VERSION 5.8 ;
BUSBITCHARS "[]" ;
DIVIDERCHAR "/" ;
UNITS
    DATABASE MICRONS 1000 ;
END UNITS

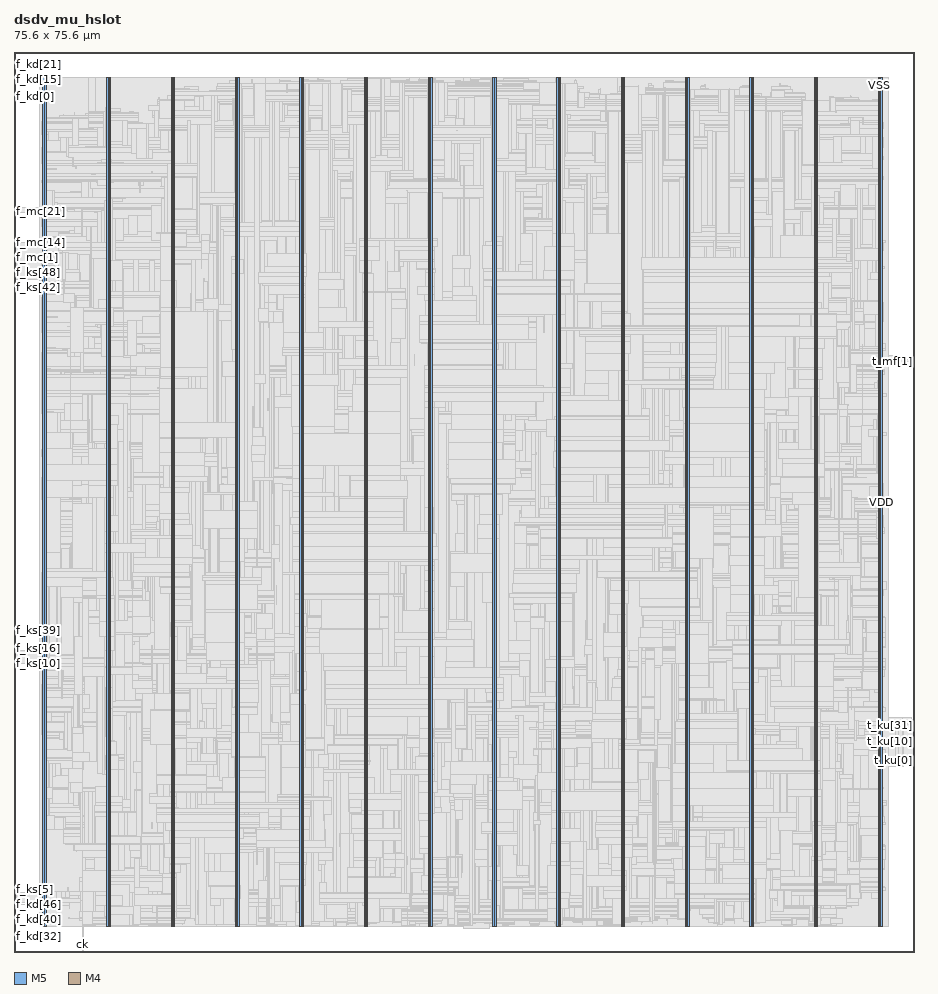
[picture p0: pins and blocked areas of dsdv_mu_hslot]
MACRO dsdv_mu_hslot
  FOREIGN dsdv_mu_hslot 0 0 ;
  CLASS BLOCK ;
  SIZE 75.6 BY 75.6 ;
  PIN ck
    DIRECTION INPUT ;
    USE SIGNAL ;
    PORT
      LAYER M5 ;
        RECT  5.712 0 5.736 0.084 ;
    END
  END ck
  PIN f_kd[0]
    DIRECTION INPUT ;
    USE SIGNAL ;
    PORT
      LAYER M4 ;
        RECT  0 71.856 0.084 71.88 ;
    END
  END f_kd[0]
  PIN f_kd[10]
    DIRECTION INPUT ;
    USE SIGNAL ;
    PORT
      LAYER M4 ;
        RECT  0 72.816 0.084 72.84 ;
    END
  END f_kd[10]
  PIN f_kd[11]
    DIRECTION INPUT ;
    USE SIGNAL ;
    PORT
      LAYER M4 ;
        RECT  0 72.912 0.084 72.936 ;
    END
  END f_kd[11]
  PIN f_kd[12]
    DIRECTION INPUT ;
    USE SIGNAL ;
    PORT
      LAYER M4 ;
        RECT  0 73.008 0.084 73.032 ;
    END
  END f_kd[12]
  PIN f_kd[13]
    DIRECTION INPUT ;
    USE SIGNAL ;
    PORT
      LAYER M4 ;
        RECT  0 73.104 0.084 73.128 ;
    END
  END f_kd[13]
  PIN f_kd[14]
    DIRECTION INPUT ;
    USE SIGNAL ;
    PORT
      LAYER M4 ;
        RECT  0 73.2 0.084 73.224 ;
    END
  END f_kd[14]
  PIN f_kd[15]
    DIRECTION INPUT ;
    USE SIGNAL ;
    PORT
      LAYER M4 ;
        RECT  0 73.296 0.084 73.32 ;
    END
  END f_kd[15]
  PIN f_kd[16]
    DIRECTION INPUT ;
    USE SIGNAL ;
    PORT
      LAYER M4 ;
        RECT  0 73.392 0.084 73.416 ;
    END
  END f_kd[16]
  PIN f_kd[17]
    DIRECTION INPUT ;
    USE SIGNAL ;
    PORT
      LAYER M4 ;
        RECT  0 73.488 0.084 73.512 ;
    END
  END f_kd[17]
  PIN f_kd[18]
    DIRECTION INPUT ;
    USE SIGNAL ;
    PORT
      LAYER M4 ;
        RECT  0 73.584 0.084 73.608 ;
    END
  END f_kd[18]
  PIN f_kd[19]
    DIRECTION INPUT ;
    USE SIGNAL ;
    PORT
      LAYER M4 ;
        RECT  0 73.68 0.084 73.704 ;
    END
  END f_kd[19]
  PIN f_kd[1]
    DIRECTION INPUT ;
    USE SIGNAL ;
    PORT
      LAYER M4 ;
        RECT  0 71.952 0.084 71.976 ;
    END
  END f_kd[1]
  PIN f_kd[20]
    DIRECTION INPUT ;
    USE SIGNAL ;
    PORT
      LAYER M4 ;
        RECT  0 73.776 0.084 73.8 ;
    END
  END f_kd[20]
  PIN f_kd[21]
    DIRECTION INPUT ;
    USE SIGNAL ;
    PORT
      LAYER M4 ;
        RECT  0 73.872 0.084 73.896 ;
    END
  END f_kd[21]
  PIN f_kd[22]
    DIRECTION INPUT ;
    USE SIGNAL ;
    PORT
      LAYER M4 ;
        RECT  0 73.968 0.084 73.992 ;
    END
  END f_kd[22]
  PIN f_kd[23]
    DIRECTION INPUT ;
    USE SIGNAL ;
    PORT
      LAYER M4 ;
        RECT  0 74.064 0.084 74.088 ;
    END
  END f_kd[23]
  PIN f_kd[24]
    DIRECTION INPUT ;
    USE SIGNAL ;
    PORT
      LAYER M4 ;
        RECT  0 74.16 0.084 74.184 ;
    END
  END f_kd[24]
  PIN f_kd[25]
    DIRECTION INPUT ;
    USE SIGNAL ;
    PORT
      LAYER M4 ;
        RECT  0 74.256 0.084 74.28 ;
    END
  END f_kd[25]
  PIN f_kd[26]
    DIRECTION INPUT ;
    USE SIGNAL ;
    PORT
      LAYER M4 ;
        RECT  0 74.352 0.084 74.376 ;
    END
  END f_kd[26]
  PIN f_kd[27]
    DIRECTION INPUT ;
    USE SIGNAL ;
    PORT
      LAYER M4 ;
        RECT  0 74.448 0.084 74.472 ;
    END
  END f_kd[27]
  PIN f_kd[28]
    DIRECTION INPUT ;
    USE SIGNAL ;
    PORT
      LAYER M4 ;
        RECT  0 74.544 0.084 74.568 ;
    END
  END f_kd[28]
  PIN f_kd[29]
    DIRECTION INPUT ;
    USE SIGNAL ;
    PORT
      LAYER M4 ;
        RECT  0 74.64 0.084 74.664 ;
    END
  END f_kd[29]
  PIN f_kd[2]
    DIRECTION INPUT ;
    USE SIGNAL ;
    PORT
      LAYER M4 ;
        RECT  0 72.048 0.084 72.072 ;
    END
  END f_kd[2]
  PIN f_kd[30]
    DIRECTION INPUT ;
    USE SIGNAL ;
    PORT
      LAYER M4 ;
        RECT  0 74.736 0.084 74.76 ;
    END
  END f_kd[30]
  PIN f_kd[31]
    DIRECTION INPUT ;
    USE SIGNAL ;
    PORT
      LAYER M4 ;
        RECT  0 74.832 0.084 74.856 ;
    END
  END f_kd[31]
  PIN f_kd[32]
    DIRECTION INPUT ;
    USE SIGNAL ;
    PORT
      LAYER M4 ;
        RECT  0 1.968 0.084 1.992 ;
    END
  END f_kd[32]
  PIN f_kd[33]
    DIRECTION INPUT ;
    USE SIGNAL ;
    PORT
      LAYER M4 ;
        RECT  0 2.064 0.084 2.088 ;
    END
  END f_kd[33]
  PIN f_kd[34]
    DIRECTION INPUT ;
    USE SIGNAL ;
    PORT
      LAYER M4 ;
        RECT  0 2.16 0.084 2.184 ;
    END
  END f_kd[34]
  PIN f_kd[35]
    DIRECTION INPUT ;
    USE SIGNAL ;
    PORT
      LAYER M4 ;
        RECT  0 2.256 0.084 2.28 ;
    END
  END f_kd[35]
  PIN f_kd[36]
    DIRECTION INPUT ;
    USE SIGNAL ;
    PORT
      LAYER M4 ;
        RECT  0 2.352 0.084 2.376 ;
    END
  END f_kd[36]
  PIN f_kd[37]
    DIRECTION INPUT ;
    USE SIGNAL ;
    PORT
      LAYER M4 ;
        RECT  0 2.448 0.084 2.472 ;
    END
  END f_kd[37]
  PIN f_kd[38]
    DIRECTION INPUT ;
    USE SIGNAL ;
    PORT
      LAYER M4 ;
        RECT  0 2.544 0.084 2.568 ;
    END
  END f_kd[38]
  PIN f_kd[39]
    DIRECTION INPUT ;
    USE SIGNAL ;
    PORT
      LAYER M4 ;
        RECT  0 2.64 0.084 2.664 ;
    END
  END f_kd[39]
  PIN f_kd[3]
    DIRECTION INPUT ;
    USE SIGNAL ;
    PORT
      LAYER M4 ;
        RECT  0 72.144 0.084 72.168 ;
    END
  END f_kd[3]
  PIN f_kd[40]
    DIRECTION INPUT ;
    USE SIGNAL ;
    PORT
      LAYER M4 ;
        RECT  0 2.736 0.084 2.76 ;
    END
  END f_kd[40]
  PIN f_kd[41]
    DIRECTION INPUT ;
    USE SIGNAL ;
    PORT
      LAYER M4 ;
        RECT  0 2.832 0.084 2.856 ;
    END
  END f_kd[41]
  PIN f_kd[42]
    DIRECTION INPUT ;
    USE SIGNAL ;
    PORT
      LAYER M4 ;
        RECT  0 2.928 0.084 2.952 ;
    END
  END f_kd[42]
  PIN f_kd[43]
    DIRECTION INPUT ;
    USE SIGNAL ;
    PORT
      LAYER M4 ;
        RECT  0 3.024 0.084 3.048 ;
    END
  END f_kd[43]
  PIN f_kd[44]
    DIRECTION INPUT ;
    USE SIGNAL ;
    PORT
      LAYER M4 ;
        RECT  0 3.12 0.084 3.144 ;
    END
  END f_kd[44]
  PIN f_kd[45]
    DIRECTION INPUT ;
    USE SIGNAL ;
    PORT
      LAYER M4 ;
        RECT  0 3.216 0.084 3.24 ;
    END
  END f_kd[45]
  PIN f_kd[46]
    DIRECTION INPUT ;
    USE SIGNAL ;
    PORT
      LAYER M4 ;
        RECT  0 3.312 0.084 3.336 ;
    END
  END f_kd[46]
  PIN f_kd[47]
    DIRECTION INPUT ;
    USE SIGNAL ;
    PORT
      LAYER M4 ;
        RECT  0 3.408 0.084 3.432 ;
    END
  END f_kd[47]
  PIN f_kd[48]
    DIRECTION INPUT ;
    USE SIGNAL ;
    PORT
      LAYER M4 ;
        RECT  0 3.504 0.084 3.528 ;
    END
  END f_kd[48]
  PIN f_kd[49]
    DIRECTION INPUT ;
    USE SIGNAL ;
    PORT
      LAYER M4 ;
        RECT  0 3.6 0.084 3.624 ;
    END
  END f_kd[49]
  PIN f_kd[4]
    DIRECTION INPUT ;
    USE SIGNAL ;
    PORT
      LAYER M4 ;
        RECT  0 72.24 0.084 72.264 ;
    END
  END f_kd[4]
  PIN f_kd[50]
    DIRECTION INPUT ;
    USE SIGNAL ;
    PORT
      LAYER M4 ;
        RECT  0 3.696 0.084 3.72 ;
    END
  END f_kd[50]
  PIN f_kd[51]
    DIRECTION INPUT ;
    USE SIGNAL ;
    PORT
      LAYER M4 ;
        RECT  0 3.792 0.084 3.816 ;
    END
  END f_kd[51]
  PIN f_kd[52]
    DIRECTION INPUT ;
    USE SIGNAL ;
    PORT
      LAYER M4 ;
        RECT  0 3.888 0.084 3.912 ;
    END
  END f_kd[52]
  PIN f_kd[53]
    DIRECTION INPUT ;
    USE SIGNAL ;
    PORT
      LAYER M4 ;
        RECT  0 3.984 0.084 4.008 ;
    END
  END f_kd[53]
  PIN f_kd[5]
    DIRECTION INPUT ;
    USE SIGNAL ;
    PORT
      LAYER M4 ;
        RECT  0 72.336 0.084 72.36 ;
    END
  END f_kd[5]
  PIN f_kd[6]
    DIRECTION INPUT ;
    USE SIGNAL ;
    PORT
      LAYER M4 ;
        RECT  0 72.432 0.084 72.456 ;
    END
  END f_kd[6]
  PIN f_kd[7]
    DIRECTION INPUT ;
    USE SIGNAL ;
    PORT
      LAYER M4 ;
        RECT  0 72.528 0.084 72.552 ;
    END
  END f_kd[7]
  PIN f_kd[8]
    DIRECTION INPUT ;
    USE SIGNAL ;
    PORT
      LAYER M4 ;
        RECT  0 72.624 0.084 72.648 ;
    END
  END f_kd[8]
  PIN f_kd[9]
    DIRECTION INPUT ;
    USE SIGNAL ;
    PORT
      LAYER M4 ;
        RECT  0 72.72 0.084 72.744 ;
    END
  END f_kd[9]
  PIN f_ks[0]
    DIRECTION INPUT ;
    USE SIGNAL ;
    PORT
      LAYER M4 ;
        RECT  0 4.08 0.084 4.104 ;
    END
  END f_ks[0]
  PIN f_ks[10]
    DIRECTION INPUT ;
    USE SIGNAL ;
    PORT
      LAYER M4 ;
        RECT  0 24.24 0.084 24.264 ;
    END
  END f_ks[10]
  PIN f_ks[11]
    DIRECTION INPUT ;
    USE SIGNAL ;
    PORT
      LAYER M4 ;
        RECT  0 24.336 0.084 24.36 ;
    END
  END f_ks[11]
  PIN f_ks[12]
    DIRECTION INPUT ;
    USE SIGNAL ;
    PORT
      LAYER M4 ;
        RECT  0 24.432 0.084 24.456 ;
    END
  END f_ks[12]
  PIN f_ks[13]
    DIRECTION INPUT ;
    USE SIGNAL ;
    PORT
      LAYER M4 ;
        RECT  0 24.528 0.084 24.552 ;
    END
  END f_ks[13]
  PIN f_ks[14]
    DIRECTION INPUT ;
    USE SIGNAL ;
    PORT
      LAYER M4 ;
        RECT  0 24.624 0.084 24.648 ;
    END
  END f_ks[14]
  PIN f_ks[15]
    DIRECTION INPUT ;
    USE SIGNAL ;
    PORT
      LAYER M4 ;
        RECT  0 24.72 0.084 24.744 ;
    END
  END f_ks[15]
  PIN f_ks[16]
    DIRECTION INPUT ;
    USE SIGNAL ;
    PORT
      LAYER M4 ;
        RECT  0 24.816 0.084 24.84 ;
    END
  END f_ks[16]
  PIN f_ks[17]
    DIRECTION INPUT ;
    USE SIGNAL ;
    PORT
      LAYER M4 ;
        RECT  0 24.912 0.084 24.936 ;
    END
  END f_ks[17]
  PIN f_ks[18]
    DIRECTION INPUT ;
    USE SIGNAL ;
    PORT
      LAYER M4 ;
        RECT  0 25.008 0.084 25.032 ;
    END
  END f_ks[18]
  PIN f_ks[19]
    DIRECTION INPUT ;
    USE SIGNAL ;
    PORT
      LAYER M4 ;
        RECT  0 25.104 0.084 25.128 ;
    END
  END f_ks[19]
  PIN f_ks[1]
    DIRECTION INPUT ;
    USE SIGNAL ;
    PORT
      LAYER M4 ;
        RECT  0 4.176 0.084 4.2 ;
    END
  END f_ks[1]
  PIN f_ks[20]
    DIRECTION INPUT ;
    USE SIGNAL ;
    PORT
      LAYER M4 ;
        RECT  0 25.2 0.084 25.224 ;
    END
  END f_ks[20]
  PIN f_ks[21]
    DIRECTION INPUT ;
    USE SIGNAL ;
    PORT
      LAYER M4 ;
        RECT  0 25.296 0.084 25.32 ;
    END
  END f_ks[21]
  PIN f_ks[22]
    DIRECTION INPUT ;
    USE SIGNAL ;
    PORT
      LAYER M4 ;
        RECT  0 25.392 0.084 25.416 ;
    END
  END f_ks[22]
  PIN f_ks[23]
    DIRECTION INPUT ;
    USE SIGNAL ;
    PORT
      LAYER M4 ;
        RECT  0 25.488 0.084 25.512 ;
    END
  END f_ks[23]
  PIN f_ks[24]
    DIRECTION INPUT ;
    USE SIGNAL ;
    PORT
      LAYER M4 ;
        RECT  0 25.584 0.084 25.608 ;
    END
  END f_ks[24]
  PIN f_ks[25]
    DIRECTION INPUT ;
    USE SIGNAL ;
    PORT
      LAYER M4 ;
        RECT  0 25.68 0.084 25.704 ;
    END
  END f_ks[25]
  PIN f_ks[26]
    DIRECTION INPUT ;
    USE SIGNAL ;
    PORT
      LAYER M4 ;
        RECT  0 25.776 0.084 25.8 ;
    END
  END f_ks[26]
  PIN f_ks[27]
    DIRECTION INPUT ;
    USE SIGNAL ;
    PORT
      LAYER M4 ;
        RECT  0 25.872 0.084 25.896 ;
    END
  END f_ks[27]
  PIN f_ks[28]
    DIRECTION INPUT ;
    USE SIGNAL ;
    PORT
      LAYER M4 ;
        RECT  0 25.968 0.084 25.992 ;
    END
  END f_ks[28]
  PIN f_ks[29]
    DIRECTION INPUT ;
    USE SIGNAL ;
    PORT
      LAYER M4 ;
        RECT  0 26.064 0.084 26.088 ;
    END
  END f_ks[29]
  PIN f_ks[2]
    DIRECTION INPUT ;
    USE SIGNAL ;
    PORT
      LAYER M4 ;
        RECT  0 4.272 0.084 4.296 ;
    END
  END f_ks[2]
  PIN f_ks[30]
    DIRECTION INPUT ;
    USE SIGNAL ;
    PORT
      LAYER M4 ;
        RECT  0 26.16 0.084 26.184 ;
    END
  END f_ks[30]
  PIN f_ks[31]
    DIRECTION INPUT ;
    USE SIGNAL ;
    PORT
      LAYER M4 ;
        RECT  0 26.256 0.084 26.28 ;
    END
  END f_ks[31]
  PIN f_ks[32]
    DIRECTION INPUT ;
    USE SIGNAL ;
    PORT
      LAYER M4 ;
        RECT  0 26.352 0.084 26.376 ;
    END
  END f_ks[32]
  PIN f_ks[33]
    DIRECTION INPUT ;
    USE SIGNAL ;
    PORT
      LAYER M4 ;
        RECT  0 26.448 0.084 26.472 ;
    END
  END f_ks[33]
  PIN f_ks[34]
    DIRECTION INPUT ;
    USE SIGNAL ;
    PORT
      LAYER M4 ;
        RECT  0 26.544 0.084 26.568 ;
    END
  END f_ks[34]
  PIN f_ks[35]
    DIRECTION INPUT ;
    USE SIGNAL ;
    PORT
      LAYER M4 ;
        RECT  0 26.64 0.084 26.664 ;
    END
  END f_ks[35]
  PIN f_ks[36]
    DIRECTION INPUT ;
    USE SIGNAL ;
    PORT
      LAYER M4 ;
        RECT  0 26.736 0.084 26.76 ;
    END
  END f_ks[36]
  PIN f_ks[37]
    DIRECTION INPUT ;
    USE SIGNAL ;
    PORT
      LAYER M4 ;
        RECT  0 26.832 0.084 26.856 ;
    END
  END f_ks[37]
  PIN f_ks[38]
    DIRECTION INPUT ;
    USE SIGNAL ;
    PORT
      LAYER M4 ;
        RECT  0 26.928 0.084 26.952 ;
    END
  END f_ks[38]
  PIN f_ks[39]
    DIRECTION INPUT ;
    USE SIGNAL ;
    PORT
      LAYER M4 ;
        RECT  0 27.024 0.084 27.048 ;
    END
  END f_ks[39]
  PIN f_ks[3]
    DIRECTION INPUT ;
    USE SIGNAL ;
    PORT
      LAYER M4 ;
        RECT  0 4.368 0.084 4.392 ;
    END
  END f_ks[3]
  PIN f_ks[40]
    DIRECTION INPUT ;
    USE SIGNAL ;
    PORT
      LAYER M4 ;
        RECT  0 27.12 0.084 27.144 ;
    END
  END f_ks[40]
  PIN f_ks[41]
    DIRECTION INPUT ;
    USE SIGNAL ;
    PORT
      LAYER M4 ;
        RECT  0 27.216 0.084 27.24 ;
    END
  END f_ks[41]
  PIN f_ks[42]
    DIRECTION INPUT ;
    USE SIGNAL ;
    PORT
      LAYER M4 ;
        RECT  0 56.496 0.084 56.52 ;
    END
  END f_ks[42]
  PIN f_ks[43]
    DIRECTION INPUT ;
    USE SIGNAL ;
    PORT
      LAYER M4 ;
        RECT  0 56.592 0.084 56.616 ;
    END
  END f_ks[43]
  PIN f_ks[44]
    DIRECTION INPUT ;
    USE SIGNAL ;
    PORT
      LAYER M4 ;
        RECT  0 56.688 0.084 56.712 ;
    END
  END f_ks[44]
  PIN f_ks[45]
    DIRECTION INPUT ;
    USE SIGNAL ;
    PORT
      LAYER M4 ;
        RECT  0 56.784 0.084 56.808 ;
    END
  END f_ks[45]
  PIN f_ks[46]
    DIRECTION INPUT ;
    USE SIGNAL ;
    PORT
      LAYER M4 ;
        RECT  0 56.88 0.084 56.904 ;
    END
  END f_ks[46]
  PIN f_ks[47]
    DIRECTION INPUT ;
    USE SIGNAL ;
    PORT
      LAYER M4 ;
        RECT  0 56.976 0.084 57 ;
    END
  END f_ks[47]
  PIN f_ks[48]
    DIRECTION INPUT ;
    USE SIGNAL ;
    PORT
      LAYER M4 ;
        RECT  0 57.072 0.084 57.096 ;
    END
  END f_ks[48]
  PIN f_ks[49]
    DIRECTION INPUT ;
    USE SIGNAL ;
    PORT
      LAYER M4 ;
        RECT  0 57.168 0.084 57.192 ;
    END
  END f_ks[49]
  PIN f_ks[4]
    DIRECTION INPUT ;
    USE SIGNAL ;
    PORT
      LAYER M4 ;
        RECT  0 4.464 0.084 4.488 ;
    END
  END f_ks[4]
  PIN f_ks[50]
    DIRECTION INPUT ;
    USE SIGNAL ;
    PORT
      LAYER M4 ;
        RECT  0 57.264 0.084 57.288 ;
    END
  END f_ks[50]
  PIN f_ks[51]
    DIRECTION INPUT ;
    USE SIGNAL ;
    PORT
      LAYER M4 ;
        RECT  0 57.36 0.084 57.384 ;
    END
  END f_ks[51]
  PIN f_ks[52]
    DIRECTION INPUT ;
    USE SIGNAL ;
    PORT
      LAYER M4 ;
        RECT  0 57.456 0.084 57.48 ;
    END
  END f_ks[52]
  PIN f_ks[5]
    DIRECTION INPUT ;
    USE SIGNAL ;
    PORT
      LAYER M4 ;
        RECT  0 4.56 0.084 4.584 ;
    END
  END f_ks[5]
  PIN f_ks[6]
    DIRECTION INPUT ;
    USE SIGNAL ;
    PORT
      LAYER M4 ;
        RECT  0 4.656 0.084 4.68 ;
    END
  END f_ks[6]
  PIN f_ks[7]
    DIRECTION INPUT ;
    USE SIGNAL ;
    PORT
      LAYER M4 ;
        RECT  0 4.752 0.084 4.776 ;
    END
  END f_ks[7]
  PIN f_ks[8]
    DIRECTION INPUT ;
    USE SIGNAL ;
    PORT
      LAYER M4 ;
        RECT  0 4.848 0.084 4.872 ;
    END
  END f_ks[8]
  PIN f_ks[9]
    DIRECTION INPUT ;
    USE SIGNAL ;
    PORT
      LAYER M4 ;
        RECT  0 4.944 0.084 4.968 ;
    END
  END f_ks[9]
  PIN f_mc[0]
    DIRECTION INPUT ;
    USE SIGNAL ;
    PORT
      LAYER M4 ;
        RECT  0 57.552 0.084 57.576 ;
    END
  END f_mc[0]
  PIN f_mc[10]
    DIRECTION INPUT ;
    USE SIGNAL ;
    PORT
      LAYER M4 ;
        RECT  0 58.512 0.084 58.536 ;
    END
  END f_mc[10]
  PIN f_mc[11]
    DIRECTION INPUT ;
    USE SIGNAL ;
    PORT
      LAYER M4 ;
        RECT  0 58.608 0.084 58.632 ;
    END
  END f_mc[11]
  PIN f_mc[12]
    DIRECTION INPUT ;
    USE SIGNAL ;
    PORT
      LAYER M4 ;
        RECT  0 58.704 0.084 58.728 ;
    END
  END f_mc[12]
  PIN f_mc[13]
    DIRECTION INPUT ;
    USE SIGNAL ;
    PORT
      LAYER M4 ;
        RECT  0 58.8 0.084 58.824 ;
    END
  END f_mc[13]
  PIN f_mc[14]
    DIRECTION INPUT ;
    USE SIGNAL ;
    PORT
      LAYER M4 ;
        RECT  0 58.896 0.084 58.92 ;
    END
  END f_mc[14]
  PIN f_mc[15]
    DIRECTION INPUT ;
    USE SIGNAL ;
    PORT
      LAYER M4 ;
        RECT  0 58.992 0.084 59.016 ;
    END
  END f_mc[15]
  PIN f_mc[16]
    DIRECTION INPUT ;
    USE SIGNAL ;
    PORT
      LAYER M4 ;
        RECT  0 59.088 0.084 59.112 ;
    END
  END f_mc[16]
  PIN f_mc[17]
    DIRECTION INPUT ;
    USE SIGNAL ;
    PORT
      LAYER M4 ;
        RECT  0 59.184 0.084 59.208 ;
    END
  END f_mc[17]
  PIN f_mc[18]
    DIRECTION INPUT ;
    USE SIGNAL ;
    PORT
      LAYER M4 ;
        RECT  0 59.28 0.084 59.304 ;
    END
  END f_mc[18]
  PIN f_mc[19]
    DIRECTION INPUT ;
    USE SIGNAL ;
    PORT
      LAYER M4 ;
        RECT  0 59.376 0.084 59.4 ;
    END
  END f_mc[19]
  PIN f_mc[1]
    DIRECTION INPUT ;
    USE SIGNAL ;
    PORT
      LAYER M4 ;
        RECT  0 57.648 0.084 57.672 ;
    END
  END f_mc[1]
  PIN f_mc[20]
    DIRECTION INPUT ;
    USE SIGNAL ;
    PORT
      LAYER M4 ;
        RECT  0 59.472 0.084 59.496 ;
    END
  END f_mc[20]
  PIN f_mc[21]
    DIRECTION INPUT ;
    USE SIGNAL ;
    PORT
      LAYER M4 ;
        RECT  0 62.16 0.084 62.184 ;
    END
  END f_mc[21]
  PIN f_mc[22]
    DIRECTION INPUT ;
    USE SIGNAL ;
    PORT
      LAYER M4 ;
        RECT  0 62.256 0.084 62.28 ;
    END
  END f_mc[22]
  PIN f_mc[23]
    DIRECTION INPUT ;
    USE SIGNAL ;
    PORT
      LAYER M4 ;
        RECT  0 62.352 0.084 62.376 ;
    END
  END f_mc[23]
  PIN f_mc[24]
    DIRECTION INPUT ;
    USE SIGNAL ;
    PORT
      LAYER M4 ;
        RECT  0 62.448 0.084 62.472 ;
    END
  END f_mc[24]
  PIN f_mc[25]
    DIRECTION INPUT ;
    USE SIGNAL ;
    PORT
      LAYER M4 ;
        RECT  0 62.544 0.084 62.568 ;
    END
  END f_mc[25]
  PIN f_mc[2]
    DIRECTION INPUT ;
    USE SIGNAL ;
    PORT
      LAYER M4 ;
        RECT  0 57.744 0.084 57.768 ;
    END
  END f_mc[2]
  PIN f_mc[3]
    DIRECTION INPUT ;
    USE SIGNAL ;
    PORT
      LAYER M4 ;
        RECT  0 57.84 0.084 57.864 ;
    END
  END f_mc[3]
  PIN f_mc[4]
    DIRECTION INPUT ;
    USE SIGNAL ;
    PORT
      LAYER M4 ;
        RECT  0 57.936 0.084 57.96 ;
    END
  END f_mc[4]
  PIN f_mc[5]
    DIRECTION INPUT ;
    USE SIGNAL ;
    PORT
      LAYER M4 ;
        RECT  0 58.032 0.084 58.056 ;
    END
  END f_mc[5]
  PIN f_mc[6]
    DIRECTION INPUT ;
    USE SIGNAL ;
    PORT
      LAYER M4 ;
        RECT  0 58.128 0.084 58.152 ;
    END
  END f_mc[6]
  PIN f_mc[7]
    DIRECTION INPUT ;
    USE SIGNAL ;
    PORT
      LAYER M4 ;
        RECT  0 58.224 0.084 58.248 ;
    END
  END f_mc[7]
  PIN f_mc[8]
    DIRECTION INPUT ;
    USE SIGNAL ;
    PORT
      LAYER M4 ;
        RECT  0 58.32 0.084 58.344 ;
    END
  END f_mc[8]
  PIN f_mc[9]
    DIRECTION INPUT ;
    USE SIGNAL ;
    PORT
      LAYER M4 ;
        RECT  0 58.416 0.084 58.44 ;
    END
  END f_mc[9]
  PIN rst_n
    DIRECTION INPUT ;
    USE SIGNAL ;
    PORT
      LAYER M5 ;
        RECT  5.808 0 5.832 0.084 ;
    END
  END rst_n
  PIN t_ku[0]
    DIRECTION OUTPUT ;
    USE SIGNAL ;
    PORT
      LAYER M4 ;
        RECT  75.516 16.08 75.6 16.104 ;
    END
  END t_ku[0]
  PIN t_ku[10]
    DIRECTION OUTPUT ;
    USE SIGNAL ;
    PORT
      LAYER M4 ;
        RECT  75.516 17.04 75.6 17.064 ;
    END
  END t_ku[10]
  PIN t_ku[11]
    DIRECTION OUTPUT ;
    USE SIGNAL ;
    PORT
      LAYER M4 ;
        RECT  75.516 17.136 75.6 17.16 ;
    END
  END t_ku[11]
  PIN t_ku[12]
    DIRECTION OUTPUT ;
    USE SIGNAL ;
    PORT
      LAYER M4 ;
        RECT  75.516 17.232 75.6 17.256 ;
    END
  END t_ku[12]
  PIN t_ku[13]
    DIRECTION OUTPUT ;
    USE SIGNAL ;
    PORT
      LAYER M4 ;
        RECT  75.516 17.328 75.6 17.352 ;
    END
  END t_ku[13]
  PIN t_ku[14]
    DIRECTION OUTPUT ;
    USE SIGNAL ;
    PORT
      LAYER M4 ;
        RECT  75.516 17.424 75.6 17.448 ;
    END
  END t_ku[14]
  PIN t_ku[15]
    DIRECTION OUTPUT ;
    USE SIGNAL ;
    PORT
      LAYER M4 ;
        RECT  75.516 17.52 75.6 17.544 ;
    END
  END t_ku[15]
  PIN t_ku[16]
    DIRECTION OUTPUT ;
    USE SIGNAL ;
    PORT
      LAYER M4 ;
        RECT  75.516 17.616 75.6 17.64 ;
    END
  END t_ku[16]
  PIN t_ku[17]
    DIRECTION OUTPUT ;
    USE SIGNAL ;
    PORT
      LAYER M4 ;
        RECT  75.516 17.712 75.6 17.736 ;
    END
  END t_ku[17]
  PIN t_ku[18]
    DIRECTION OUTPUT ;
    USE SIGNAL ;
    PORT
      LAYER M4 ;
        RECT  75.516 17.808 75.6 17.832 ;
    END
  END t_ku[18]
  PIN t_ku[19]
    DIRECTION OUTPUT ;
    USE SIGNAL ;
    PORT
      LAYER M4 ;
        RECT  75.516 17.904 75.6 17.928 ;
    END
  END t_ku[19]
  PIN t_ku[1]
    DIRECTION OUTPUT ;
    USE SIGNAL ;
    PORT
      LAYER M4 ;
        RECT  75.516 16.176 75.6 16.2 ;
    END
  END t_ku[1]
  PIN t_ku[20]
    DIRECTION OUTPUT ;
    USE SIGNAL ;
    PORT
      LAYER M4 ;
        RECT  75.516 18 75.6 18.024 ;
    END
  END t_ku[20]
  PIN t_ku[21]
    DIRECTION OUTPUT ;
    USE SIGNAL ;
    PORT
      LAYER M4 ;
        RECT  75.516 18.096 75.6 18.12 ;
    END
  END t_ku[21]
  PIN t_ku[22]
    DIRECTION OUTPUT ;
    USE SIGNAL ;
    PORT
      LAYER M4 ;
        RECT  75.516 18.192 75.6 18.216 ;
    END
  END t_ku[22]
  PIN t_ku[23]
    DIRECTION OUTPUT ;
    USE SIGNAL ;
    PORT
      LAYER M4 ;
        RECT  75.516 18.288 75.6 18.312 ;
    END
  END t_ku[23]
  PIN t_ku[24]
    DIRECTION OUTPUT ;
    USE SIGNAL ;
    PORT
      LAYER M4 ;
        RECT  75.516 18.384 75.6 18.408 ;
    END
  END t_ku[24]
  PIN t_ku[25]
    DIRECTION OUTPUT ;
    USE SIGNAL ;
    PORT
      LAYER M4 ;
        RECT  75.516 18.48 75.6 18.504 ;
    END
  END t_ku[25]
  PIN t_ku[26]
    DIRECTION OUTPUT ;
    USE SIGNAL ;
    PORT
      LAYER M4 ;
        RECT  75.516 18.576 75.6 18.6 ;
    END
  END t_ku[26]
  PIN t_ku[27]
    DIRECTION OUTPUT ;
    USE SIGNAL ;
    PORT
      LAYER M4 ;
        RECT  75.516 18.672 75.6 18.696 ;
    END
  END t_ku[27]
  PIN t_ku[28]
    DIRECTION OUTPUT ;
    USE SIGNAL ;
    PORT
      LAYER M4 ;
        RECT  75.516 18.768 75.6 18.792 ;
    END
  END t_ku[28]
  PIN t_ku[29]
    DIRECTION OUTPUT ;
    USE SIGNAL ;
    PORT
      LAYER M4 ;
        RECT  75.516 18.864 75.6 18.888 ;
    END
  END t_ku[29]
  PIN t_ku[2]
    DIRECTION OUTPUT ;
    USE SIGNAL ;
    PORT
      LAYER M4 ;
        RECT  75.516 16.272 75.6 16.296 ;
    END
  END t_ku[2]
  PIN t_ku[30]
    DIRECTION OUTPUT ;
    USE SIGNAL ;
    PORT
      LAYER M4 ;
        RECT  75.516 18.96 75.6 18.984 ;
    END
  END t_ku[30]
  PIN t_ku[31]
    DIRECTION OUTPUT ;
    USE SIGNAL ;
    PORT
      LAYER M4 ;
        RECT  75.516 19.056 75.6 19.08 ;
    END
  END t_ku[31]
  PIN t_ku[3]
    DIRECTION OUTPUT ;
    USE SIGNAL ;
    PORT
      LAYER M4 ;
        RECT  75.516 16.368 75.6 16.392 ;
    END
  END t_ku[3]
  PIN t_ku[4]
    DIRECTION OUTPUT ;
    USE SIGNAL ;
    PORT
      LAYER M4 ;
        RECT  75.516 16.464 75.6 16.488 ;
    END
  END t_ku[4]
  PIN t_ku[5]
    DIRECTION OUTPUT ;
    USE SIGNAL ;
    PORT
      LAYER M4 ;
        RECT  75.516 16.56 75.6 16.584 ;
    END
  END t_ku[5]
  PIN t_ku[6]
    DIRECTION OUTPUT ;
    USE SIGNAL ;
    PORT
      LAYER M4 ;
        RECT  75.516 16.656 75.6 16.68 ;
    END
  END t_ku[6]
  PIN t_ku[7]
    DIRECTION OUTPUT ;
    USE SIGNAL ;
    PORT
      LAYER M4 ;
        RECT  75.516 16.752 75.6 16.776 ;
    END
  END t_ku[7]
  PIN t_ku[8]
    DIRECTION OUTPUT ;
    USE SIGNAL ;
    PORT
      LAYER M4 ;
        RECT  75.516 16.848 75.6 16.872 ;
    END
  END t_ku[8]
  PIN t_ku[9]
    DIRECTION OUTPUT ;
    USE SIGNAL ;
    PORT
      LAYER M4 ;
        RECT  75.516 16.944 75.6 16.968 ;
    END
  END t_ku[9]
  PIN t_mf[0]
    DIRECTION OUTPUT ;
    USE SIGNAL ;
    PORT
      LAYER M4 ;
        RECT  75.516 49.488 75.6 49.512 ;
    END
  END t_mf[0]
  PIN t_mf[1]
    DIRECTION OUTPUT ;
    USE SIGNAL ;
    PORT
      LAYER M4 ;
        RECT  75.516 49.584 75.6 49.608 ;
    END
  END t_mf[1]
  PIN t_mf[2]
    DIRECTION OUTPUT ;
    USE SIGNAL ;
    PORT
      LAYER M4 ;
        RECT  75.516 49.68 75.6 49.704 ;
    END
  END t_mf[2]
  PIN t_mf[3]
    DIRECTION OUTPUT ;
    USE SIGNAL ;
    PORT
      LAYER M4 ;
        RECT  75.516 49.776 75.6 49.8 ;
    END
  END t_mf[3]
  PIN VDD
    DIRECTION INOUT ;
    USE POWER ;
    PORT
      LAYER M5 ;
        RECT  72.792 2.151 72.912 73.449 ;
        RECT  67.392 2.151 67.512 73.449 ;
        RECT  61.992 2.151 62.112 73.449 ;
        RECT  56.592 2.151 56.712 73.449 ;
        RECT  51.192 2.151 51.312 73.449 ;
        RECT  45.792 2.151 45.912 73.449 ;
        RECT  40.392 2.151 40.512 73.449 ;
        RECT  34.992 2.151 35.112 73.449 ;
        RECT  29.592 2.151 29.712 73.449 ;
        RECT  24.192 2.151 24.312 73.449 ;
        RECT  18.792 2.151 18.912 73.449 ;
        RECT  13.392 2.151 13.512 73.449 ;
        RECT  7.992 2.151 8.112 73.449 ;
        RECT  2.592 2.151 2.712 73.449 ;
    END
  END VDD
  PIN VSS
    DIRECTION INOUT ;
    USE GROUND ;
    PORT
      LAYER M5 ;
        RECT  72.6 2.137 72.72 73.463 ;
        RECT  67.2 2.137 67.32 73.463 ;
        RECT  61.8 2.137 61.92 73.463 ;
        RECT  56.4 2.137 56.52 73.463 ;
        RECT  51 2.137 51.12 73.463 ;
        RECT  45.6 2.137 45.72 73.463 ;
        RECT  40.2 2.137 40.32 73.463 ;
        RECT  34.8 2.137 34.92 73.463 ;
        RECT  29.4 2.137 29.52 73.463 ;
        RECT  24 2.137 24.12 73.463 ;
        RECT  18.6 2.137 18.72 73.463 ;
        RECT  13.2 2.137 13.32 73.463 ;
        RECT  7.8 2.137 7.92 73.463 ;
        RECT  2.4 2.137 2.52 73.463 ;
    END
  END VSS
  OBS
    LAYER RVTN ;
     RECT  2.16 2.16 73.44 2.295 ;
     RECT  2.16 2.565 73.44 2.835 ;
     RECT  2.16 3.105 73.44 3.375 ;
     RECT  2.16 3.645 73.44 3.915 ;
     RECT  2.16 4.185 73.44 4.455 ;
     RECT  2.16 4.725 73.44 4.995 ;
     RECT  2.16 5.265 73.44 5.535 ;
     RECT  2.16 5.805 73.44 6.075 ;
     RECT  2.16 6.345 73.44 6.615 ;
     RECT  2.16 6.885 73.44 7.155 ;
     RECT  2.16 7.425 73.44 7.695 ;
     RECT  2.16 7.965 73.44 8.235 ;
     RECT  2.16 8.505 73.44 8.775 ;
     RECT  2.16 9.045 73.44 9.315 ;
     RECT  2.16 9.585 73.44 9.855 ;
     RECT  2.16 10.125 73.44 10.395 ;
     RECT  2.16 10.665 73.44 10.935 ;
     RECT  2.16 11.205 73.44 11.475 ;
     RECT  2.16 11.745 73.44 12.015 ;
     RECT  2.16 12.285 73.44 12.555 ;
     RECT  2.16 12.825 73.44 13.095 ;
     RECT  2.16 13.365 73.44 13.635 ;
     RECT  2.16 13.905 73.44 14.175 ;
     RECT  2.16 14.445 73.44 14.715 ;
     RECT  2.16 14.985 73.44 15.255 ;
     RECT  2.16 15.525 73.44 15.795 ;
     RECT  2.16 16.065 73.44 16.335 ;
     RECT  2.16 16.605 73.44 16.875 ;
     RECT  2.16 17.145 73.44 17.415 ;
     RECT  2.16 17.685 73.44 17.955 ;
     RECT  2.16 18.225 73.44 18.495 ;
     RECT  2.16 18.765 73.44 19.035 ;
     RECT  2.16 19.305 73.44 19.575 ;
     RECT  2.16 19.845 73.44 20.115 ;
     RECT  2.16 20.385 73.44 20.655 ;
     RECT  2.16 20.925 73.44 21.195 ;
     RECT  2.16 21.465 73.44 21.735 ;
     RECT  2.16 22.005 73.44 22.275 ;
     RECT  2.16 22.545 73.44 22.815 ;
     RECT  2.16 23.085 73.44 23.355 ;
     RECT  2.16 23.625 73.44 23.895 ;
     RECT  2.16 24.165 73.44 24.435 ;
     RECT  2.16 24.705 73.44 24.975 ;
     RECT  2.16 25.245 73.44 25.515 ;
     RECT  2.16 25.785 73.44 26.055 ;
     RECT  2.16 26.325 73.44 26.595 ;
     RECT  2.16 26.865 73.44 27.135 ;
     RECT  2.16 27.405 73.44 27.675 ;
     RECT  2.16 27.945 73.44 28.215 ;
     RECT  2.16 28.485 73.44 28.755 ;
     RECT  2.16 29.025 73.44 29.295 ;
     RECT  2.16 29.565 73.44 29.835 ;
     RECT  2.16 30.105 73.44 30.375 ;
     RECT  2.16 30.645 73.44 30.915 ;
     RECT  2.16 31.185 73.44 31.455 ;
     RECT  2.16 31.725 73.44 31.995 ;
     RECT  2.16 32.265 73.44 32.535 ;
     RECT  2.16 32.805 73.44 33.075 ;
     RECT  2.16 33.345 73.44 33.615 ;
     RECT  2.16 33.885 73.44 34.155 ;
     RECT  2.16 34.425 73.44 34.695 ;
     RECT  2.16 34.965 73.44 35.235 ;
     RECT  2.16 35.505 73.44 35.775 ;
     RECT  2.16 36.045 73.44 36.315 ;
     RECT  2.16 36.585 73.44 36.855 ;
     RECT  2.16 37.125 73.44 37.395 ;
     RECT  2.16 37.665 73.44 37.935 ;
     RECT  2.16 38.205 73.44 38.475 ;
     RECT  2.16 38.745 73.44 39.015 ;
     RECT  2.16 39.285 73.44 39.555 ;
     RECT  2.16 39.825 73.44 40.095 ;
     RECT  2.16 40.365 73.44 40.635 ;
     RECT  2.16 40.905 73.44 41.175 ;
     RECT  2.16 41.445 73.44 41.715 ;
     RECT  2.16 41.985 73.44 42.255 ;
     RECT  2.16 42.525 73.44 42.795 ;
     RECT  2.16 43.065 73.44 43.335 ;
     RECT  2.16 43.605 73.44 43.875 ;
     RECT  2.16 44.145 73.44 44.415 ;
     RECT  2.16 44.685 73.44 44.955 ;
     RECT  2.16 45.225 73.44 45.495 ;
     RECT  2.16 45.765 73.44 46.035 ;
     RECT  2.16 46.305 73.44 46.575 ;
     RECT  2.16 46.845 73.44 47.115 ;
     RECT  2.16 47.385 73.44 47.655 ;
     RECT  2.16 47.925 73.44 48.195 ;
     RECT  2.16 48.465 73.44 48.735 ;
     RECT  2.16 49.005 73.44 49.275 ;
     RECT  2.16 49.545 73.44 49.815 ;
     RECT  2.16 50.085 73.44 50.355 ;
     RECT  2.16 50.625 73.44 50.895 ;
     RECT  2.16 51.165 73.44 51.435 ;
     RECT  2.16 51.705 73.44 51.975 ;
     RECT  2.16 52.245 73.44 52.515 ;
     RECT  2.16 52.785 73.44 53.055 ;
     RECT  2.16 53.325 73.44 53.595 ;
     RECT  2.16 53.865 73.44 54.135 ;
     RECT  2.16 54.405 73.44 54.675 ;
     RECT  2.16 54.945 73.44 55.215 ;
     RECT  2.16 55.485 73.44 55.755 ;
     RECT  2.16 56.025 73.44 56.295 ;
     RECT  2.16 56.565 73.44 56.835 ;
     RECT  2.16 57.105 73.44 57.375 ;
     RECT  2.16 57.645 73.44 57.915 ;
     RECT  2.16 58.185 73.44 58.455 ;
     RECT  2.16 58.725 73.44 58.995 ;
     RECT  2.16 59.265 73.44 59.535 ;
     RECT  2.16 59.805 73.44 60.075 ;
     RECT  2.16 60.345 73.44 60.615 ;
     RECT  2.16 60.885 73.44 61.155 ;
     RECT  2.16 61.425 73.44 61.695 ;
     RECT  2.16 61.965 73.44 62.235 ;
     RECT  2.16 62.505 73.44 62.775 ;
     RECT  2.16 63.045 73.44 63.315 ;
     RECT  2.16 63.585 73.44 63.855 ;
     RECT  2.16 64.125 73.44 64.395 ;
     RECT  2.16 64.665 73.44 64.935 ;
     RECT  2.16 65.205 73.44 65.475 ;
     RECT  2.16 65.745 73.44 66.015 ;
     RECT  2.16 66.285 73.44 66.555 ;
     RECT  2.16 66.825 73.44 67.095 ;
     RECT  2.16 67.365 73.44 67.635 ;
     RECT  2.16 67.905 73.44 68.175 ;
     RECT  2.16 68.445 73.44 68.715 ;
     RECT  2.16 68.985 73.44 69.255 ;
     RECT  2.16 69.525 73.44 69.795 ;
     RECT  2.16 70.065 73.44 70.335 ;
     RECT  2.16 70.605 73.44 70.875 ;
     RECT  2.16 71.145 73.44 71.415 ;
     RECT  2.16 71.685 73.44 71.955 ;
     RECT  2.16 72.225 73.44 72.495 ;
     RECT  2.16 72.765 73.44 73.035 ;
     RECT  2.16 73.305 73.44 73.44 ;
    LAYER RVTP ;
     RECT  2.16 2.295 73.44 2.565 ;
     RECT  2.16 2.835 73.44 3.105 ;
     RECT  2.16 3.375 73.44 3.645 ;
     RECT  2.16 3.915 73.44 4.185 ;
     RECT  2.16 4.455 73.44 4.725 ;
     RECT  2.16 4.995 73.44 5.265 ;
     RECT  2.16 5.535 73.44 5.805 ;
     RECT  2.16 6.075 73.44 6.345 ;
     RECT  2.16 6.615 73.44 6.885 ;
     RECT  2.16 7.155 73.44 7.425 ;
     RECT  2.16 7.695 73.44 7.965 ;
     RECT  2.16 8.235 73.44 8.505 ;
     RECT  2.16 8.775 73.44 9.045 ;
     RECT  2.16 9.315 73.44 9.585 ;
     RECT  2.16 9.855 73.44 10.125 ;
     RECT  2.16 10.395 73.44 10.665 ;
     RECT  2.16 10.935 73.44 11.205 ;
     RECT  2.16 11.475 73.44 11.745 ;
     RECT  2.16 12.015 73.44 12.285 ;
     RECT  2.16 12.555 73.44 12.825 ;
     RECT  2.16 13.095 73.44 13.365 ;
     RECT  2.16 13.635 73.44 13.905 ;
     RECT  2.16 14.175 73.44 14.445 ;
     RECT  2.16 14.715 73.44 14.985 ;
     RECT  2.16 15.255 73.44 15.525 ;
     RECT  2.16 15.795 73.44 16.065 ;
     RECT  2.16 16.335 73.44 16.605 ;
     RECT  2.16 16.875 73.44 17.145 ;
     RECT  2.16 17.415 73.44 17.685 ;
     RECT  2.16 17.955 73.44 18.225 ;
     RECT  2.16 18.495 73.44 18.765 ;
     RECT  2.16 19.035 73.44 19.305 ;
     RECT  2.16 19.575 73.44 19.845 ;
     RECT  2.16 20.115 73.44 20.385 ;
     RECT  2.16 20.655 73.44 20.925 ;
     RECT  2.16 21.195 73.44 21.465 ;
     RECT  2.16 21.735 73.44 22.005 ;
     RECT  2.16 22.275 73.44 22.545 ;
     RECT  2.16 22.815 73.44 23.085 ;
     RECT  2.16 23.355 73.44 23.625 ;
     RECT  2.16 23.895 73.44 24.165 ;
     RECT  2.16 24.435 73.44 24.705 ;
     RECT  2.16 24.975 73.44 25.245 ;
     RECT  2.16 25.515 73.44 25.785 ;
     RECT  2.16 26.055 73.44 26.325 ;
     RECT  2.16 26.595 73.44 26.865 ;
     RECT  2.16 27.135 73.44 27.405 ;
     RECT  2.16 27.675 73.44 27.945 ;
     RECT  2.16 28.215 73.44 28.485 ;
     RECT  2.16 28.755 73.44 29.025 ;
     RECT  2.16 29.295 73.44 29.565 ;
     RECT  2.16 29.835 73.44 30.105 ;
     RECT  2.16 30.375 73.44 30.645 ;
     RECT  2.16 30.915 73.44 31.185 ;
     RECT  2.16 31.455 73.44 31.725 ;
     RECT  2.16 31.995 73.44 32.265 ;
     RECT  2.16 32.535 73.44 32.805 ;
     RECT  2.16 33.075 73.44 33.345 ;
     RECT  2.16 33.615 73.44 33.885 ;
     RECT  2.16 34.155 73.44 34.425 ;
     RECT  2.16 34.695 73.44 34.965 ;
     RECT  2.16 35.235 73.44 35.505 ;
     RECT  2.16 35.775 73.44 36.045 ;
     RECT  2.16 36.315 73.44 36.585 ;
     RECT  2.16 36.855 73.44 37.125 ;
     RECT  2.16 37.395 73.44 37.665 ;
     RECT  2.16 37.935 73.44 38.205 ;
     RECT  2.16 38.475 73.44 38.745 ;
     RECT  2.16 39.015 73.44 39.285 ;
     RECT  2.16 39.555 73.44 39.825 ;
     RECT  2.16 40.095 73.44 40.365 ;
     RECT  2.16 40.635 73.44 40.905 ;
     RECT  2.16 41.175 73.44 41.445 ;
     RECT  2.16 41.715 73.44 41.985 ;
     RECT  2.16 42.255 73.44 42.525 ;
     RECT  2.16 42.795 73.44 43.065 ;
     RECT  2.16 43.335 73.44 43.605 ;
     RECT  2.16 43.875 73.44 44.145 ;
     RECT  2.16 44.415 73.44 44.685 ;
     RECT  2.16 44.955 73.44 45.225 ;
     RECT  2.16 45.495 73.44 45.765 ;
     RECT  2.16 46.035 73.44 46.305 ;
     RECT  2.16 46.575 73.44 46.845 ;
     RECT  2.16 47.115 73.44 47.385 ;
     RECT  2.16 47.655 73.44 47.925 ;
     RECT  2.16 48.195 73.44 48.465 ;
     RECT  2.16 48.735 73.44 49.005 ;
     RECT  2.16 49.275 73.44 49.545 ;
     RECT  2.16 49.815 73.44 50.085 ;
     RECT  2.16 50.355 73.44 50.625 ;
     RECT  2.16 50.895 73.44 51.165 ;
     RECT  2.16 51.435 73.44 51.705 ;
     RECT  2.16 51.975 73.44 52.245 ;
     RECT  2.16 52.515 73.44 52.785 ;
     RECT  2.16 53.055 73.44 53.325 ;
     RECT  2.16 53.595 73.44 53.865 ;
     RECT  2.16 54.135 73.44 54.405 ;
     RECT  2.16 54.675 73.44 54.945 ;
     RECT  2.16 55.215 73.44 55.485 ;
     RECT  2.16 55.755 73.44 56.025 ;
     RECT  2.16 56.295 73.44 56.565 ;
     RECT  2.16 56.835 73.44 57.105 ;
     RECT  2.16 57.375 73.44 57.645 ;
     RECT  2.16 57.915 73.44 58.185 ;
     RECT  2.16 58.455 73.44 58.725 ;
     RECT  2.16 58.995 73.44 59.265 ;
     RECT  2.16 59.535 73.44 59.805 ;
     RECT  2.16 60.075 73.44 60.345 ;
     RECT  2.16 60.615 73.44 60.885 ;
     RECT  2.16 61.155 73.44 61.425 ;
     RECT  2.16 61.695 73.44 61.965 ;
     RECT  2.16 62.235 73.44 62.505 ;
     RECT  2.16 62.775 73.44 63.045 ;
     RECT  2.16 63.315 73.44 63.585 ;
     RECT  2.16 63.855 73.44 64.125 ;
     RECT  2.16 64.395 73.44 64.665 ;
     RECT  2.16 64.935 73.44 65.205 ;
     RECT  2.16 65.475 73.44 65.745 ;
     RECT  2.16 66.015 73.44 66.285 ;
     RECT  2.16 66.555 73.44 66.825 ;
     RECT  2.16 67.095 73.44 67.365 ;
     RECT  2.16 67.635 73.44 67.905 ;
     RECT  2.16 68.175 73.44 68.445 ;
     RECT  2.16 68.715 73.44 68.985 ;
     RECT  2.16 69.255 73.44 69.525 ;
     RECT  2.16 69.795 73.44 70.065 ;
     RECT  2.16 70.335 73.44 70.605 ;
     RECT  2.16 70.875 73.44 71.145 ;
     RECT  2.16 71.415 73.44 71.685 ;
     RECT  2.16 71.955 73.44 72.225 ;
     RECT  2.16 72.495 73.44 72.765 ;
     RECT  2.16 73.035 73.44 73.305 ;
    LAYER M1 ;
     RECT  2.16 2.151 73.44 73.449 ;
    LAYER M2 ;
     RECT  0.103 4.734 0.347 4.752 ;
     RECT  0.211 3.96 2.16 3.978 ;
     RECT  2.155 57.852 2.16 57.87 ;
     RECT  2.16 2.151 6.259 73.449 ;
     RECT  6.259 2.106 6.827 73.449 ;
     RECT  6.827 2.151 34.051 73.449 ;
     RECT  34.051 2.151 37.759 73.494 ;
     RECT  37.759 1.998 39.947 73.494 ;
     RECT  39.947 2.151 41.359 73.494 ;
     RECT  41.359 2.106 41.459 73.494 ;
     RECT  41.459 2.106 41.567 73.449 ;
     RECT  41.567 2.151 45.463 73.449 ;
     RECT  45.463 2.106 50.675 73.449 ;
     RECT  50.675 2.151 73.44 73.449 ;
     RECT  73.44 49.446 74.111 50.112 ;
     RECT  73.44 15.606 74.651 19.674 ;
     RECT  74.111 49.446 74.651 50.004 ;
     RECT  74.651 15.606 74.687 17.982 ;
     RECT  74.651 49.446 74.687 49.734 ;
     RECT  74.687 15.696 74.759 17.982 ;
     RECT  74.759 15.696 74.795 16.632 ;
     RECT  74.795 15.966 74.831 16.632 ;
     RECT  74.831 16.614 74.867 16.632 ;
     RECT  74.651 18.774 75.407 19.674 ;
     RECT  74.759 17.424 75.415 17.982 ;
     RECT  75.407 18.774 75.415 19.494 ;
     RECT  75.415 17.424 75.479 19.494 ;
     RECT  75.479 17.424 75.515 18.954 ;
     RECT  74.687 49.716 75.515 49.734 ;
    LAYER M3 ;
     RECT  5.76 1.723 5.778 2.101 ;
     RECT  39.924 1.993 39.942 2.143 ;
     RECT  45.468 2.101 45.486 2.143 ;
     RECT  50.652 2.101 50.67 2.143 ;
     RECT  5.76 2.101 6.822 2.191 ;
     RECT  49.788 2.101 49.806 2.191 ;
     RECT  50.652 2.143 51.105 2.191 ;
     RECT  7.815 2.143 7.905 2.227 ;
     RECT  21.42 2.203 21.438 2.227 ;
     RECT  24.015 2.143 24.105 2.227 ;
     RECT  25.668 2.191 25.686 2.227 ;
     RECT  29.415 2.143 29.505 2.227 ;
     RECT  37.764 1.993 37.782 2.227 ;
     RECT  41.364 2.101 41.562 2.227 ;
     RECT  49.788 2.191 51.105 2.227 ;
     RECT  7.815 2.227 8.154 2.251 ;
     RECT  10.404 2.227 10.422 2.251 ;
     RECT  37.656 2.227 38.25 2.251 ;
     RECT  49.068 2.227 51.105 2.251 ;
     RECT  11.268 2.191 11.286 2.263 ;
     RECT  12.024 2.227 12.042 2.263 ;
     RECT  13.215 2.143 13.305 2.263 ;
     RECT  20.34 2.203 20.358 2.263 ;
     RECT  21.42 2.227 22.122 2.263 ;
     RECT  23.688 2.227 24.105 2.263 ;
     RECT  34.815 2.143 34.905 2.263 ;
     RECT  45.468 2.143 45.705 2.263 ;
     RECT  48.996 2.251 51.105 2.263 ;
     RECT  64.62 2.227 64.638 2.263 ;
     RECT  67.215 2.143 67.305 2.263 ;
     RECT  68.616 2.227 68.634 2.263 ;
     RECT  64.62 2.263 64.998 2.293 ;
     RECT  18.615 2.143 18.705 2.299 ;
     RECT  20.34 2.263 22.122 2.299 ;
     RECT  22.86 2.227 22.878 2.299 ;
     RECT  26.856 2.251 26.874 2.299 ;
     RECT  27.9 2.263 27.918 2.299 ;
     RECT  28.872 2.227 29.505 2.299 ;
     RECT  32.544 2.251 32.562 2.299 ;
     RECT  34.815 2.263 35.37 2.299 ;
     RECT  45.468 2.263 45.774 2.299 ;
     RECT  59.112 2.263 59.13 2.299 ;
     RECT  64.476 2.293 64.998 2.299 ;
     RECT  17.028 2.263 17.046 2.333 ;
     RECT  5.76 2.191 6.858 2.335 ;
     RECT  7.815 2.251 8.874 2.335 ;
     RECT  41.04 2.227 41.562 2.335 ;
     RECT  43.38 2.263 44.046 2.335 ;
     RECT  66.744 2.263 67.305 2.335 ;
     RECT  9.9 2.251 10.422 2.347 ;
     RECT  11.268 2.263 13.374 2.347 ;
     RECT  59.112 2.299 59.454 2.347 ;
     RECT  5.76 2.335 8.874 2.371 ;
     RECT  9.9 2.347 13.374 2.371 ;
     RECT  14.112 2.299 14.13 2.371 ;
     RECT  17.136 2.347 17.262 2.371 ;
     RECT  18 2.299 18.705 2.371 ;
     RECT  23.688 2.263 24.174 2.371 ;
     RECT  24.984 2.227 25.686 2.371 ;
     RECT  27.9 2.299 28.098 2.371 ;
     RECT  28.872 2.299 29.862 2.371 ;
     RECT  33.732 2.227 33.75 2.371 ;
     RECT  34.815 2.299 35.55 2.371 ;
     RECT  37.656 2.251 38.538 2.371 ;
     RECT  39.924 2.143 40.305 2.371 ;
     RECT  43.38 2.335 44.154 2.371 ;
     RECT  45.468 2.299 46.062 2.371 ;
     RECT  59.112 2.347 59.49 2.371 ;
     RECT  61.815 2.143 61.905 2.371 ;
     RECT  68.616 2.263 69.102 2.371 ;
     RECT  2.415 2.143 2.505 2.413 ;
     RECT  5.76 2.371 13.374 2.413 ;
     RECT  14.112 2.371 14.31 2.413 ;
     RECT  17.136 2.371 18.705 2.413 ;
     RECT  39.492 2.371 40.305 2.413 ;
     RECT  41.04 2.335 42.066 2.413 ;
     RECT  48.888 2.263 51.105 2.413 ;
     RECT  56.415 2.143 56.505 2.413 ;
     RECT  66.708 2.335 67.305 2.413 ;
     RECT  72.615 2.143 72.705 2.413 ;
     RECT  26.856 2.299 27.126 2.461 ;
     RECT  27.9 2.371 30.438 2.461 ;
     RECT  31.752 2.371 31.77 2.461 ;
     RECT  32.544 2.299 32.778 2.461 ;
     RECT  37.296 2.371 38.754 2.461 ;
     RECT  39.492 2.413 42.066 2.461 ;
     RECT  47.736 2.335 47.754 2.461 ;
     RECT  48.888 2.413 51.297 2.461 ;
     RECT  52.668 2.299 52.686 2.461 ;
     RECT  26.856 2.461 30.438 2.491 ;
     RECT  58.716 2.371 59.49 2.491 ;
     RECT  26.856 2.491 30.618 2.497 ;
     RECT  48.888 2.461 51.75 2.533 ;
     RECT  52.668 2.461 52.794 2.533 ;
     RECT  17.136 2.413 18.897 2.539 ;
     RECT  26.856 2.497 30.69 2.539 ;
     RECT  31.752 2.461 32.778 2.539 ;
     RECT  48.888 2.533 52.902 2.539 ;
     RECT  53.64 2.371 53.658 2.539 ;
     RECT  61.815 2.371 62.658 2.539 ;
     RECT  26.856 2.539 32.778 2.569 ;
     RECT  33.732 2.371 35.874 2.569 ;
     RECT  45.36 2.371 46.062 2.569 ;
     RECT  47.016 2.461 47.754 2.569 ;
     RECT  43.272 2.371 44.154 2.587 ;
     RECT  5.76 2.413 14.31 2.605 ;
     RECT  23.688 2.371 25.686 2.605 ;
     RECT  26.856 2.569 35.874 2.605 ;
     RECT  37.296 2.461 42.066 2.605 ;
     RECT  48.888 2.539 53.658 2.605 ;
     RECT  48.888 2.605 53.874 2.635 ;
     RECT  5.508 2.605 14.31 2.641 ;
     RECT  15.264 2.299 15.282 2.641 ;
     RECT  16.272 2.371 16.29 2.641 ;
     RECT  17.136 2.539 19.098 2.641 ;
     RECT  20.34 2.299 22.878 2.641 ;
     RECT  23.688 2.605 26.082 2.641 ;
     RECT  26.82 2.605 35.874 2.641 ;
     RECT  37.188 2.605 42.21 2.641 ;
     RECT  43.272 2.587 44.298 2.641 ;
     RECT  45.324 2.569 46.062 2.641 ;
     RECT  46.944 2.569 47.754 2.641 ;
     RECT  48.492 2.635 53.874 2.641 ;
     RECT  54.9 2.299 54.918 2.641 ;
     RECT  58.356 2.491 59.706 2.641 ;
     RECT  60.48 2.371 60.498 2.641 ;
     RECT  61.272 2.539 62.658 2.641 ;
     RECT  63.54 2.605 63.558 2.641 ;
     RECT  64.476 2.299 65.682 2.641 ;
     RECT  66.708 2.413 67.497 2.641 ;
     RECT  56.415 2.413 56.697 2.731 ;
     RECT  61.272 2.641 65.682 2.731 ;
     RECT  66.708 2.641 67.842 2.731 ;
     RECT  37.188 2.641 44.442 2.767 ;
     RECT  45.216 2.641 54.054 2.767 ;
     RECT  56.415 2.731 56.754 2.767 ;
     RECT  58.356 2.641 60.498 2.767 ;
     RECT  68.616 2.371 69.57 2.795 ;
     RECT  23.688 2.641 36.018 2.803 ;
     RECT  5.508 2.641 14.382 2.827 ;
     RECT  15.12 2.641 15.426 2.827 ;
     RECT  58.176 2.767 60.498 2.827 ;
     RECT  15.12 2.827 15.462 2.839 ;
     RECT  16.2 2.641 16.29 2.839 ;
     RECT  37.188 2.767 54.054 2.839 ;
     RECT  54.828 2.641 54.918 2.839 ;
     RECT  55.764 2.767 56.754 2.839 ;
     RECT  57.816 2.827 60.534 2.86 ;
     RECT  61.272 2.731 67.842 2.86 ;
     RECT  4.608 2.803 4.626 2.861 ;
     RECT  15.12 2.839 16.29 2.875 ;
     RECT  5.472 2.827 14.382 2.911 ;
     RECT  15.12 2.875 16.398 2.911 ;
     RECT  17.136 2.641 22.878 2.911 ;
     RECT  23.688 2.803 36.414 2.911 ;
     RECT  57.816 2.86 67.842 2.911 ;
     RECT  68.616 2.795 69.102 2.911 ;
     RECT  57.816 2.911 69.102 3.145 ;
     RECT  17.136 2.911 36.414 3.181 ;
     RECT  37.188 2.839 56.754 3.181 ;
     RECT  17.136 3.181 56.754 3.407 ;
     RECT  5.472 2.911 16.398 3.437 ;
     RECT  29.016 3.407 56.754 3.451 ;
     RECT  5.904 3.437 16.398 3.613 ;
     RECT  17.136 3.407 28.278 3.613 ;
     RECT  57.6 3.145 69.102 3.685 ;
     RECT  29.016 3.451 56.79 3.721 ;
     RECT  57.6 3.685 69.39 3.721 ;
     RECT  29.016 3.721 69.57 3.835 ;
     RECT  70.308 3.721 70.326 3.835 ;
     RECT  4.644 3.649 4.662 3.883 ;
     RECT  29.016 3.835 70.326 3.883 ;
     RECT  0.216 3.955 0.234 3.979 ;
     RECT  3.996 3.883 4.662 4.117 ;
     RECT  3.672 4.117 5.13 4.123 ;
     RECT  5.904 3.613 28.278 4.153 ;
     RECT  29.016 3.883 70.938 4.153 ;
     RECT  3.528 4.123 5.13 4.189 ;
     RECT  5.904 4.153 70.938 4.189 ;
     RECT  2.415 2.413 2.697 4.219 ;
     RECT  2.376 4.219 2.697 4.261 ;
     RECT  2.376 4.261 2.718 4.267 ;
     RECT  0.144 3.979 0.234 4.363 ;
     RECT  2.304 4.267 2.718 4.415 ;
     RECT  3.528 4.189 70.938 4.459 ;
     RECT  3.492 4.459 70.938 4.487 ;
     RECT  5.4 4.487 70.938 4.507 ;
     RECT  3.492 4.487 4.626 4.523 ;
     RECT  5.4 4.507 71.082 4.531 ;
     RECT  72.615 2.413 72.897 4.531 ;
     RECT  0.144 4.363 0.342 4.651 ;
     RECT  2.376 4.415 2.718 4.685 ;
     RECT  2.415 4.685 2.718 4.747 ;
     RECT  0.108 4.651 0.342 4.757 ;
     RECT  0.18 4.757 0.342 4.781 ;
     RECT  5.4 4.531 71.226 4.829 ;
     RECT  1.26 4.843 1.278 4.939 ;
     RECT  3.528 4.523 4.626 4.955 ;
     RECT  5.472 4.829 71.226 4.955 ;
     RECT  1.152 4.939 1.278 4.973 ;
     RECT  16.236 4.955 71.226 4.991 ;
     RECT  16.272 4.991 71.226 4.999 ;
     RECT  72 4.531 72.897 4.999 ;
     RECT  0.18 4.781 0.198 5.021 ;
     RECT  2.415 4.747 2.79 5.021 ;
     RECT  1.152 4.973 1.17 5.069 ;
     RECT  3.816 4.955 4.626 5.072 ;
     RECT  4.32 5.072 4.626 5.117 ;
     RECT  16.272 4.999 72.897 5.161 ;
     RECT  4.5 5.117 4.59 5.459 ;
     RECT  16.272 5.161 73.17 5.459 ;
     RECT  16.272 5.459 73.098 5.495 ;
     RECT  16.272 5.495 72.897 5.809 ;
     RECT  5.472 4.955 15.462 5.881 ;
     RECT  16.2 5.809 72.897 5.881 ;
     RECT  5.472 5.881 72.897 6.269 ;
     RECT  5.904 6.269 57.294 6.413 ;
     RECT  58.032 6.269 72.897 6.961 ;
     RECT  5.976 6.413 57.294 7.051 ;
     RECT  58.032 6.961 73.134 7.051 ;
     RECT  5.976 7.051 73.134 7.771 ;
     RECT  5.22 8.401 5.238 8.509 ;
     RECT  5.04 8.509 5.238 8.581 ;
     RECT  5.976 7.771 73.17 8.581 ;
     RECT  5.04 8.581 73.242 8.879 ;
     RECT  26.82 8.879 73.242 8.969 ;
     RECT  26.82 8.969 73.098 9.005 ;
     RECT  5.04 8.879 26.082 9.067 ;
     RECT  26.856 9.005 72.99 9.077 ;
     RECT  4.356 9.067 26.082 9.085 ;
     RECT  4.14 9.085 26.082 9.661 ;
     RECT  4.14 9.661 26.118 9.931 ;
     RECT  26.856 9.077 72.897 9.931 ;
     RECT  2.415 5.021 2.697 10.267 ;
     RECT  2.415 10.267 2.934 10.315 ;
     RECT  4.14 9.931 72.897 10.315 ;
     RECT  2.415 10.315 3.186 10.471 ;
     RECT  3.996 10.315 72.897 10.471 ;
     RECT  2.415 10.471 72.897 10.741 ;
     RECT  2.415 10.741 73.242 10.859 ;
     RECT  2.415 10.859 73.098 11.399 ;
     RECT  2.415 11.399 73.062 11.741 ;
     RECT  2.415 11.741 35.91 11.749 ;
     RECT  2.376 11.749 35.91 12.119 ;
     RECT  36.648 11.741 73.062 12.325 ;
     RECT  36.648 12.325 73.314 12.595 ;
     RECT  36.576 12.595 73.314 12.749 ;
     RECT  2.376 12.119 35.838 13.027 ;
     RECT  36.576 12.749 72.954 13.027 ;
     RECT  2.376 13.027 72.954 13.711 ;
     RECT  2.376 13.711 73.062 13.829 ;
     RECT  74.664 15.601 74.682 15.691 ;
     RECT  74.664 15.691 74.79 15.961 ;
     RECT  74.664 15.961 74.826 16.033 ;
     RECT  2.376 13.829 72.897 16.105 ;
     RECT  2.376 16.105 73.098 16.267 ;
     RECT  74.088 16.033 74.826 16.267 ;
     RECT  2.376 16.267 74.826 16.331 ;
     RECT  74.088 16.331 74.826 16.609 ;
     RECT  74.088 16.609 74.862 16.799 ;
     RECT  74.628 16.799 74.862 16.973 ;
     RECT  2.376 16.331 73.242 16.979 ;
     RECT  74.628 16.973 74.754 17.165 ;
     RECT  74.628 17.165 74.718 17.611 ;
     RECT  74.088 17.611 74.718 17.681 ;
     RECT  74.628 17.681 74.718 17.899 ;
     RECT  75.492 17.323 75.51 17.899 ;
     RECT  2.376 16.979 72.897 17.959 ;
     RECT  2.376 17.959 72.954 17.995 ;
     RECT  2.376 17.995 73.602 18.301 ;
     RECT  2.34 18.301 73.602 18.527 ;
     RECT  23.832 18.527 73.602 18.563 ;
     RECT  23.94 18.563 73.602 18.689 ;
     RECT  74.628 17.899 75.51 18.763 ;
     RECT  74.268 18.763 75.51 18.959 ;
     RECT  23.94 18.689 73.062 18.995 ;
     RECT  74.268 18.959 75.474 19.103 ;
     RECT  74.628 19.103 75.474 19.229 ;
     RECT  2.34 18.527 22.878 19.273 ;
     RECT  2.34 19.273 23.13 19.345 ;
     RECT  23.94 18.995 72.897 19.345 ;
     RECT  74.7 19.229 75.474 19.373 ;
     RECT  75.384 19.373 75.474 19.499 ;
     RECT  75.384 19.499 75.402 19.679 ;
     RECT  2.34 19.345 72.897 20.191 ;
     RECT  2.34 20.191 73.17 20.579 ;
     RECT  2.34 20.579 73.062 20.615 ;
     RECT  2.34 20.615 72.954 21.389 ;
     RECT  2.34 21.389 72.897 21.965 ;
     RECT  2.34 21.965 41.346 22.109 ;
     RECT  2.34 22.109 41.274 22.469 ;
     RECT  2.376 22.469 41.274 22.987 ;
     RECT  42.228 21.965 72.897 22.987 ;
     RECT  2.376 22.987 72.897 23.009 ;
     RECT  2.415 23.009 72.897 23.117 ;
     RECT  22.824 23.117 72.897 23.161 ;
     RECT  22.824 23.161 73.098 23.701 ;
     RECT  22.824 23.701 73.242 23.863 ;
     RECT  2.415 23.117 21.798 23.971 ;
     RECT  22.644 23.863 73.242 23.971 ;
     RECT  2.415 23.971 21.834 24.205 ;
     RECT  22.608 23.971 73.242 24.431 ;
     RECT  52.56 24.431 73.242 24.629 ;
     RECT  2.304 24.205 21.834 24.637 ;
     RECT  22.608 24.431 51.678 24.637 ;
     RECT  52.56 24.629 73.098 24.665 ;
     RECT  2.304 24.637 51.678 24.935 ;
     RECT  0.144 24.523 0.162 24.989 ;
     RECT  2.304 24.935 46.494 25.007 ;
     RECT  2.34 25.007 46.494 25.043 ;
     RECT  0.324 25.099 0.342 25.229 ;
     RECT  52.56 24.665 72.897 25.321 ;
     RECT  47.268 24.935 51.678 25.435 ;
     RECT  52.452 25.321 72.897 25.435 ;
     RECT  47.268 25.435 72.897 25.591 ;
     RECT  2.415 25.043 46.494 25.681 ;
     RECT  47.268 25.591 73.17 25.681 ;
     RECT  2.415 25.681 73.17 26.401 ;
     RECT  2.415 26.401 73.242 26.797 ;
     RECT  2.376 26.797 73.242 26.875 ;
     RECT  2.34 26.875 73.242 28.139 ;
     RECT  2.34 28.139 73.098 28.175 ;
     RECT  2.34 28.175 72.897 29.069 ;
     RECT  2.34 29.069 57.69 29.227 ;
     RECT  2.304 29.227 57.69 29.525 ;
     RECT  2.34 29.525 57.69 29.803 ;
     RECT  2.34 29.803 57.798 29.875 ;
     RECT  58.536 29.069 72.897 29.875 ;
     RECT  2.34 29.875 72.897 29.911 ;
     RECT  2.34 29.911 73.062 30.407 ;
     RECT  63.756 30.407 73.062 30.415 ;
     RECT  61.056 30.407 63.018 30.569 ;
     RECT  63.756 30.415 73.314 31.109 ;
     RECT  2.34 30.407 60.21 31.225 ;
     RECT  61.056 30.569 62.982 31.225 ;
     RECT  2.34 31.225 62.982 31.379 ;
     RECT  54.144 31.379 62.982 31.423 ;
     RECT  63.756 31.109 72.99 31.423 ;
     RECT  54.144 31.423 72.99 31.649 ;
     RECT  2.34 31.379 53.334 31.721 ;
     RECT  2.34 31.721 53.226 31.919 ;
     RECT  54.432 31.649 72.99 32.261 ;
     RECT  2.376 31.919 53.226 32.369 ;
     RECT  54.432 32.261 72.954 32.701 ;
     RECT  2.415 32.369 53.226 32.731 ;
     RECT  54.072 32.701 72.954 32.731 ;
     RECT  2.415 32.731 72.954 33.035 ;
     RECT  2.415 33.035 72.897 33.151 ;
     RECT  2.376 33.151 72.897 34.231 ;
     RECT  2.376 34.231 72.954 34.349 ;
     RECT  2.376 34.349 36.09 34.889 ;
     RECT  36.936 34.349 72.954 35.041 ;
     RECT  36.936 35.041 72.99 35.083 ;
     RECT  36.9 35.083 72.99 35.167 ;
     RECT  2.415 34.889 36.09 35.311 ;
     RECT  36.9 35.167 73.134 35.311 ;
     RECT  2.415 35.311 73.134 35.699 ;
     RECT  2.415 35.699 73.062 35.941 ;
     RECT  2.376 35.941 73.062 36.317 ;
     RECT  2.376 36.317 43.614 36.365 ;
     RECT  2.376 36.365 43.434 36.545 ;
     RECT  44.46 36.317 73.062 36.689 ;
     RECT  44.46 36.689 72.897 37.051 ;
     RECT  2.376 36.545 43.362 37.085 ;
     RECT  44.208 37.051 72.897 37.243 ;
     RECT  44.172 37.243 72.897 37.561 ;
     RECT  2.415 37.085 43.362 37.867 ;
     RECT  44.172 37.561 73.17 37.867 ;
     RECT  2.415 37.867 73.17 38.011 ;
     RECT  2.34 38.011 73.17 38.129 ;
     RECT  2.34 38.129 73.062 39.245 ;
     RECT  42.624 39.245 73.062 39.317 ;
     RECT  2.34 39.245 41.85 39.893 ;
     RECT  2.415 39.893 41.85 39.917 ;
     RECT  42.624 39.317 72.954 40.171 ;
     RECT  42.516 40.171 72.954 40.405 ;
     RECT  42.516 40.405 72.99 40.559 ;
     RECT  2.415 39.917 41.778 40.639 ;
     RECT  42.516 40.559 72.954 40.639 ;
     RECT  2.415 40.639 72.954 41.227 ;
     RECT  2.376 41.227 72.954 41.647 ;
     RECT  2.304 41.647 72.954 41.945 ;
     RECT  2.34 41.945 72.954 42.179 ;
     RECT  2.376 42.179 72.954 42.187 ;
     RECT  2.376 42.187 72.99 42.449 ;
     RECT  2.376 42.449 72.954 42.629 ;
     RECT  2.376 42.629 72.897 42.749 ;
     RECT  2.415 42.749 72.897 42.899 ;
     RECT  12.528 42.899 72.897 43.411 ;
     RECT  12.528 43.411 73.314 43.637 ;
     RECT  2.415 42.899 11.79 43.915 ;
     RECT  12.528 43.637 72.897 43.915 ;
     RECT  2.415 43.915 72.897 45.121 ;
     RECT  2.415 45.121 72.954 45.193 ;
     RECT  2.415 45.193 72.99 45.265 ;
     RECT  2.34 45.265 72.99 45.563 ;
     RECT  2.34 45.563 72.954 46.651 ;
     RECT  2.34 46.651 73.314 46.913 ;
     RECT  2.34 46.913 72.99 46.925 ;
     RECT  2.415 46.925 72.99 47.147 ;
     RECT  2.415 47.147 72.954 48.271 ;
     RECT  2.415 48.271 72.99 48.505 ;
     RECT  2.415 48.505 73.134 48.775 ;
     RECT  2.34 48.775 73.134 48.845 ;
     RECT  2.415 48.845 73.134 48.929 ;
     RECT  2.415 48.929 72.99 49.199 ;
     RECT  74.664 49.441 74.682 49.613 ;
     RECT  75.492 49.483 75.51 49.739 ;
     RECT  74.628 49.675 74.646 49.771 ;
     RECT  74.088 49.771 74.646 50.009 ;
     RECT  74.088 50.009 74.106 50.117 ;
     RECT  2.415 49.199 72.954 50.299 ;
     RECT  2.34 50.299 72.954 50.351 ;
     RECT  2.415 50.351 72.954 50.521 ;
     RECT  2.415 50.521 73.17 50.729 ;
     RECT  6.732 50.729 73.17 51.089 ;
     RECT  6.732 51.089 72.99 51.601 ;
     RECT  2.415 50.729 5.85 51.673 ;
     RECT  6.588 51.601 72.99 51.673 ;
     RECT  2.415 51.673 72.99 52.015 ;
     RECT  2.34 52.015 72.99 52.241 ;
     RECT  2.34 52.241 72.954 52.853 ;
     RECT  22.572 52.853 72.954 52.987 ;
     RECT  2.34 52.853 21.798 53.761 ;
     RECT  22.572 52.987 73.026 53.761 ;
     RECT  2.34 53.761 73.026 53.789 ;
     RECT  2.34 53.789 12.402 53.897 ;
     RECT  13.14 53.789 73.026 54.599 ;
     RECT  13.14 54.599 72.99 54.715 ;
     RECT  2.34 53.897 12.258 54.941 ;
     RECT  13.104 54.715 72.99 54.977 ;
     RECT  2.415 54.941 12.258 55.183 ;
     RECT  13.104 54.977 31.302 55.183 ;
     RECT  2.415 55.183 31.302 55.759 ;
     RECT  32.04 54.977 72.954 55.759 ;
     RECT  2.415 55.759 72.954 55.795 ;
     RECT  2.304 55.795 72.954 56.065 ;
     RECT  2.304 56.065 72.99 56.333 ;
     RECT  42.624 56.333 72.99 56.381 ;
     RECT  2.304 56.333 41.85 57.109 ;
     RECT  42.768 56.381 72.99 57.109 ;
     RECT  0.324 57.259 0.342 57.389 ;
     RECT  2.304 57.109 72.99 57.451 ;
     RECT  2.304 57.451 73.134 57.569 ;
     RECT  0.18 57.403 0.198 57.581 ;
     RECT  2.304 57.569 72.99 57.835 ;
     RECT  2.16 57.835 72.99 57.875 ;
     RECT  2.304 57.875 72.99 58.145 ;
     RECT  0.324 58.315 0.342 58.747 ;
     RECT  2.304 58.145 72.954 58.927 ;
     RECT  2.304 58.927 73.026 59.189 ;
     RECT  0.144 58.747 0.342 59.467 ;
     RECT  0.108 59.467 0.342 59.501 ;
     RECT  52.056 59.189 73.026 59.575 ;
     RECT  0.108 59.501 0.126 59.597 ;
     RECT  2.304 59.189 51.318 59.603 ;
     RECT  52.056 59.575 73.206 59.729 ;
     RECT  2.415 59.603 51.318 60.079 ;
     RECT  52.056 59.729 72.99 60.079 ;
     RECT  2.415 60.079 72.99 60.539 ;
     RECT  49.932 60.539 72.99 60.845 ;
     RECT  2.415 60.539 49.122 60.925 ;
     RECT  2.34 60.925 49.122 61.393 ;
     RECT  2.34 61.393 49.158 61.501 ;
     RECT  49.932 60.845 72.897 61.501 ;
     RECT  2.34 61.501 72.897 62.347 ;
     RECT  2.304 62.347 72.897 62.465 ;
     RECT  2.34 62.465 72.897 62.509 ;
     RECT  2.34 62.509 72.99 62.573 ;
     RECT  2.415 62.573 72.99 62.843 ;
     RECT  2.415 62.843 72.954 63.383 ;
     RECT  2.415 63.383 5.67 63.835 ;
     RECT  6.624 63.383 72.954 64.165 ;
     RECT  2.376 63.835 5.67 64.669 ;
     RECT  2.34 64.669 5.67 64.741 ;
     RECT  6.444 64.165 72.954 64.741 ;
     RECT  2.34 64.741 72.954 64.769 ;
     RECT  2.376 64.769 72.954 64.867 ;
     RECT  2.376 64.867 73.062 65.129 ;
     RECT  2.376 65.129 72.954 65.399 ;
     RECT  2.376 65.399 72.897 66.083 ;
     RECT  2.376 66.083 15.534 66.217 ;
     RECT  2.34 66.217 15.534 66.523 ;
     RECT  16.344 66.083 72.897 66.523 ;
     RECT  16.344 66.523 72.99 67.099 ;
     RECT  2.304 66.523 15.534 67.171 ;
     RECT  16.308 67.099 72.99 67.171 ;
     RECT  2.304 67.171 72.99 67.199 ;
     RECT  2.34 67.199 72.99 67.595 ;
     RECT  2.376 67.595 72.99 67.603 ;
     RECT  2.376 67.603 73.062 67.829 ;
     RECT  2.376 67.829 73.026 68.144 ;
     RECT  3.708 68.144 73.026 68.405 ;
     RECT  23.94 68.405 72.954 68.429 ;
     RECT  2.376 68.144 2.934 68.647 ;
     RECT  23.94 68.429 72.918 68.675 ;
     RECT  2.34 68.647 2.934 68.881 ;
     RECT  3.708 68.405 23.166 68.881 ;
     RECT  2.34 68.881 23.166 69.053 ;
     RECT  71.064 68.675 72.918 69.187 ;
     RECT  12.096 69.053 23.166 69.223 ;
     RECT  23.94 68.675 70.29 69.223 ;
     RECT  12.096 69.223 70.29 69.449 ;
     RECT  37.836 69.449 70.29 69.485 ;
     RECT  2.34 69.053 11.178 69.581 ;
     RECT  2.34 69.581 10.818 69.719 ;
     RECT  71.064 69.187 73.026 69.719 ;
     RECT  2.34 69.719 10.458 69.755 ;
     RECT  37.872 69.485 70.29 69.871 ;
     RECT  71.064 69.719 72.897 69.871 ;
     RECT  2.415 69.755 10.458 70.061 ;
     RECT  12.096 69.449 37.098 70.075 ;
     RECT  3.78 70.061 10.458 70.259 ;
     RECT  11.628 70.075 37.098 70.267 ;
     RECT  37.872 69.871 72.897 70.267 ;
     RECT  3.888 70.259 4.194 70.295 ;
     RECT  4.176 70.295 4.194 70.331 ;
     RECT  6.012 70.259 10.458 70.439 ;
     RECT  5.04 70.259 5.058 70.529 ;
     RECT  6.264 70.439 10.458 70.529 ;
     RECT  6.264 70.529 8.91 70.565 ;
     RECT  9.72 70.529 10.026 70.565 ;
     RECT  6.912 70.565 8.91 70.589 ;
     RECT  6.912 70.589 6.93 70.601 ;
     RECT  9.72 70.565 9.738 70.601 ;
     RECT  11.628 70.267 72.897 70.681 ;
     RECT  7.668 70.589 8.91 70.835 ;
     RECT  7.668 70.835 8.097 70.907 ;
     RECT  11.268 70.681 72.897 71.069 ;
     RECT  11.268 71.069 67.626 71.105 ;
     RECT  11.952 71.105 67.626 71.141 ;
     RECT  12.06 71.141 67.626 71.261 ;
     RECT  12.06 71.261 67.497 71.411 ;
     RECT  68.4 71.069 72.897 71.411 ;
     RECT  68.436 71.411 72.897 71.483 ;
     RECT  68.508 71.483 72.897 71.501 ;
     RECT  12.06 71.411 66.474 71.609 ;
     RECT  68.508 71.501 71.046 71.609 ;
     RECT  12.06 71.609 47.466 71.645 ;
     RECT  69.624 71.609 71.046 71.645 ;
     RECT  72.072 71.501 72.897 71.645 ;
     RECT  48.24 71.609 66.474 71.753 ;
     RECT  69.624 71.645 70.902 71.753 ;
     RECT  12.168 71.645 12.186 71.789 ;
     RECT  70.236 71.753 70.902 71.789 ;
     RECT  52.848 71.753 66.474 71.837 ;
     RECT  68.508 71.609 68.814 71.879 ;
     RECT  70.236 71.789 70.326 71.879 ;
     RECT  53.028 71.837 66.474 71.885 ;
     RECT  48.24 71.753 52.074 71.915 ;
     RECT  70.236 71.879 70.254 71.915 ;
     RECT  50.04 71.915 52.074 71.951 ;
     RECT  12.924 71.645 47.466 71.987 ;
     RECT  48.24 71.915 49.266 72.149 ;
     RECT  50.112 71.951 52.074 72.149 ;
     RECT  53.028 71.885 62.766 72.149 ;
     RECT  63.504 71.885 66.474 72.149 ;
     RECT  48.24 72.149 48.33 72.185 ;
     RECT  63.504 72.149 66.402 72.185 ;
     RECT  53.028 72.149 62.097 72.221 ;
     RECT  63.504 72.185 65.934 72.221 ;
     RECT  13.215 71.987 47.466 72.257 ;
     RECT  50.724 72.149 52.074 72.293 ;
     RECT  60.12 72.221 60.21 72.293 ;
     RECT  16.38 72.257 47.466 72.329 ;
     RECT  53.028 72.221 58.878 72.365 ;
     RECT  13.215 72.257 15.498 72.419 ;
     RECT  49.068 72.149 49.266 72.419 ;
     RECT  53.028 72.365 58.41 72.419 ;
     RECT  57.672 72.419 58.41 72.455 ;
     RECT  63.612 72.221 65.43 72.455 ;
     RECT  57.672 72.455 58.302 72.527 ;
     RECT  60.12 72.293 60.138 72.527 ;
     RECT  13.215 72.419 13.554 72.557 ;
     RECT  49.248 72.419 49.266 72.563 ;
     RECT  53.028 72.419 56.697 72.563 ;
     RECT  16.992 72.329 47.466 72.571 ;
     RECT  53.028 72.563 53.73 72.599 ;
     RECT  14.328 72.419 15.498 72.689 ;
     RECT  16.992 72.571 47.826 72.689 ;
     RECT  50.832 72.293 52.074 72.689 ;
     RECT  57.672 72.527 58.05 72.689 ;
     RECT  60.984 72.221 62.097 72.689 ;
     RECT  63.612 72.455 65.25 72.689 ;
     RECT  14.472 72.689 14.49 72.725 ;
     RECT  30.492 72.689 47.826 72.725 ;
     RECT  61.092 72.689 62.097 72.725 ;
     RECT  52.416 72.697 52.434 72.749 ;
     RECT  30.492 72.725 47.322 72.761 ;
     RECT  53.28 72.599 53.73 72.761 ;
     RECT  57.708 72.689 58.05 72.761 ;
     RECT  61.2 72.725 62.097 72.761 ;
     RECT  64.296 72.689 64.998 72.761 ;
     RECT  37.116 72.761 47.322 72.833 ;
     RECT  58.032 72.761 58.05 72.833 ;
     RECT  17.064 72.689 29.697 72.941 ;
     RECT  17.064 72.941 26.622 72.959 ;
     RECT  45.615 72.833 47.322 72.959 ;
     RECT  53.28 72.761 53.586 72.959 ;
     RECT  64.296 72.761 64.422 72.959 ;
     RECT  37.116 72.833 44.514 72.989 ;
     RECT  47.052 72.959 47.322 72.989 ;
     RECT  17.064 72.959 17.334 72.995 ;
     RECT  18.072 72.959 19.062 72.995 ;
     RECT  30.492 72.761 36.342 72.995 ;
     RECT  37.116 72.989 44.226 72.995 ;
     RECT  45.615 72.959 46.17 72.995 ;
     RECT  53.28 72.959 53.298 72.995 ;
     RECT  64.296 72.959 64.314 72.995 ;
     RECT  54.576 72.563 56.697 73.031 ;
     RECT  22.32 72.959 26.622 73.103 ;
     RECT  54.756 73.031 56.697 73.103 ;
     RECT  30.492 72.995 36.054 73.139 ;
     RECT  37.116 72.995 43.902 73.139 ;
     RECT  2.415 70.061 2.697 73.187 ;
     RECT  7.815 70.907 8.097 73.187 ;
     RECT  13.215 72.557 13.497 73.187 ;
     RECT  18.072 72.995 18.897 73.187 ;
     RECT  27.432 72.941 29.697 73.187 ;
     RECT  38.34 73.139 43.902 73.187 ;
     RECT  45.615 72.995 45.897 73.187 ;
     RECT  51.015 72.689 51.297 73.187 ;
     RECT  56.415 73.103 56.697 73.187 ;
     RECT  61.815 72.761 62.097 73.187 ;
     RECT  67.215 71.411 67.497 73.187 ;
     RECT  72.615 71.645 72.897 73.187 ;
     RECT  18.072 73.187 18.705 73.229 ;
     RECT  19.944 72.959 19.998 73.229 ;
     RECT  21.096 72.959 21.15 73.229 ;
     RECT  22.32 73.103 23.202 73.229 ;
     RECT  23.94 73.103 26.622 73.229 ;
     RECT  27.432 73.187 29.505 73.229 ;
     RECT  30.492 73.139 33.246 73.229 ;
     RECT  33.984 73.139 36.054 73.229 ;
     RECT  37.116 73.139 37.53 73.229 ;
     RECT  41.076 73.187 43.902 73.229 ;
     RECT  47.052 72.989 47.25 73.229 ;
     RECT  54.756 73.103 55.386 73.229 ;
     RECT  22.32 73.229 22.338 73.265 ;
     RECT  25.524 73.229 25.974 73.265 ;
     RECT  32.976 73.229 33.246 73.265 ;
     RECT  47.124 73.229 47.142 73.265 ;
     RECT  38.34 73.187 40.305 73.288 ;
     RECT  19.98 73.229 19.998 73.301 ;
     RECT  23.94 73.229 24.75 73.301 ;
     RECT  33.984 73.229 35.442 73.301 ;
     RECT  41.076 73.229 43.182 73.337 ;
     RECT  21.132 73.229 21.15 73.373 ;
     RECT  25.524 73.265 25.542 73.373 ;
     RECT  27.972 73.229 29.505 73.373 ;
     RECT  33.228 73.265 33.246 73.373 ;
     RECT  34.815 73.301 35.442 73.373 ;
     RECT  41.436 73.337 43.182 73.373 ;
     RECT  27.972 73.373 28.674 73.379 ;
     RECT  30.492 73.229 30.51 73.379 ;
     RECT  31.572 73.229 31.59 73.379 ;
     RECT  23.94 73.301 24.105 73.409 ;
     RECT  27.972 73.379 27.99 73.409 ;
     RECT  38.34 73.288 38.358 73.409 ;
     RECT  39.168 73.288 40.305 73.409 ;
     RECT  42.732 73.373 43.182 73.409 ;
     RECT  2.415 73.187 2.505 73.457 ;
     RECT  7.815 73.187 7.905 73.457 ;
     RECT  13.215 73.187 13.305 73.457 ;
     RECT  18.615 73.229 18.705 73.457 ;
     RECT  24.015 73.409 24.105 73.457 ;
     RECT  29.415 73.373 29.505 73.457 ;
     RECT  34.815 73.373 34.905 73.457 ;
     RECT  40.215 73.409 40.305 73.457 ;
     RECT  45.615 73.187 45.705 73.457 ;
     RECT  51.015 73.187 51.105 73.457 ;
     RECT  56.415 73.187 56.505 73.457 ;
     RECT  61.815 73.187 61.905 73.457 ;
     RECT  67.215 73.187 67.305 73.457 ;
     RECT  72.615 73.187 72.705 73.457 ;
     RECT  34.056 73.301 34.074 73.499 ;
     RECT  41.436 73.373 41.454 73.499 ;
    LAYER M4 ;
     RECT  0.06 56.496 0.097 59.496 ;
     RECT  0.06 24.24 0.133 25.224 ;
     RECT  0.06 3.984 0.136 4.968 ;
     RECT  0.136 3.984 0.173 5.016 ;
     RECT  0.173 4.08 0.245 5.016 ;
     RECT  0.245 4.128 1.141 5.016 ;
     RECT  1.141 4.128 2.408 5.064 ;
     RECT  2.365 16.08 2.408 16.104 ;
     RECT  2.365 18.192 2.408 18.216 ;
     RECT  2.365 22.464 2.408 22.488 ;
     RECT  0.133 24.24 2.408 25.32 ;
     RECT  2.293 26.304 2.408 26.904 ;
     RECT  2.365 28.464 2.408 28.488 ;
     RECT  2.365 30.96 2.408 30.984 ;
     RECT  2.365 34.752 2.408 34.776 ;
     RECT  2.365 36 2.408 36.024 ;
     RECT  2.365 41.232 2.408 41.256 ;
     RECT  2.365 42.72 2.408 42.744 ;
     RECT  2.293 46.896 2.408 46.92 ;
     RECT  2.293 48.816 2.408 48.84 ;
     RECT  2.285 50.304 2.408 50.328 ;
     RECT  2.329 53.328 2.408 53.352 ;
     RECT  2.329 54.912 2.408 54.936 ;
     RECT  0.097 56.496 2.408 59.592 ;
     RECT  0.06 62.16 2.408 62.568 ;
     RECT  2.365 63.84 2.408 63.864 ;
     RECT  2.408 2.148 2.512 73.452 ;
     RECT  2.512 2.418 2.704 73.182 ;
     RECT  2.704 23.664 2.801 38.184 ;
     RECT  2.704 10.272 2.873 16.104 ;
     RECT  2.873 10.272 2.945 15.816 ;
     RECT  2.801 24.72 2.981 38.184 ;
     RECT  2.981 24.912 3.017 38.184 ;
     RECT  2.704 48.96 3.053 48.984 ;
     RECT  2.704 19.392 3.161 20.088 ;
     RECT  2.945 12.48 3.203 15.816 ;
     RECT  2.704 62.016 3.269 63.96 ;
     RECT  2.704 42.72 3.299 45.384 ;
     RECT  2.945 10.272 3.395 11.448 ;
     RECT  3.269 62.256 3.443 63.96 ;
     RECT  2.704 50.736 3.485 50.76 ;
     RECT  3.203 14.784 3.521 15.816 ;
     RECT  2.704 4.128 3.557 5.064 ;
     RECT  2.704 65.76 3.58 65.784 ;
     RECT  3.017 24.912 3.587 37.032 ;
     RECT  3.587 34.944 3.635 37.032 ;
     RECT  3.587 24.912 3.665 33.912 ;
     RECT  2.704 53.328 3.665 53.352 ;
     RECT  3.443 62.256 3.665 63 ;
     RECT  3.017 38.016 3.697 38.184 ;
     RECT  2.704 39.216 3.697 41.256 ;
     RECT  2.704 56.352 3.697 60.024 ;
     RECT  2.704 22.224 3.733 22.488 ;
     RECT  2.801 23.664 3.733 23.688 ;
     RECT  3.697 38.016 3.733 41.256 ;
     RECT  3.697 56.352 3.737 60.456 ;
     RECT  3.737 56.352 3.773 59.016 ;
     RECT  2.704 18.192 3.841 18.408 ;
     RECT  2.704 46.896 3.845 46.92 ;
     RECT  3.733 38.016 3.875 41.592 ;
     RECT  3.521 14.832 3.881 15.816 ;
     RECT  3.299 42.72 3.881 45.288 ;
     RECT  2.704 67.248 3.913 68.136 ;
     RECT  3.635 35.904 3.917 37.032 ;
     RECT  3.877 48.576 3.949 48.792 ;
     RECT  3.665 24.96 3.971 33.912 ;
     RECT  3.733 22.224 3.973 23.688 ;
     RECT  3.875 39.216 3.973 41.592 ;
     RECT  3.881 42.72 3.973 43.608 ;
     RECT  3.557 4.176 3.989 5.064 ;
     RECT  3.881 14.832 4.025 15.432 ;
     RECT  3.917 35.904 4.025 35.928 ;
     RECT  3.973 21.312 4.06 23.688 ;
     RECT  4.06 21.648 4.061 23.688 ;
     RECT  3.913 50.688 4.093 50.712 ;
     RECT  3.773 56.352 4.097 58.92 ;
     RECT  3.841 17.856 4.165 18.408 ;
     RECT  2.704 54.672 4.165 55.272 ;
     RECT  3.395 10.272 4.169 11.304 ;
     RECT  4.061 22.752 4.169 23.688 ;
     RECT  4.165 17.088 4.273 18.408 ;
     RECT  3.161 19.776 4.273 20.088 ;
     RECT  3.881 44.688 4.273 45.288 ;
     RECT  3.949 48.48 4.277 48.792 ;
     RECT  3.989 4.608 4.309 5.064 ;
     RECT  4.097 56.352 4.313 58.776 ;
     RECT  4.169 10.416 4.349 11.304 ;
     RECT  3.913 67.248 4.381 68.424 ;
     RECT  4.093 50.64 4.489 50.712 ;
     RECT  3.665 62.256 4.489 62.376 ;
     RECT  4.273 17.088 4.525 20.088 ;
     RECT  4.313 57.312 4.565 58.776 ;
     RECT  3.203 12.48 4.597 13.656 ;
     RECT  4.025 14.832 4.597 15.384 ;
     RECT  4.381 66.816 4.597 68.424 ;
     RECT  4.597 66.72 4.601 68.424 ;
     RECT  3.971 31.488 4.633 33.912 ;
     RECT  3.737 60.384 4.633 60.456 ;
     RECT  4.309 4.608 4.637 5.112 ;
     RECT  3.875 38.016 4.637 38.184 ;
     RECT  4.633 31.488 4.705 34.008 ;
     RECT  4.705 31.488 4.741 34.104 ;
     RECT  4.165 54.528 4.741 55.272 ;
     RECT  4.277 48.48 4.817 48.696 ;
     RECT  4.741 31.488 4.844 34.248 ;
     RECT  4.525 16.896 4.849 20.088 ;
     RECT  4.601 66.72 4.885 66.744 ;
     RECT  4.601 67.776 4.885 68.424 ;
     RECT  2.704 70.032 4.885 70.056 ;
     RECT  4.844 31.488 4.931 34.44 ;
     RECT  3.973 39.216 4.931 43.608 ;
     RECT  4.931 42.672 4.993 43.608 ;
     RECT  4.741 53.568 4.997 55.272 ;
     RECT  4.885 65.952 4.997 66.744 ;
     RECT  3.971 24.96 5.027 30.12 ;
     RECT  4.345 9.072 5.029 9.096 ;
     RECT  4.597 12.48 5.029 15.384 ;
     RECT  4.849 16.896 5.029 20.424 ;
     RECT  4.061 21.648 5.029 21.672 ;
     RECT  5.029 12.288 5.033 15.384 ;
     RECT  4.489 62.208 5.065 62.376 ;
     RECT  4.633 60.384 5.101 60.6 ;
     RECT  5.029 8.544 5.113 9.096 ;
     RECT  4.997 54.096 5.123 55.272 ;
     RECT  4.997 65.952 5.137 65.976 ;
     RECT  5.123 54.096 5.177 55.08 ;
     RECT  3.917 37.008 5.245 37.032 ;
     RECT  4.931 31.488 5.249 34.392 ;
     RECT  5.177 54.144 5.249 55.08 ;
     RECT  5.137 65.856 5.285 65.976 ;
     RECT  5.033 14.928 5.321 15.384 ;
     RECT  4.565 57.312 5.321 58.68 ;
     RECT  5.321 14.976 5.365 15.384 ;
     RECT  5.029 16.896 5.365 21.672 ;
     RECT  5.365 14.976 5.393 21.672 ;
     RECT  5.033 12.288 5.411 13.656 ;
     RECT  5.027 24.96 5.413 29.688 ;
     RECT  5.029 35.808 5.425 35.832 ;
     RECT  4.885 67.776 5.429 70.056 ;
     RECT  4.597 2.832 5.461 2.856 ;
     RECT  5.321 57.312 5.468 58.632 ;
     RECT  5.411 12.288 5.497 13.464 ;
     RECT  5.249 31.488 5.497 34.152 ;
     RECT  5.413 24.48 5.5 29.688 ;
     RECT  5.461 2.832 5.501 3.432 ;
     RECT  5.393 15.36 5.509 21.672 ;
     RECT  5.468 57.024 5.509 58.632 ;
     RECT  5.113 9.072 5.564 9.096 ;
     RECT  4.817 48.672 5.569 48.696 ;
     RECT  4.489 50.064 5.569 50.712 ;
     RECT  5.501 3.408 5.605 3.432 ;
     RECT  4.637 4.752 5.605 5.112 ;
     RECT  5.564 9.072 5.605 9.288 ;
     RECT  4.349 10.416 5.605 10.44 ;
     RECT  5.497 12 5.605 13.464 ;
     RECT  4.705 63.84 5.609 63.864 ;
     RECT  5.101 60.384 5.653 60.936 ;
     RECT  5.065 62.208 5.653 62.472 ;
     RECT  5.653 60.384 5.677 62.472 ;
     RECT  4.931 39.216 5.681 41.592 ;
     RECT  5.245 37.008 5.701 37.08 ;
     RECT  4.637 38.16 5.701 38.184 ;
     RECT  4.273 44.688 5.713 46.056 ;
     RECT  5.509 15.36 5.717 21.768 ;
     RECT  5.677 60.096 5.74 62.472 ;
     RECT  5.74 62.208 5.789 62.472 ;
     RECT  5.717 15.36 5.825 19.032 ;
     RECT  5.569 48.672 5.825 50.712 ;
     RECT  5.749 1.728 5.843 1.752 ;
     RECT  4.169 22.752 5.857 22.824 ;
     RECT  5.605 9.072 5.893 10.44 ;
     RECT  5.605 11.472 5.893 13.464 ;
     RECT  5.425 35.808 5.893 35.88 ;
     RECT  5.717 20.16 5.929 21.768 ;
     RECT  5.857 22.752 5.929 23.16 ;
     RECT  5.893 35.568 6.073 35.88 ;
     RECT  5.701 37.008 6.073 38.184 ;
     RECT  5.74 60.096 6.073 60.936 ;
     RECT  4.993 42.672 6.181 43.656 ;
     RECT  5.713 44.688 6.181 46.872 ;
     RECT  6.145 7.92 6.217 7.944 ;
     RECT  5.893 9.072 6.217 13.464 ;
     RECT  5.429 69.168 6.253 70.056 ;
     RECT  6.181 42.672 6.277 46.872 ;
     RECT  5.497 31.344 6.289 34.152 ;
     RECT  6.073 35.568 6.289 38.184 ;
     RECT  5.5 24.768 6.293 29.688 ;
     RECT  6.253 69.168 6.293 70.536 ;
     RECT  5.249 54.144 6.325 54.744 ;
     RECT  5.509 56.4 6.325 58.632 ;
     RECT  6.289 6.288 6.373 6.312 ;
     RECT  6.325 54.144 6.397 58.632 ;
     RECT  6.073 59.76 6.397 60.936 ;
     RECT  6.397 54.144 6.481 60.936 ;
     RECT  5.681 39.264 6.541 41.592 ;
     RECT  6.277 42.624 6.541 46.872 ;
     RECT  6.476 2.352 6.563 2.376 ;
     RECT  6.217 7.92 6.581 13.464 ;
     RECT  6.541 39.264 6.581 46.872 ;
     RECT  5.825 48.672 6.649 48.744 ;
     RECT  6.481 54.144 6.649 58.296 ;
     RECT  6.293 69.168 6.649 69.24 ;
     RECT  5.605 3.408 6.685 5.112 ;
     RECT  6.581 39.264 6.725 42.792 ;
     RECT  5.789 62.208 6.793 62.232 ;
     RECT  6.581 7.968 6.829 13.464 ;
     RECT  4.489 52.56 6.829 52.584 ;
     RECT  6.505 65.28 6.833 65.304 ;
     RECT  6.685 3.408 6.86 5.16 ;
     RECT  6.373 6.288 6.86 6.84 ;
     RECT  6.289 31.344 6.893 38.184 ;
     RECT  6.293 28.704 6.901 29.688 ;
     RECT  6.893 30.72 6.901 38.184 ;
     RECT  5.825 15.984 6.937 18.984 ;
     RECT  5.929 20.16 6.937 23.16 ;
     RECT  6.901 28.704 6.949 38.184 ;
     RECT  6.725 39.264 6.949 42.744 ;
     RECT  5.965 67.68 7.004 67.704 ;
     RECT  6.649 69.072 7.004 69.24 ;
     RECT  6.937 15.984 7.009 23.16 ;
     RECT  6.829 52.56 7.009 52.728 ;
     RECT  6.481 59.568 7.045 60.936 ;
     RECT  6.793 62.16 7.045 62.232 ;
     RECT  6.901 64.656 7.045 64.92 ;
     RECT  6.649 48.48 7.261 48.744 ;
     RECT  7.009 52.464 7.261 52.728 ;
     RECT  5.825 50.352 7.333 50.712 ;
     RECT  7.261 51.792 7.333 52.728 ;
     RECT  7.045 59.568 7.333 62.232 ;
     RECT  6.293 70.512 7.333 70.536 ;
     RECT  7.045 66.336 7.369 66.36 ;
     RECT  7.009 15.024 7.405 23.16 ;
     RECT  7.004 67.68 7.477 69.24 ;
     RECT  7.333 70.512 7.477 70.584 ;
     RECT  6.293 24.768 7.585 27.624 ;
     RECT  6.949 28.704 7.585 42.744 ;
     RECT  7.333 59.568 7.585 62.328 ;
     RECT  6.86 3.408 7.621 6.84 ;
     RECT  7.405 14.928 7.621 23.16 ;
     RECT  7.585 24.768 7.621 42.744 ;
     RECT  7.477 67.68 7.657 70.584 ;
     RECT  7.621 3.024 7.808 6.84 ;
     RECT  6.829 7.968 7.808 13.896 ;
     RECT  7.621 14.928 7.808 42.744 ;
     RECT  6.581 43.872 7.808 46.872 ;
     RECT  7.261 48.48 7.808 48.792 ;
     RECT  7.333 50.016 7.808 52.728 ;
     RECT  6.649 54.096 7.808 58.296 ;
     RECT  7.585 59.568 7.808 63.096 ;
     RECT  7.045 64.368 7.808 64.92 ;
     RECT  7.369 66.336 7.808 66.6 ;
     RECT  7.657 67.68 7.808 70.632 ;
     RECT  7.808 2.148 7.912 73.452 ;
     RECT  7.912 2.256 8.104 73.182 ;
     RECT  8.104 66.336 8.165 66.6 ;
     RECT  8.104 16.56 8.243 42.84 ;
     RECT  8.104 55.488 8.243 63.288 ;
     RECT  8.104 52.56 8.381 54.12 ;
     RECT  8.104 64.656 8.381 64.68 ;
     RECT  8.243 21.024 8.489 42.84 ;
     RECT  8.243 55.488 8.489 61.656 ;
     RECT  8.489 21.024 8.525 26.712 ;
     RECT  8.104 6.816 8.741 15.336 ;
     RECT  8.489 27.888 8.741 42.84 ;
     RECT  8.741 30.624 8.813 42.84 ;
     RECT  8.104 68.064 9.097 69.864 ;
     RECT  8.489 55.488 9.107 58.104 ;
     RECT  9.107 55.488 9.109 57.432 ;
     RECT  8.243 63.072 9.137 63.288 ;
     RECT  8.381 54.096 9.155 54.12 ;
     RECT  8.104 50.016 9.157 51.384 ;
     RECT  8.165 66.336 9.173 66.36 ;
     RECT  9.109 55.296 9.196 57.432 ;
     RECT  8.813 31.248 9.205 42.84 ;
     RECT  8.104 43.872 9.205 46.056 ;
     RECT  8.489 59.76 9.209 61.656 ;
     RECT  9.196 55.392 9.217 57.432 ;
     RECT  8.741 12.816 9.241 15.336 ;
     RECT  8.243 16.56 9.241 19.896 ;
     RECT  9.157 49.92 9.244 51.384 ;
     RECT  8.104 48.192 9.277 48.216 ;
     RECT  8.741 6.816 9.281 11.784 ;
     RECT  8.525 21.12 9.281 26.712 ;
     RECT  8.741 27.888 9.281 29.64 ;
     RECT  9.137 63.264 9.389 63.288 ;
     RECT  9.241 12.816 9.421 19.896 ;
     RECT  9.281 27.888 9.497 29.496 ;
     RECT  8.381 52.56 9.529 52.728 ;
     RECT  9.205 31.248 9.533 46.056 ;
     RECT  9.244 50.112 9.565 51.384 ;
     RECT  9.529 52.56 9.565 53.064 ;
     RECT  9.097 67.776 9.569 69.864 ;
     RECT  9.209 60.288 9.637 61.656 ;
     RECT  8.104 2.256 9.677 5.688 ;
     RECT  9.281 7.104 9.745 11.784 ;
     RECT  9.421 12.816 9.745 20.136 ;
     RECT  9.277 48.192 9.749 48.456 ;
     RECT  9.533 31.248 9.772 45.192 ;
     RECT  9.772 31.248 9.853 41.448 ;
     RECT  9.569 67.776 9.853 69.192 ;
     RECT  9.281 24.336 9.925 26.712 ;
     RECT  9.677 2.256 9.929 5.016 ;
     RECT  9.853 30.576 10.001 41.448 ;
     RECT  9.217 55.488 10.069 57.432 ;
     RECT  9.745 7.104 10.252 20.136 ;
     RECT  9.565 50.112 10.289 53.064 ;
     RECT  9.749 48.432 10.321 48.456 ;
     RECT  9.853 67.104 10.321 69.192 ;
     RECT  9.637 60.288 10.361 61.896 ;
     RECT  9.493 64.752 10.429 64.776 ;
     RECT  10.069 55.488 10.433 58.152 ;
     RECT  9.281 21.12 10.469 23.352 ;
     RECT  10.429 64.416 10.501 64.776 ;
     RECT  10.501 63.792 10.505 64.776 ;
     RECT  9.925 24.336 10.577 26.808 ;
     RECT  10.505 63.792 10.585 64.728 ;
     RECT  9.929 2.352 10.649 5.016 ;
     RECT  10.649 3.936 10.681 5.016 ;
     RECT  10.252 7.2 10.681 20.136 ;
     RECT  10.469 21.12 10.681 22.824 ;
     RECT  10.681 7.2 10.685 22.824 ;
     RECT  10.685 10.08 10.693 22.824 ;
     RECT  10.685 7.2 10.721 9.096 ;
     RECT  10.289 51.984 10.753 53.064 ;
     RECT  10.289 50.352 10.757 51 ;
     RECT  9.497 28.608 10.789 29.496 ;
     RECT  10.001 30.576 10.789 39.288 ;
     RECT  10.577 24.336 10.825 24.36 ;
     RECT  10.001 40.32 10.825 41.448 ;
     RECT  9.772 42.768 10.825 45.192 ;
     RECT  10.693 10.08 10.829 21.768 ;
     RECT  10.789 28.608 10.835 39.288 ;
     RECT  10.825 24.192 10.865 24.36 ;
     RECT  10.585 64.416 10.865 64.728 ;
     RECT  10.649 2.352 10.901 2.376 ;
     RECT  10.757 50.352 10.937 50.904 ;
     RECT  10.865 64.704 10.973 64.728 ;
     RECT  10.835 33.072 11.009 39.288 ;
     RECT  11.009 33.072 11.075 36.6 ;
     RECT  10.321 48.432 11.081 49.176 ;
     RECT  10.321 66.624 11.149 69.192 ;
     RECT  10.835 28.608 11.173 32.088 ;
     RECT  10.681 3.936 11.221 5.064 ;
     RECT  10.721 7.2 11.221 9.048 ;
     RECT  9.637 46.8 11.261 46.824 ;
     RECT  11.221 3.936 11.305 5.4 ;
     RECT  11.149 66.624 11.315 69.576 ;
     RECT  11.173 28.32 11.329 32.088 ;
     RECT  10.433 55.488 11.401 57.432 ;
     RECT  11.329 28.176 11.461 32.088 ;
     RECT  11.221 6.864 11.473 9.048 ;
     RECT  10.937 50.352 11.477 50.712 ;
     RECT  10.693 22.8 11.545 22.824 ;
     RECT  10.865 24.192 11.545 24.216 ;
     RECT  10.361 60.528 11.545 61.896 ;
     RECT  11.545 60.528 11.581 62.712 ;
     RECT  11.305 3.936 11.617 5.064 ;
     RECT  11.461 28.128 11.617 32.088 ;
     RECT  11.617 27.888 11.621 32.088 ;
     RECT  11.315 66.624 11.621 67.416 ;
     RECT  11.557 65.52 11.644 65.544 ;
     RECT  11.401 55.488 11.765 58.104 ;
     RECT  11.329 70.704 11.797 70.728 ;
     RECT  10.577 25.392 11.833 26.808 ;
     RECT  11.621 27.888 11.833 31.944 ;
     RECT  11.315 68.4 11.833 69.576 ;
     RECT  11.797 70.608 11.833 70.728 ;
     RECT  10.829 18.816 11.941 21.768 ;
     RECT  11.545 22.8 11.941 24.216 ;
     RECT  11.617 3.36 12.035 5.064 ;
     RECT  11.075 33.072 12.049 34.776 ;
     RECT  11.075 36.096 12.049 36.6 ;
     RECT  11.989 2.256 12.076 2.28 ;
     RECT  10.829 10.08 12.085 17.736 ;
     RECT  11.941 18.816 12.085 24.216 ;
     RECT  11.833 68.4 12.161 70.728 ;
     RECT  12.013 47.376 12.181 47.4 ;
     RECT  11.081 48.432 12.181 48.984 ;
     RECT  12.161 69.984 12.193 70.728 ;
     RECT  11.473 6.816 12.229 9.048 ;
     RECT  10.753 51.984 12.229 53.352 ;
     RECT  12.049 33.072 12.265 36.6 ;
     RECT  11.009 37.584 12.265 39.288 ;
     RECT  12.181 47.376 12.265 48.984 ;
     RECT  12.265 33.072 12.284 39.288 ;
     RECT  11.621 67.392 12.325 67.416 ;
     RECT  12.161 68.4 12.325 69 ;
     RECT  11.581 59.76 12.373 62.712 ;
     RECT  12.035 3.84 12.409 5.064 ;
     RECT  12.301 64.32 12.421 64.344 ;
     RECT  12.265 47.376 12.445 49.368 ;
     RECT  11.477 50.352 12.445 50.376 ;
     RECT  12.445 47.376 12.476 50.376 ;
     RECT  10.825 40.32 12.517 45.192 ;
     RECT  12.476 46.752 12.517 50.376 ;
     RECT  12.409 3.84 12.545 5.112 ;
     RECT  12.229 6.576 12.545 9.048 ;
     RECT  12.545 3.84 12.553 9.048 ;
     RECT  12.085 10.08 12.553 24.216 ;
     RECT  12.284 32.928 12.553 39.288 ;
     RECT  12.517 40.32 12.553 50.376 ;
     RECT  12.373 59.76 12.625 63.288 ;
     RECT  12.421 64.32 12.625 65.016 ;
     RECT  12.625 59.76 12.86 65.016 ;
     RECT  12.86 59.76 12.901 65.544 ;
     RECT  12.229 51.984 12.913 53.592 ;
     RECT  12.325 67.392 12.949 69 ;
     RECT  12.553 3.84 13.093 24.216 ;
     RECT  11.833 25.392 13.093 31.944 ;
     RECT  12.553 32.928 13.093 50.376 ;
     RECT  11.765 55.488 13.093 57.432 ;
     RECT  13.057 2.784 13.208 2.808 ;
     RECT  13.093 3.84 13.208 50.376 ;
     RECT  12.913 51.36 13.208 53.592 ;
     RECT  13.093 55.488 13.208 57.96 ;
     RECT  12.901 59.76 13.208 66.264 ;
     RECT  12.949 67.248 13.208 69 ;
     RECT  12.193 69.984 13.208 71.496 ;
     RECT  13.208 2.148 13.312 73.452 ;
     RECT  13.312 2.418 13.504 73.182 ;
     RECT  13.504 14.688 13.601 17.064 ;
     RECT  13.504 2.784 13.673 13.56 ;
     RECT  13.504 20.304 13.715 34.152 ;
     RECT  13.504 70.704 14.285 71.496 ;
     RECT  13.715 33.12 14.321 34.152 ;
     RECT  13.504 59.232 14.483 60.648 ;
     RECT  13.673 3.936 14.497 13.56 ;
     RECT  13.715 20.304 14.501 31.992 ;
     RECT  14.501 23.328 14.531 31.992 ;
     RECT  13.504 66.24 14.533 69 ;
     RECT  13.504 72.528 14.717 72.552 ;
     RECT  13.673 2.784 14.785 2.856 ;
     RECT  14.497 3.936 14.785 13.608 ;
     RECT  14.533 66.24 14.789 69.864 ;
     RECT  14.531 25.056 14.797 31.992 ;
     RECT  13.504 18.192 14.857 19.08 ;
     RECT  14.501 20.304 14.857 22.152 ;
     RECT  14.321 33.12 14.861 33.144 ;
     RECT  13.601 14.784 14.893 17.064 ;
     RECT  14.797 25.44 14.917 31.992 ;
     RECT  14.321 34.128 14.917 34.152 ;
     RECT  13.504 35.136 14.917 57.72 ;
     RECT  14.917 34.128 14.929 57.72 ;
     RECT  13.504 62.448 15.001 65.016 ;
     RECT  14.917 25.44 15.004 32.76 ;
     RECT  14.285 71.04 15.145 71.496 ;
     RECT  14.929 34.128 15.221 58.152 ;
     RECT  14.785 2.784 15.253 13.608 ;
     RECT  15.001 62.4 15.289 65.016 ;
     RECT  14.483 60.288 15.361 60.648 ;
     RECT  15.289 62.4 15.361 65.16 ;
     RECT  14.893 14.64 15.397 17.064 ;
     RECT  14.857 18.192 15.397 22.152 ;
     RECT  15.361 60.288 15.397 65.16 ;
     RECT  14.789 66.24 15.397 69.528 ;
     RECT  15.253 2.304 15.491 13.608 ;
     RECT  14.531 23.328 15.545 23.352 ;
     RECT  15.397 60.288 15.545 69.528 ;
     RECT  15.145 71.04 15.577 71.832 ;
     RECT  15.545 60.288 15.613 62.808 ;
     RECT  15.221 34.128 15.649 53.784 ;
     RECT  15.692 23.376 15.733 23.928 ;
     RECT  15.397 14.64 15.827 22.152 ;
     RECT  15.649 33.888 15.833 53.784 ;
     RECT  15.577 70.704 15.901 71.832 ;
     RECT  15.833 33.888 15.925 40.776 ;
     RECT  15.004 26.64 15.973 32.76 ;
     RECT  15.925 33.792 15.973 40.776 ;
     RECT  15.004 25.44 16.028 25.656 ;
     RECT  15.973 26.64 16.028 40.776 ;
     RECT  15.833 41.808 16.049 53.784 ;
     RECT  15.491 2.304 16.211 13.56 ;
     RECT  15.827 14.688 16.211 22.152 ;
     RECT  15.733 23.376 16.265 24.216 ;
     RECT  15.221 54.816 16.316 58.152 ;
     RECT  16.028 25.44 16.369 40.776 ;
     RECT  16.265 23.904 16.405 24.216 ;
     RECT  16.369 25.248 16.405 40.776 ;
     RECT  16.405 23.904 16.481 40.776 ;
     RECT  15.613 59.712 16.517 62.808 ;
     RECT  15.545 63.792 16.549 69.528 ;
     RECT  15.901 70.704 16.549 71.928 ;
     RECT  16.517 59.712 16.697 62.76 ;
     RECT  16.049 41.904 16.729 53.784 ;
     RECT  16.316 54.816 16.729 58.68 ;
     RECT  16.211 14.784 16.787 22.152 ;
     RECT  16.211 2.304 16.835 13.464 ;
     RECT  16.549 63.792 16.835 71.928 ;
     RECT  16.787 18.768 16.981 22.152 ;
     RECT  16.729 41.904 17.017 58.68 ;
     RECT  16.697 59.712 17.017 62.712 ;
     RECT  16.835 69.744 17.057 71.928 ;
     RECT  16.787 14.784 17.065 17.736 ;
     RECT  17.057 69.84 17.075 71.928 ;
     RECT  17.065 14.784 17.093 17.688 ;
     RECT  16.481 28.416 17.125 40.776 ;
     RECT  17.017 41.904 17.125 62.712 ;
     RECT  17.125 28.416 17.173 62.712 ;
     RECT  17.173 28.416 17.201 53.016 ;
     RECT  17.093 14.784 17.233 16.68 ;
     RECT  17.075 69.84 17.273 71.352 ;
     RECT  17.173 54.384 17.345 62.712 ;
     RECT  16.481 23.904 17.363 27.144 ;
     RECT  17.201 28.464 17.417 53.016 ;
     RECT  16.981 18.768 17.453 22.536 ;
     RECT  17.417 28.464 17.561 39.384 ;
     RECT  16.835 2.304 17.603 13.368 ;
     RECT  17.345 54.384 17.603 60.648 ;
     RECT  17.603 9.504 17.989 13.368 ;
     RECT  17.233 14.4 17.989 16.68 ;
     RECT  17.093 17.664 18.061 17.688 ;
     RECT  17.363 23.904 18.169 26.808 ;
     RECT  17.453 19.056 18.241 22.536 ;
     RECT  18.169 23.712 18.241 26.808 ;
     RECT  17.273 69.84 18.313 71.208 ;
     RECT  17.561 28.464 18.373 39 ;
     RECT  18.241 19.056 18.38 26.808 ;
     RECT  18.373 28.272 18.38 39 ;
     RECT  17.417 40.704 18.457 53.016 ;
     RECT  17.345 61.68 18.457 62.712 ;
     RECT  18.313 69.84 18.469 71.688 ;
     RECT  16.835 63.792 18.493 68.376 ;
     RECT  18.469 69.504 18.493 71.688 ;
     RECT  17.603 2.304 18.608 8.424 ;
     RECT  17.989 9.504 18.608 16.68 ;
     RECT  18.061 17.664 18.608 17.976 ;
     RECT  18.38 19.056 18.608 39 ;
     RECT  18.457 40.32 18.608 53.016 ;
     RECT  17.603 54.384 18.608 60.216 ;
     RECT  18.457 61.68 18.608 62.808 ;
     RECT  18.493 63.792 18.608 71.688 ;
     RECT  17.305 72.96 18.608 72.984 ;
     RECT  18.608 2.148 18.712 73.452 ;
     RECT  18.712 2.352 18.904 73.182 ;
     RECT  18.904 61.296 19.073 72.984 ;
     RECT  19.073 61.296 19.181 72.504 ;
     RECT  18.904 11.568 19.217 26.76 ;
     RECT  18.904 9.504 19.289 10.344 ;
     RECT  18.904 30.336 19.379 60.12 ;
     RECT  19.181 61.296 19.379 68.952 ;
     RECT  19.379 33.6 19.613 60.12 ;
     RECT  18.904 2.352 19.685 8.328 ;
     RECT  19.217 11.568 19.721 25.464 ;
     RECT  19.217 26.736 19.933 26.76 ;
     RECT  18.904 28.272 19.933 29.352 ;
     RECT  19.721 25.44 19.973 25.464 ;
     RECT  19.685 5.232 20.113 8.328 ;
     RECT  19.181 70.272 20.149 72.504 ;
     RECT  19.933 26.736 20.221 29.352 ;
     RECT  19.379 30.336 20.221 32.376 ;
     RECT  19.613 33.792 20.221 60.12 ;
     RECT  19.379 61.296 20.221 68.376 ;
     RECT  20.149 70.272 20.221 72.936 ;
     RECT  19.289 10.08 20.293 10.344 ;
     RECT  19.685 2.352 20.329 3.864 ;
     RECT  20.221 26.736 20.339 32.376 ;
     RECT  20.339 30.384 20.387 32.376 ;
     RECT  20.293 10.08 20.389 10.44 ;
     RECT  20.221 33.792 20.621 68.376 ;
     RECT  20.621 33.792 20.693 59.736 ;
     RECT  20.389 10.08 20.761 10.488 ;
     RECT  19.721 11.568 20.761 24.456 ;
     RECT  20.621 61.296 20.765 68.376 ;
     RECT  20.339 26.736 20.773 29.256 ;
     RECT  20.761 10.08 20.801 24.456 ;
     RECT  20.773 26.688 20.905 29.256 ;
     RECT  20.693 33.792 20.941 52.92 ;
     RECT  20.113 5.232 20.977 8.472 ;
     RECT  20.693 54.048 21.017 59.736 ;
     RECT  20.905 26.208 21.02 29.256 ;
     RECT  21.02 26.064 21.107 29.256 ;
     RECT  20.221 69.456 21.107 72.936 ;
     RECT  20.329 2.208 21.212 3.864 ;
     RECT  20.977 5.232 21.212 8.808 ;
     RECT  21.212 2.208 21.301 8.808 ;
     RECT  21.301 2.208 21.373 9.096 ;
     RECT  20.801 10.08 21.373 17.448 ;
     RECT  21.373 2.208 21.413 17.448 ;
     RECT  20.765 61.488 21.445 68.376 ;
     RECT  21.107 69.456 21.445 71.4 ;
     RECT  21.413 2.208 21.449 10.44 ;
     RECT  20.941 33.552 21.485 52.92 ;
     RECT  20.801 18.432 21.557 24.456 ;
     RECT  20.387 30.384 21.596 32.328 ;
     RECT  21.485 33.552 21.596 48.264 ;
     RECT  21.445 61.488 21.733 71.4 ;
     RECT  21.596 30.384 21.779 48.264 ;
     RECT  21.557 23.328 21.841 24.456 ;
     RECT  21.779 40.704 21.845 48.264 ;
     RECT  21.449 2.4 21.881 10.44 ;
     RECT  21.107 26.208 21.913 29.256 ;
     RECT  21.779 30.384 21.913 39.384 ;
     RECT  21.733 60.96 21.917 71.4 ;
     RECT  21.913 26.208 21.923 39.384 ;
     RECT  21.017 54.576 22.057 59.736 ;
     RECT  22.057 53.952 22.165 59.736 ;
     RECT  21.845 40.704 22.205 45.72 ;
     RECT  21.917 61.44 22.313 71.4 ;
     RECT  21.881 2.544 22.412 10.44 ;
     RECT  21.413 11.424 22.412 17.448 ;
     RECT  21.557 18.432 22.421 22.296 ;
     RECT  21.845 46.704 22.421 48.264 ;
     RECT  21.923 26.736 22.529 39.384 ;
     RECT  22.313 69.744 22.529 71.4 ;
     RECT  22.412 2.544 22.561 17.448 ;
     RECT  22.421 18.432 22.561 19.08 ;
     RECT  22.529 69.744 22.709 71.16 ;
     RECT  21.485 49.248 22.813 52.92 ;
     RECT  22.165 53.952 22.813 60.12 ;
     RECT  21.107 72.384 22.892 72.936 ;
     RECT  22.421 46.848 22.921 48.264 ;
     RECT  22.813 49.248 22.921 60.12 ;
     RECT  22.709 70.224 22.961 71.16 ;
     RECT  22.892 72.192 22.979 72.936 ;
     RECT  22.313 61.44 23.033 68.376 ;
     RECT  22.421 20.112 23.101 22.296 ;
     RECT  21.841 23.328 23.101 25.128 ;
     RECT  22.529 26.736 23.137 38.76 ;
     RECT  23.101 20.112 23.389 25.128 ;
     RECT  22.961 71.088 23.497 71.16 ;
     RECT  23.389 20.112 23.533 25.368 ;
     RECT  23.533 20.112 23.605 25.656 ;
     RECT  23.137 26.688 23.605 38.76 ;
     RECT  23.033 61.44 23.605 64.92 ;
     RECT  22.561 2.544 23.613 19.08 ;
     RECT  22.205 40.848 23.641 45.72 ;
     RECT  22.921 46.848 23.641 60.12 ;
     RECT  23.613 2.256 23.929 19.08 ;
     RECT  23.605 20.112 23.929 38.76 ;
     RECT  23.497 71.088 24.001 71.208 ;
     RECT  22.979 72.432 24.001 72.936 ;
     RECT  23.929 2.256 24.008 38.76 ;
     RECT  22.849 39.744 24.008 39.768 ;
     RECT  23.641 40.848 24.008 60.12 ;
     RECT  23.605 61.392 24.008 64.92 ;
     RECT  23.033 65.904 24.008 68.376 ;
     RECT  23.785 69.744 24.008 69.768 ;
     RECT  24.001 71.088 24.008 72.936 ;
     RECT  24.008 2.148 24.112 73.452 ;
     RECT  24.112 2.256 24.304 73.182 ;
     RECT  24.304 26.88 24.419 72.984 ;
     RECT  24.419 46.32 24.445 72.984 ;
     RECT  24.419 26.88 24.652 45.288 ;
     RECT  24.445 68.928 24.755 72.984 ;
     RECT  24.755 71.088 24.796 72.984 ;
     RECT  24.652 28.272 24.797 45.288 ;
     RECT  24.755 68.928 24.833 70.104 ;
     RECT  24.833 68.928 24.905 70.056 ;
     RECT  24.304 2.256 25.013 16.968 ;
     RECT  25.013 2.544 25.193 16.968 ;
     RECT  24.445 46.32 25.66 67.416 ;
     RECT  24.652 26.88 25.769 27.192 ;
     RECT  24.797 28.272 25.805 45 ;
     RECT  24.304 18 25.837 25.08 ;
     RECT  24.905 68.976 25.861 70.056 ;
     RECT  25.861 68.976 25.909 70.104 ;
     RECT  24.796 71.088 25.909 72.936 ;
     RECT  25.805 28.272 25.913 43.944 ;
     RECT  25.193 2.592 26.053 16.968 ;
     RECT  25.837 18 26.053 25.32 ;
     RECT  25.805 44.928 26.093 45 ;
     RECT  25.66 46.32 26.125 60.696 ;
     RECT  25.772 27.216 26.161 27.24 ;
     RECT  25.913 28.272 26.161 43.8 ;
     RECT  25.66 61.68 26.437 67.416 ;
     RECT  25.909 68.976 26.437 72.936 ;
     RECT  26.437 61.68 26.561 72.936 ;
     RECT  26.561 61.68 26.771 68.28 ;
     RECT  26.125 45.216 26.777 60.696 ;
     RECT  26.053 2.592 26.845 25.32 ;
     RECT  26.771 66.672 26.885 68.28 ;
     RECT  26.777 45.6 26.917 60.696 ;
     RECT  26.771 61.68 26.917 65.688 ;
     RECT  26.161 27.216 26.963 43.8 ;
     RECT  26.845 2.256 27.059 25.32 ;
     RECT  26.917 45.6 27.137 65.688 ;
     RECT  27.137 45.6 27.173 64.92 ;
     RECT  26.963 27.216 27.241 43.512 ;
     RECT  27.173 47.136 27.389 64.92 ;
     RECT  27.059 2.496 27.425 25.32 ;
     RECT  26.561 69.456 27.548 72.936 ;
     RECT  27.548 69.456 27.589 72.984 ;
     RECT  27.589 68.832 27.635 72.984 ;
     RECT  27.389 47.136 27.749 63.288 ;
     RECT  27.635 68.832 28.019 72.456 ;
     RECT  26.885 66.672 28.105 67.416 ;
     RECT  27.173 45.6 28.117 45.816 ;
     RECT  27.425 3.648 28.145 25.32 ;
     RECT  27.241 26.736 28.172 43.512 ;
     RECT  28.105 66.624 28.177 67.416 ;
     RECT  28.019 68.832 28.177 69.48 ;
     RECT  28.145 12.816 28.213 25.32 ;
     RECT  27.389 64.896 28.249 64.92 ;
     RECT  28.019 70.608 28.355 72.456 ;
     RECT  27.749 59.52 28.412 63.288 ;
     RECT  28.412 59.52 28.429 63.528 ;
     RECT  28.249 64.896 28.429 65.544 ;
     RECT  28.117 45.36 28.537 45.816 ;
     RECT  27.749 47.136 28.537 58.488 ;
     RECT  28.429 59.52 28.549 65.544 ;
     RECT  28.177 66.624 28.549 69.48 ;
     RECT  28.172 26.736 28.609 43.752 ;
     RECT  27.425 2.496 28.681 2.616 ;
     RECT  28.145 3.648 28.681 11.64 ;
     RECT  28.609 26.736 28.681 43.944 ;
     RECT  28.537 45.36 28.681 58.488 ;
     RECT  28.213 12.816 28.748 25.512 ;
     RECT  28.681 26.736 28.753 58.488 ;
     RECT  28.549 59.52 28.753 69.48 ;
     RECT  28.681 2.496 28.861 11.64 ;
     RECT  28.861 2.256 29.408 11.64 ;
     RECT  28.748 12.816 29.408 25.752 ;
     RECT  28.753 26.736 29.408 69.48 ;
     RECT  28.355 70.608 29.408 72.024 ;
     RECT  28.645 73.344 29.408 73.368 ;
     RECT  29.408 2.148 29.512 73.452 ;
     RECT  29.512 2.418 29.704 73.368 ;
     RECT  29.704 45.696 29.945 70.632 ;
     RECT  29.704 18.72 29.987 44.712 ;
     RECT  29.987 28.176 30.275 44.712 ;
     RECT  29.945 66.72 30.371 70.632 ;
     RECT  29.704 2.496 30.662 10.152 ;
     RECT  30.275 28.176 30.665 43.368 ;
     RECT  30.662 2.544 30.757 10.152 ;
     RECT  29.704 11.424 30.757 17.64 ;
     RECT  30.757 2.544 30.769 17.64 ;
     RECT  29.987 18.72 30.769 27.192 ;
     RECT  30.371 66.864 30.769 70.632 ;
     RECT  29.704 71.808 30.769 73.368 ;
     RECT  30.769 2.544 30.809 27.192 ;
     RECT  30.769 66.864 30.881 73.368 ;
     RECT  30.809 2.544 30.997 17.064 ;
     RECT  30.997 2.544 31.061 7.08 ;
     RECT  30.881 68.4 31.084 73.368 ;
     RECT  29.945 45.696 31.169 65.544 ;
     RECT  30.275 44.448 31.237 44.712 ;
     RECT  31.169 45.696 31.237 62.904 ;
     RECT  31.084 68.4 31.331 70.632 ;
     RECT  30.881 66.864 31.345 67.416 ;
     RECT  31.169 64.08 31.385 65.544 ;
     RECT  30.809 18.192 31.417 27.192 ;
     RECT  30.665 28.176 31.417 43.32 ;
     RECT  31.385 64.368 31.565 65.544 ;
     RECT  31.084 71.904 31.601 73.368 ;
     RECT  31.565 64.704 31.621 65.544 ;
     RECT  31.621 64.704 31.667 65.688 ;
     RECT  30.997 8.256 31.909 17.064 ;
     RECT  31.909 8.256 31.957 17.208 ;
     RECT  31.417 18.192 31.957 43.32 ;
     RECT  31.061 2.592 31.964 7.08 ;
     RECT  31.957 8.256 31.964 43.32 ;
     RECT  31.237 44.448 31.964 62.904 ;
     RECT  31.964 8.256 32.285 62.904 ;
     RECT  31.345 66.72 32.353 67.416 ;
     RECT  31.331 68.64 32.353 70.632 ;
     RECT  32.353 66.72 32.389 70.632 ;
     RECT  31.601 71.904 32.389 73.08 ;
     RECT  31.964 2.592 32.533 7.128 ;
     RECT  32.533 2.256 32.537 7.128 ;
     RECT  31.667 65.664 32.636 65.688 ;
     RECT  32.389 66.72 32.636 73.08 ;
     RECT  32.537 3.6 32.821 7.128 ;
     RECT  32.285 8.256 32.821 40.056 ;
     RECT  32.636 65.664 32.825 73.08 ;
     RECT  32.821 3.6 32.933 40.056 ;
     RECT  32.285 41.184 33.013 62.904 ;
     RECT  32.993 63.984 33.013 64.008 ;
     RECT  33.013 41.184 33.077 64.008 ;
     RECT  32.825 65.664 33.113 71.928 ;
     RECT  32.537 2.256 33.185 2.616 ;
     RECT  33.077 41.184 33.257 63.816 ;
     RECT  32.933 3.6 33.293 17.208 ;
     RECT  33.293 3.6 33.365 6.648 ;
     RECT  33.257 41.184 33.401 43.8 ;
     RECT  33.365 4.752 33.437 6.648 ;
     RECT  33.401 41.184 33.469 43.416 ;
     RECT  33.293 7.824 33.473 17.208 ;
     RECT  33.469 41.04 33.581 43.416 ;
     RECT  33.113 65.664 33.589 71.784 ;
     RECT  33.473 7.824 33.617 14.952 ;
     RECT  33.185 2.256 33.761 2.28 ;
     RECT  33.473 15.936 34.153 17.208 ;
     RECT  32.933 18.192 34.153 40.056 ;
     RECT  33.365 3.6 34.369 3.672 ;
     RECT  33.437 4.896 34.369 6.648 ;
     RECT  33.617 7.824 34.369 14.808 ;
     RECT  33.581 41.184 34.513 43.416 ;
     RECT  34.513 41.184 34.693 43.56 ;
     RECT  33.257 44.784 34.693 63.816 ;
     RECT  33.589 64.944 34.693 71.784 ;
     RECT  32.825 72.96 34.693 73.08 ;
     RECT  34.693 41.184 34.765 63.816 ;
     RECT  34.369 3.312 34.808 3.672 ;
     RECT  34.369 4.896 34.808 14.808 ;
     RECT  34.153 15.936 34.808 40.056 ;
     RECT  34.765 41.136 34.808 63.816 ;
     RECT  34.693 64.944 34.808 73.08 ;
     RECT  34.808 2.148 34.912 73.452 ;
     RECT  34.912 2.418 35.104 73.182 ;
     RECT  35.104 6.288 35.273 6.888 ;
     RECT  35.104 13.44 35.315 45.768 ;
     RECT  35.315 18.768 35.363 45.768 ;
     RECT  35.104 69.408 35.417 73.08 ;
     RECT  35.315 13.44 35.603 17.64 ;
     RECT  35.104 64.896 35.603 65.16 ;
     RECT  35.363 26.832 35.633 45.768 ;
     RECT  35.417 69.408 35.692 73.032 ;
     RECT  35.603 13.632 35.921 17.64 ;
     RECT  35.104 46.8 35.957 63.816 ;
     RECT  35.957 46.8 36.029 63.288 ;
     RECT  35.104 3.6 36.097 4.824 ;
     RECT  35.921 15.6 36.137 17.64 ;
     RECT  35.692 69.792 36.137 73.032 ;
     RECT  35.603 64.944 36.181 65.16 ;
     RECT  35.104 66.528 36.181 68.136 ;
     RECT  35.633 45.408 36.277 45.768 ;
     RECT  36.029 46.8 36.277 54.408 ;
     RECT  35.633 26.832 36.317 44.424 ;
     RECT  35.273 6.288 36.36 6.552 ;
     RECT  35.104 7.968 36.36 11.736 ;
     RECT  35.363 18.768 36.385 25.704 ;
     RECT  36.137 70.224 36.389 73.032 ;
     RECT  36.097 3.408 36.421 4.824 ;
     RECT  36.277 45.408 36.515 54.408 ;
     RECT  36.385 18.768 36.517 25.848 ;
     RECT  36.317 26.832 36.517 39.816 ;
     RECT  36.517 18.768 36.604 39.816 ;
     RECT  35.921 13.632 36.62 14.52 ;
     RECT  36.36 6.288 36.637 11.736 ;
     RECT  36.137 15.984 36.781 17.64 ;
     RECT  36.604 18.768 36.781 25.848 ;
     RECT  36.317 40.944 36.781 44.424 ;
     RECT  36.515 45.408 36.781 53.112 ;
     RECT  36.181 64.944 36.785 68.136 ;
     RECT  36.62 13.344 36.901 14.52 ;
     RECT  36.421 3.312 36.925 4.824 ;
     RECT  36.421 2.256 36.997 2.28 ;
     RECT  36.925 3.312 36.997 5.304 ;
     RECT  36.785 64.944 36.997 67.896 ;
     RECT  36.997 2.256 37.043 5.304 ;
     RECT  36.637 6.288 37.045 11.976 ;
     RECT  36.901 12.96 37.045 14.52 ;
     RECT  37.043 4.368 37.073 5.304 ;
     RECT  36.389 70.224 37.189 71.64 ;
     RECT  37.045 6.288 37.213 14.52 ;
     RECT  36.515 54.24 37.213 54.408 ;
     RECT  36.029 55.488 37.213 63.288 ;
     RECT  37.043 2.256 37.217 3.384 ;
     RECT  37.148 69.024 37.235 69.048 ;
     RECT  36.997 64.896 37.244 67.896 ;
     RECT  36.781 40.944 37.253 53.112 ;
     RECT  37.213 6.288 37.285 14.568 ;
     RECT  37.073 4.752 37.357 5.304 ;
     RECT  37.285 6.288 37.357 14.616 ;
     RECT  37.189 70.032 37.357 71.64 ;
     RECT  36.781 15.984 37.361 25.848 ;
     RECT  37.244 64.752 37.42 67.896 ;
     RECT  37.253 46.272 37.477 53.112 ;
     RECT  37.213 54.24 37.477 63.288 ;
     RECT  37.42 64.752 37.501 66.072 ;
     RECT  37.361 16.128 37.609 25.848 ;
     RECT  36.604 26.832 37.609 39.816 ;
     RECT  37.253 40.944 37.649 45.192 ;
     RECT  37.477 46.272 37.781 63.288 ;
     RECT  37.501 64.416 37.781 66.072 ;
     RECT  37.649 40.944 37.811 44.76 ;
     RECT  37.357 70.032 37.825 71.784 ;
     RECT  37.781 46.272 37.865 66.072 ;
     RECT  37.609 16.128 38.005 39.816 ;
     RECT  37.811 40.944 38.005 44.664 ;
     RECT  38.005 16.128 38.081 44.664 ;
     RECT  37.217 3.36 38.113 3.384 ;
     RECT  37.865 46.272 38.221 63.288 ;
     RECT  37.217 2.256 38.245 2.28 ;
     RECT  38.113 3.36 38.245 3.672 ;
     RECT  37.357 4.752 38.245 14.616 ;
     RECT  38.245 2.256 38.257 14.616 ;
     RECT  38.081 16.128 38.401 19.944 ;
     RECT  38.257 2.256 38.549 14.904 ;
     RECT  37.865 64.416 38.581 66.072 ;
     RECT  37.42 67.056 38.581 67.896 ;
     RECT  38.549 3.168 38.657 14.904 ;
     RECT  37.825 69.456 38.664 71.784 ;
     RECT  38.081 20.976 38.675 44.664 ;
     RECT  38.401 15.984 38.729 19.944 ;
     RECT  38.675 39.312 38.729 44.664 ;
     RECT  38.657 3.168 38.765 7.416 ;
     RECT  38.657 8.592 38.765 14.904 ;
     RECT  38.729 39.312 38.765 44.472 ;
     RECT  38.765 3.168 38.981 7.224 ;
     RECT  36.389 73.008 39.013 73.032 ;
     RECT  38.981 3.312 39.089 7.224 ;
     RECT  38.221 46.176 39.121 63.288 ;
     RECT  38.765 39.36 39.133 44.472 ;
     RECT  39.133 41.184 39.197 44.472 ;
     RECT  39.197 41.184 39.203 43.416 ;
     RECT  38.581 64.416 39.205 67.896 ;
     RECT  39.121 46.176 39.409 63.384 ;
     RECT  39.205 64.416 39.409 68.376 ;
     RECT  38.765 13.2 39.445 14.904 ;
     RECT  38.729 15.984 39.445 17.976 ;
     RECT  39.089 4.416 39.769 7.224 ;
     RECT  38.765 8.592 39.769 12.072 ;
     RECT  39.445 13.2 39.769 17.976 ;
     RECT  39.133 39.36 39.841 39.816 ;
     RECT  39.769 4.416 39.877 17.976 ;
     RECT  38.729 19.392 39.877 19.944 ;
     RECT  38.675 20.976 39.985 38.232 ;
     RECT  39.841 39.264 39.985 39.816 ;
     RECT  39.197 44.448 39.985 44.472 ;
     RECT  39.949 2.832 40.021 2.856 ;
     RECT  38.664 69.456 40.029 71.88 ;
     RECT  39.013 73.008 40.029 73.272 ;
     RECT  39.409 46.176 40.069 68.376 ;
     RECT  40.021 2.784 40.129 2.856 ;
     RECT  39.877 4.416 40.129 19.944 ;
     RECT  40.069 45.984 40.129 68.376 ;
     RECT  40.029 69.456 40.129 73.272 ;
     RECT  40.129 2.784 40.208 19.944 ;
     RECT  39.985 20.976 40.208 39.816 ;
     RECT  39.203 41.184 40.208 43.368 ;
     RECT  39.985 44.448 40.208 45 ;
     RECT  40.129 45.984 40.208 73.272 ;
     RECT  40.208 2.148 40.312 73.452 ;
     RECT  40.312 2.418 40.504 73.182 ;
     RECT  40.504 2.784 40.745 18.024 ;
     RECT  40.504 20.448 40.745 43.032 ;
     RECT  40.745 24.384 40.787 43.032 ;
     RECT  40.745 2.832 40.853 18.024 ;
     RECT  40.787 41.184 40.997 43.032 ;
     RECT  40.853 2.832 41.033 14.616 ;
     RECT  40.997 41.184 41.041 42.888 ;
     RECT  40.504 72.816 41.069 72.984 ;
     RECT  41.041 41.184 41.123 42.84 ;
     RECT  41.033 2.832 41.141 5.304 ;
     RECT  40.504 44.448 41.141 65.592 ;
     RECT  41.141 3.408 41.177 5.304 ;
     RECT  41.141 44.64 41.26 65.592 ;
     RECT  40.787 24.384 41.501 40.152 ;
     RECT  41.26 48.768 41.537 65.592 ;
     RECT  40.504 66.672 41.537 71.688 ;
     RECT  41.501 24.384 41.573 39.912 ;
     RECT  41.537 67.152 41.573 71.688 ;
     RECT  41.573 38.544 41.699 39.912 ;
     RECT  41.26 44.64 41.753 47.736 ;
     RECT  40.745 20.448 41.789 23.352 ;
     RECT  41.573 67.152 41.795 71.208 ;
     RECT  41.699 38.736 41.861 39.912 ;
     RECT  41.537 48.816 42.149 65.592 ;
     RECT  41.795 67.392 42.221 71.208 ;
     RECT  41.033 6.288 42.293 14.616 ;
     RECT  40.853 15.792 42.361 18.024 ;
     RECT  42.109 19.584 42.361 19.896 ;
     RECT  41.177 3.552 42.401 5.304 ;
     RECT  42.221 67.392 42.401 68.856 ;
     RECT  41.123 41.184 42.469 42.6 ;
     RECT  42.431 43.68 42.469 44.424 ;
     RECT  42.293 6.288 42.473 14.568 ;
     RECT  42.221 69.888 42.508 71.208 ;
     RECT  41.753 45.504 42.572 47.736 ;
     RECT  42.149 48.816 42.572 63.864 ;
     RECT  41.573 24.384 42.659 37.512 ;
     RECT  42.401 3.6 42.725 5.304 ;
     RECT  42.473 6.288 42.755 14.52 ;
     RECT  41.069 72.96 42.757 72.984 ;
     RECT  41.789 21.12 42.793 23.352 ;
     RECT  42.659 24.384 42.793 34.152 ;
     RECT  42.757 72.528 42.793 73.08 ;
     RECT  42.572 45.504 42.803 63.864 ;
     RECT  42.361 15.792 42.833 19.896 ;
     RECT  42.803 63.264 42.833 63.864 ;
     RECT  42.803 45.504 42.869 61.704 ;
     RECT  42.469 41.184 42.941 44.424 ;
     RECT  42.869 54.144 42.941 61.704 ;
     RECT  42.793 21.12 42.973 34.152 ;
     RECT  42.149 65.28 42.973 65.592 ;
     RECT  42.401 67.392 42.973 68.76 ;
     RECT  42.973 65.28 43.085 68.76 ;
     RECT  42.869 45.504 43.189 52.488 ;
     RECT  42.755 6.288 43.261 12.744 ;
     RECT  42.973 20.736 43.331 34.152 ;
     RECT  43.331 20.736 43.379 27.24 ;
     RECT  41.861 38.736 43.429 39.864 ;
     RECT  42.941 41.184 43.429 43.704 ;
     RECT  43.085 65.904 43.549 68.76 ;
     RECT  42.508 69.984 43.549 71.208 ;
     RECT  43.549 65.904 43.589 71.208 ;
     RECT  43.261 5.568 43.729 12.744 ;
     RECT  42.755 13.872 43.729 14.52 ;
     RECT  42.659 35.712 43.765 37.512 ;
     RECT  43.429 38.736 43.765 43.704 ;
     RECT  43.729 5.568 43.801 14.52 ;
     RECT  43.589 65.904 43.811 70.056 ;
     RECT  42.725 3.6 43.837 4.488 ;
     RECT  43.801 5.568 43.837 14.808 ;
     RECT  43.189 44.688 43.861 52.488 ;
     RECT  42.941 54.144 43.861 60.6 ;
     RECT  42.833 63.504 43.873 63.864 ;
     RECT  43.331 28.224 44.017 34.152 ;
     RECT  43.765 35.712 44.017 43.704 ;
     RECT  42.941 61.632 44.017 61.704 ;
     RECT  43.837 3.6 44.021 14.808 ;
     RECT  43.379 20.736 44.053 27.144 ;
     RECT  43.589 71.184 44.053 71.208 ;
     RECT  43.811 69.984 44.093 70.056 ;
     RECT  42.833 15.792 44.099 19.368 ;
     RECT  44.053 71.184 44.161 71.256 ;
     RECT  42.793 72.432 44.161 73.08 ;
     RECT  44.021 5.472 44.165 14.808 ;
     RECT  44.017 28.224 44.237 43.704 ;
     RECT  44.165 12.576 44.305 14.808 ;
     RECT  44.099 15.792 44.305 17.688 ;
     RECT  44.017 61.632 44.305 62.04 ;
     RECT  44.053 20.64 44.377 27.144 ;
     RECT  44.305 61.632 44.413 62.424 ;
     RECT  43.873 63.504 44.413 64.44 ;
     RECT  44.099 18.672 44.483 19.272 ;
     RECT  44.377 20.4 44.588 27.144 ;
     RECT  44.237 28.224 44.588 38.28 ;
     RECT  43.811 65.904 44.665 67.848 ;
     RECT  44.413 61.632 44.701 64.44 ;
     RECT  44.269 2.592 44.773 2.616 ;
     RECT  44.021 3.6 44.773 4.488 ;
     RECT  44.093 69.984 44.809 70.008 ;
     RECT  44.701 61.632 44.881 64.584 ;
     RECT  44.305 12.576 45.169 17.688 ;
     RECT  44.483 18.672 45.169 18.696 ;
     RECT  43.861 44.688 45.205 60.6 ;
     RECT  44.881 61.632 45.205 64.728 ;
     RECT  44.809 69.216 45.26 70.008 ;
     RECT  44.665 65.712 45.301 67.848 ;
     RECT  45.26 69.168 45.301 70.008 ;
     RECT  44.588 20.4 45.445 38.28 ;
     RECT  44.237 39.312 45.445 43.704 ;
     RECT  44.773 2.592 45.493 4.488 ;
     RECT  45.493 2.304 45.608 4.488 ;
     RECT  44.165 5.472 45.608 11.544 ;
     RECT  45.169 12.576 45.608 18.696 ;
     RECT  45.445 20.4 45.608 43.704 ;
     RECT  45.205 44.688 45.608 64.728 ;
     RECT  45.301 65.712 45.608 70.008 ;
     RECT  44.161 71.184 45.608 73.08 ;
     RECT  45.608 2.148 45.712 73.452 ;
     RECT  45.712 2.304 45.904 73.182 ;
     RECT  45.904 2.304 46.073 17.064 ;
     RECT  45.904 20.352 46.109 72.984 ;
     RECT  46.109 20.832 46.115 72.984 ;
     RECT  46.073 2.88 46.217 17.064 ;
     RECT  46.115 64.128 46.259 72.984 ;
     RECT  46.259 66.816 46.289 72.984 ;
     RECT  46.289 66.816 46.307 70.344 ;
     RECT  46.115 20.832 46.325 63.096 ;
     RECT  46.307 67.152 46.505 70.344 ;
     RECT  46.259 64.128 46.605 65.832 ;
     RECT  46.605 64.368 46.649 65.832 ;
     RECT  46.217 2.88 46.691 14.52 ;
     RECT  46.505 69.984 46.721 70.344 ;
     RECT  46.691 4.752 46.739 14.52 ;
     RECT  46.325 20.832 46.979 63 ;
     RECT  46.691 2.88 47.041 3.72 ;
     RECT  46.979 20.832 47.117 57.96 ;
     RECT  45.904 18.432 47.185 18.792 ;
     RECT  47.185 18.432 47.189 19.416 ;
     RECT  46.217 15.552 47.257 17.064 ;
     RECT  47.257 15.552 47.297 17.16 ;
     RECT  46.289 71.472 47.317 72.984 ;
     RECT  47.317 70.944 47.333 72.984 ;
     RECT  47.333 70.944 47.377 72.408 ;
     RECT  46.649 65.808 47.477 65.832 ;
     RECT  47.117 20.832 47.509 23.208 ;
     RECT  46.649 64.368 47.689 64.44 ;
     RECT  47.041 2.784 47.761 3.72 ;
     RECT  46.739 4.752 47.761 6.504 ;
     RECT  47.761 2.784 47.869 6.504 ;
     RECT  46.739 7.584 47.869 14.52 ;
     RECT  46.979 58.944 47.905 63 ;
     RECT  47.689 64.032 47.905 64.44 ;
     RECT  47.377 70.944 47.909 72.168 ;
     RECT  47.117 24.192 48.049 57.96 ;
     RECT  47.905 58.944 48.049 64.44 ;
     RECT  47.509 20.544 48.085 23.208 ;
     RECT  48.049 24.192 48.085 64.44 ;
     RECT  48.085 20.544 48.121 64.488 ;
     RECT  48.121 20.544 48.197 65.4 ;
     RECT  47.869 2.784 48.301 14.52 ;
     RECT  47.297 15.84 48.301 17.16 ;
     RECT  47.189 19.392 48.301 19.416 ;
     RECT  47.909 71.808 48.341 72.168 ;
     RECT  48.197 44.4 48.449 65.4 ;
     RECT  48.301 2.784 48.469 17.16 ;
     RECT  47.257 18.144 48.469 18.168 ;
     RECT  48.469 2.784 48.481 18.168 ;
     RECT  48.301 19.2 48.481 19.416 ;
     RECT  48.481 2.64 48.521 19.416 ;
     RECT  48.449 44.4 48.557 65.16 ;
     RECT  48.521 3.696 48.565 19.416 ;
     RECT  48.197 20.544 48.565 43.176 ;
     RECT  46.505 67.152 48.62 68.952 ;
     RECT  48.62 66.864 48.733 68.952 ;
     RECT  48.733 66.336 48.881 68.952 ;
     RECT  48.557 63.264 48.917 65.16 ;
     RECT  48.565 3.696 48.953 43.176 ;
     RECT  48.521 2.64 48.985 2.664 ;
     RECT  48.953 3.696 48.988 19.416 ;
     RECT  48.988 3.696 49.133 6.456 ;
     RECT  48.341 71.808 49.201 72.024 ;
     RECT  47.605 69.936 49.237 69.96 ;
     RECT  49.237 69.744 49.273 69.96 ;
     RECT  48.985 2.256 49.529 2.664 ;
     RECT  48.917 63.792 49.669 65.16 ;
     RECT  48.881 66.336 49.669 68.712 ;
     RECT  49.273 69.744 49.669 70.632 ;
     RECT  49.201 71.616 49.669 72.024 ;
     RECT  49.133 3.84 49.673 6.456 ;
     RECT  48.953 20.544 49.715 43.176 ;
     RECT  48.557 44.4 49.741 61.992 ;
     RECT  49.669 69.744 49.753 72.024 ;
     RECT  49.715 20.592 49.849 43.176 ;
     RECT  49.741 44.4 49.849 62.712 ;
     RECT  49.669 63.792 49.849 68.712 ;
     RECT  49.753 69.744 49.849 70.632 ;
     RECT  49.849 20.592 49.909 62.712 ;
     RECT  49.849 63.792 49.909 70.632 ;
     RECT  48.988 7.44 49.957 19.416 ;
     RECT  49.957 7.392 50.245 19.416 ;
     RECT  49.673 3.84 50.749 6.408 ;
     RECT  50.245 7.392 50.749 19.56 ;
     RECT  49.909 20.592 50.749 70.632 ;
     RECT  50.749 3.84 50.785 70.632 ;
     RECT  49.529 2.352 51.008 2.424 ;
     RECT  50.785 3.696 51.008 70.632 ;
     RECT  49.753 71.616 51.008 72.024 ;
     RECT  51.008 2.148 51.112 73.452 ;
     RECT  51.112 2.418 51.304 73.182 ;
     RECT  51.304 20.64 51.545 66.36 ;
     RECT  51.304 2.928 51.725 8.04 ;
     RECT  51.725 4.512 51.905 8.04 ;
     RECT  51.905 7.392 52.265 7.992 ;
     RECT  51.905 4.512 52.301 6.408 ;
     RECT  51.725 2.928 52.405 2.952 ;
     RECT  51.304 9.6 52.405 19.656 ;
     RECT  51.545 20.64 52.405 23.88 ;
     RECT  52.301 4.512 52.409 6.36 ;
     RECT  51.304 68.64 52.445 72.744 ;
     RECT  52.405 9.6 52.451 23.88 ;
     RECT  52.451 9.6 52.481 11.64 ;
     RECT  52.451 12.72 52.643 23.88 ;
     RECT  52.643 18.432 52.691 23.88 ;
     RECT  52.691 21.456 52.693 23.88 ;
     RECT  52.445 68.64 52.697 72.024 ;
     RECT  51.304 67.344 52.729 67.608 ;
     RECT  52.697 68.64 52.729 69 ;
     RECT  51.545 25.344 52.765 66.36 ;
     RECT  52.729 67.344 52.765 69 ;
     RECT  52.693 21.456 53.017 24.216 ;
     RECT  52.765 25.344 53.017 69 ;
     RECT  53.017 21.456 53.057 69 ;
     RECT  52.265 7.488 53.233 7.992 ;
     RECT  52.481 9.6 53.233 11.544 ;
     RECT  52.405 2.544 53.413 2.952 ;
     RECT  52.409 4.512 53.413 6.312 ;
     RECT  52.643 12.72 53.449 17.448 ;
     RECT  53.233 7.488 53.629 11.544 ;
     RECT  53.449 12.528 53.629 17.448 ;
     RECT  53.413 2.544 53.633 6.312 ;
     RECT  53.057 25.536 53.633 69 ;
     RECT  53.633 26.784 53.669 69 ;
     RECT  53.629 7.488 53.708 17.448 ;
     RECT  53.633 2.64 53.773 6.312 ;
     RECT  53.708 7.392 53.773 17.448 ;
     RECT  53.773 2.64 53.795 17.448 ;
     RECT  53.669 26.88 53.795 69 ;
     RECT  53.795 4.464 53.849 17.448 ;
     RECT  53.849 4.464 53.857 14.52 ;
     RECT  53.795 2.64 53.885 2.952 ;
     RECT  53.857 7.44 53.885 14.52 ;
     RECT  52.691 18.432 53.953 20.424 ;
     RECT  53.057 21.456 53.953 24.552 ;
     RECT  52.697 70.08 53.953 72.024 ;
     RECT  53.885 7.44 53.993 14.424 ;
     RECT  53.849 15.504 53.996 17.448 ;
     RECT  53.953 18.432 53.996 24.552 ;
     RECT  53.996 15.504 54.083 24.552 ;
     RECT  54.083 18.432 54.092 24.552 ;
     RECT  53.633 25.536 54.092 25.608 ;
     RECT  53.993 8.928 54.137 14.424 ;
     RECT  53.795 27.072 54.14 69 ;
     RECT  53.953 70.032 54.14 72.024 ;
     RECT  54.14 27.072 54.173 72.024 ;
     RECT  54.092 18.432 54.179 25.608 ;
     RECT  54.173 27.072 54.209 39.288 ;
     RECT  53.885 2.928 54.245 2.952 ;
     RECT  54.173 40.416 54.467 72.024 ;
     RECT  54.467 66.048 54.533 72.024 ;
     RECT  54.533 66.528 54.629 72.024 ;
     RECT  54.137 8.928 54.713 9.624 ;
     RECT  54.629 66.528 54.713 72.648 ;
     RECT  54.209 33.648 54.749 39.288 ;
     RECT  53.857 4.464 54.821 6.264 ;
     RECT  54.749 34.8 54.929 39.288 ;
     RECT  54.467 40.416 54.947 64.728 ;
     RECT  54.083 15.504 54.997 17.448 ;
     RECT  54.713 66.528 55.001 71.976 ;
     RECT  54.137 10.992 55.177 14.424 ;
     RECT  54.997 15.456 55.177 17.448 ;
     RECT  53.993 7.44 55.249 7.704 ;
     RECT  55.177 10.992 55.249 17.448 ;
     RECT  54.179 18.432 55.249 24.216 ;
     RECT  54.929 34.8 55.283 35.736 ;
     RECT  54.713 9.216 55.285 9.624 ;
     RECT  55.249 10.992 55.285 24.216 ;
     RECT  54.929 36.864 55.285 39.288 ;
     RECT  54.947 40.416 55.285 43.32 ;
     RECT  54.209 27.072 55.393 32.328 ;
     RECT  54.749 33.648 55.393 33.672 ;
     RECT  55.249 7.44 55.429 7.896 ;
     RECT  55.285 9.216 55.465 24.216 ;
     RECT  54.179 25.488 55.465 25.608 ;
     RECT  55.393 27.072 55.573 33.672 ;
     RECT  55.465 9.216 55.609 24.264 ;
     RECT  55.465 25.44 55.609 25.608 ;
     RECT  55.105 3.024 55.753 3.048 ;
     RECT  55.753 2.832 55.765 3.048 ;
     RECT  54.821 4.464 55.765 5.784 ;
     RECT  55.609 9.216 55.813 25.608 ;
     RECT  54.947 44.64 55.933 64.728 ;
     RECT  55.765 2.832 56.101 5.784 ;
     RECT  55.933 44.64 56.197 65.016 ;
     RECT  55.285 36.864 56.221 43.32 ;
     RECT  56.197 44.4 56.221 65.016 ;
     RECT  55.001 66.528 56.365 68.664 ;
     RECT  56.101 2.832 56.408 5.88 ;
     RECT  55.429 6.864 56.408 7.896 ;
     RECT  55.813 8.88 56.408 25.608 ;
     RECT  55.573 26.64 56.408 33.672 ;
     RECT  55.283 35.232 56.408 35.736 ;
     RECT  56.221 36.864 56.408 65.016 ;
     RECT  56.365 66.24 56.408 68.664 ;
     RECT  55.001 69.744 56.408 71.976 ;
     RECT  56.408 2.148 56.512 73.452 ;
     RECT  56.512 2.418 56.704 73.182 ;
     RECT  56.704 50.544 56.819 72.456 ;
     RECT  56.704 4.848 56.981 33.288 ;
     RECT  56.981 4.848 57.053 17.64 ;
     RECT  57.053 12.288 57.059 17.64 ;
     RECT  57.053 4.848 57.107 11.304 ;
     RECT  56.819 60.432 57.107 70.728 ;
     RECT  56.819 71.712 57.161 72.456 ;
     RECT  57.161 71.808 57.196 72.456 ;
     RECT  57.107 6.864 57.443 11.304 ;
     RECT  57.107 68.496 57.587 70.728 ;
     RECT  56.704 3.696 57.629 3.72 ;
     RECT  56.704 34.272 57.683 49.32 ;
     RECT  56.981 18.768 57.697 33.288 ;
     RECT  57.683 35.232 57.697 49.32 ;
     RECT  57.587 70.656 57.701 70.728 ;
     RECT  57.107 60.432 57.709 67.464 ;
     RECT  57.697 18.768 57.845 34.152 ;
     RECT  57.107 4.848 57.96 5.832 ;
     RECT  57.587 68.496 57.971 69.576 ;
     RECT  57.059 12.768 57.973 17.64 ;
     RECT  57.845 18.768 57.973 24.648 ;
     RECT  56.819 50.544 58.025 59.304 ;
     RECT  57.443 7.92 58.057 11.304 ;
     RECT  57.973 12.768 58.057 24.648 ;
     RECT  57.96 4.464 58.069 5.832 ;
     RECT  57.443 6.864 58.069 6.888 ;
     RECT  58.025 50.544 58.115 55.368 ;
     RECT  57.697 35.232 58.117 49.56 ;
     RECT  58.115 50.544 58.117 55.272 ;
     RECT  58.025 56.448 58.133 59.304 ;
     RECT  58.057 7.92 58.163 24.648 ;
     RECT  57.709 61.056 58.273 67.464 ;
     RECT  57.971 68.496 58.273 69 ;
     RECT  57.805 2.832 58.345 2.856 ;
     RECT  58.163 7.92 58.421 24.36 ;
     RECT  58.273 61.056 58.637 69 ;
     RECT  57.845 25.632 58.709 34.152 ;
     RECT  58.709 25.632 58.739 30.792 ;
     RECT  58.739 25.632 58.745 30.648 ;
     RECT  58.133 56.544 58.777 59.304 ;
     RECT  58.117 35.232 58.781 55.272 ;
     RECT  58.421 10.176 58.787 24.36 ;
     RECT  58.345 2.496 58.813 2.856 ;
     RECT  58.069 4.464 58.813 6.888 ;
     RECT  58.777 56.544 58.925 59.736 ;
     RECT  58.925 59.088 58.933 59.736 ;
     RECT  58.637 61.056 58.933 68.952 ;
     RECT  58.813 2.496 58.993 6.888 ;
     RECT  58.421 7.92 58.993 9.096 ;
     RECT  58.745 25.872 58.997 30.648 ;
     RECT  58.933 59.088 59.02 68.952 ;
     RECT  57.701 70.656 59.137 70.68 ;
     RECT  57.196 71.952 59.137 72.456 ;
     RECT  58.993 2.496 59.209 9.096 ;
     RECT  59.137 70.656 59.209 72.456 ;
     RECT  59.209 2.352 59.267 9.096 ;
     RECT  59.209 70.56 59.353 72.456 ;
     RECT  58.781 36.864 59.461 55.272 ;
     RECT  58.925 56.544 59.461 57.912 ;
     RECT  59.267 2.352 59.501 6.84 ;
     RECT  59.267 7.92 59.501 9.096 ;
     RECT  59.501 2.496 59.717 6.84 ;
     RECT  59.461 36.864 59.789 57.912 ;
     RECT  58.787 10.416 59.857 24.36 ;
     RECT  59.501 8.4 59.897 9.096 ;
     RECT  59.02 59.088 60.028 59.256 ;
     RECT  59.02 60.384 60.037 68.952 ;
     RECT  59.353 70.512 60.037 72.456 ;
     RECT  58.709 31.776 60.041 34.152 ;
     RECT  60.037 60.384 60.076 72.456 ;
     RECT  59.789 39.024 60.217 57.912 ;
     RECT  60.028 59.088 60.217 59.208 ;
     RECT  58.997 26.208 60.371 30.648 ;
     RECT  60.041 31.776 60.373 33.912 ;
     RECT  60.217 39.024 60.419 59.208 ;
     RECT  59.897 8.784 60.433 9.096 ;
     RECT  59.857 10.416 60.433 24.504 ;
     RECT  60.419 56.256 60.467 59.208 ;
     RECT  59.717 2.832 60.469 6.84 ;
     RECT  60.433 8.784 60.541 24.504 ;
     RECT  60.076 65.424 60.545 72.456 ;
     RECT  60.419 39.024 60.617 55.032 ;
     RECT  60.467 56.496 60.617 59.208 ;
     RECT  60.373 31.248 60.797 33.912 ;
     RECT  60.541 8.784 60.829 25.224 ;
     RECT  60.371 26.208 60.829 30.072 ;
     RECT  59.789 36.864 60.865 37.752 ;
     RECT  60.617 39.024 60.865 54.936 ;
     RECT  60.545 71.952 60.956 72.456 ;
     RECT  60.617 56.592 60.997 59.208 ;
     RECT  60.076 60.384 60.997 64.2 ;
     RECT  60.469 2.832 61.109 7.464 ;
     RECT  61.109 2.832 61.261 7.512 ;
     RECT  60.997 56.592 61.369 64.2 ;
     RECT  60.545 65.424 61.369 70.68 ;
     RECT  60.797 32.208 61.477 33.912 ;
     RECT  58.781 35.232 61.477 35.736 ;
     RECT  60.865 36.864 61.477 54.936 ;
     RECT  60.829 8.784 61.513 30.072 ;
     RECT  61.477 32.208 61.801 34.104 ;
     RECT  61.477 35.232 61.801 54.936 ;
     RECT  61.261 2.544 61.808 7.512 ;
     RECT  61.513 8.784 61.808 30.696 ;
     RECT  61.801 32.208 61.808 54.936 ;
     RECT  61.369 56.592 61.808 70.68 ;
     RECT  60.956 71.952 61.808 72.648 ;
     RECT  61.808 2.148 61.912 73.452 ;
     RECT  61.912 2.418 62.104 73.182 ;
     RECT  62.104 24.192 62.201 43.848 ;
     RECT  62.104 45.792 62.201 60.936 ;
     RECT  62.104 2.496 62.273 18.792 ;
     RECT  62.273 2.496 62.345 18.264 ;
     RECT  62.104 71.856 62.597 71.976 ;
     RECT  62.201 24.192 62.633 40.152 ;
     RECT  62.633 24.192 62.867 35.88 ;
     RECT  62.867 24.192 63.059 30.792 ;
     RECT  62.104 19.92 63.097 23.112 ;
     RECT  62.345 2.496 63.155 6.84 ;
     RECT  62.104 64.944 63.164 70.68 ;
     RECT  62.597 71.856 63.164 71.88 ;
     RECT  62.633 37.056 63.205 40.152 ;
     RECT  62.201 41.184 63.205 43.848 ;
     RECT  62.104 62.16 63.205 63.144 ;
     RECT  62.345 7.872 63.245 18.264 ;
     RECT  63.164 64.944 63.251 71.88 ;
     RECT  63.097 19.296 63.253 23.16 ;
     RECT  63.059 24.192 63.253 26.328 ;
     RECT  63.205 37.056 63.313 43.848 ;
     RECT  63.205 61.92 63.349 63.144 ;
     RECT  63.251 64.944 63.349 70.632 ;
     RECT  63.313 37.056 63.422 44.472 ;
     RECT  63.245 7.872 63.533 18.216 ;
     RECT  63.422 39.168 63.533 44.472 ;
     RECT  62.201 46.56 63.533 60.936 ;
     RECT  63.155 2.64 63.569 6.84 ;
     RECT  63.349 61.92 63.597 70.632 ;
     RECT  63.251 71.808 63.601 71.88 ;
     RECT  63.569 3.408 63.713 6.84 ;
     RECT  63.059 27.36 63.731 30.792 ;
     RECT  63.533 56.256 63.745 60.936 ;
     RECT  63.597 61.92 63.745 63.864 ;
     RECT  62.867 32.208 63.829 35.88 ;
     RECT  63.829 32.208 63.961 35.928 ;
     RECT  63.422 37.056 63.961 38.184 ;
     RECT  63.253 19.296 64.028 26.328 ;
     RECT  63.731 27.36 64.028 29.064 ;
     RECT  63.533 39.936 64.069 44.472 ;
     RECT  64.033 45.456 64.069 45.48 ;
     RECT  63.731 30.24 64.213 30.792 ;
     RECT  63.533 8.256 64.261 18.216 ;
     RECT  64.028 19.296 64.261 29.064 ;
     RECT  63.597 65.088 64.393 70.632 ;
     RECT  63.961 32.208 64.397 38.184 ;
     RECT  64.261 8.256 64.403 29.064 ;
     RECT  64.397 32.208 64.451 37.608 ;
     RECT  64.393 65.088 64.541 70.68 ;
     RECT  64.451 32.208 64.547 34.92 ;
     RECT  64.547 32.208 64.577 34.776 ;
     RECT  64.577 32.208 64.595 34.2 ;
     RECT  64.465 2.304 64.609 2.328 ;
     RECT  63.713 3.408 64.613 6.072 ;
     RECT  64.595 32.208 64.613 33.672 ;
     RECT  63.745 56.256 64.645 63.864 ;
     RECT  64.541 65.088 64.645 69.048 ;
     RECT  64.645 56.256 64.691 69.048 ;
     RECT  64.541 70.512 64.691 70.68 ;
     RECT  64.613 3.888 64.741 6.072 ;
     RECT  63.601 71.808 64.757 72.36 ;
     RECT  64.069 39.936 64.796 45.48 ;
     RECT  63.533 46.56 64.796 55.272 ;
     RECT  64.691 56.256 64.796 61.224 ;
     RECT  64.613 33.36 64.829 33.672 ;
     RECT  64.403 8.256 64.861 17.64 ;
     RECT  64.465 38.64 64.861 38.664 ;
     RECT  64.451 36.096 64.865 37.608 ;
     RECT  64.796 39.888 64.883 45.48 ;
     RECT  64.861 38.64 64.897 38.712 ;
     RECT  64.865 37.104 65.081 37.608 ;
     RECT  64.609 2.256 65.285 2.328 ;
     RECT  64.741 3.888 65.329 6.312 ;
     RECT  64.861 7.392 65.329 17.64 ;
     RECT  64.403 18.864 65.329 29.064 ;
     RECT  64.213 30.24 65.329 31.176 ;
     RECT  65.329 3.888 65.333 17.64 ;
     RECT  65.285 2.256 65.363 2.904 ;
     RECT  65.363 2.304 65.369 2.904 ;
     RECT  64.897 38.64 65.369 39.384 ;
     RECT  64.883 40.368 65.477 45.48 ;
     RECT  65.477 40.416 65.509 45.48 ;
     RECT  64.796 46.56 65.509 61.224 ;
     RECT  65.369 38.736 65.513 39.384 ;
     RECT  65.081 37.152 65.549 37.608 ;
     RECT  65.333 10.128 65.557 17.64 ;
     RECT  65.329 18.864 65.557 31.176 ;
     RECT  65.509 40.416 65.585 61.224 ;
     RECT  64.691 62.4 65.585 69.048 ;
     RECT  65.585 41.616 65.603 61.224 ;
     RECT  65.603 41.616 65.657 56.76 ;
     RECT  65.585 63.168 65.657 69.048 ;
     RECT  65.369 2.304 65.693 2.808 ;
     RECT  65.585 40.416 65.837 40.44 ;
     RECT  65.557 10.128 65.873 31.176 ;
     RECT  65.657 56.352 65.873 56.76 ;
     RECT  65.657 63.216 65.905 69.048 ;
     RECT  65.333 3.888 66.017 9.048 ;
     RECT  64.829 33.36 66.085 33.624 ;
     RECT  65.603 57.984 66.085 61.224 ;
     RECT  66.085 57.984 66.089 62.184 ;
     RECT  64.613 32.208 66.121 32.232 ;
     RECT  66.085 33.36 66.121 34.2 ;
     RECT  64.865 36.096 66.121 36.12 ;
     RECT  65.549 37.152 66.121 37.176 ;
     RECT  64.691 70.608 66.121 70.68 ;
     RECT  64.757 71.808 66.121 71.832 ;
     RECT  66.121 36.096 66.157 37.176 ;
     RECT  66.121 70.608 66.157 71.832 ;
     RECT  65.905 63.216 66.161 69.192 ;
     RECT  66.157 70.224 66.161 71.832 ;
     RECT  66.161 66.192 66.193 69.192 ;
     RECT  66.161 70.224 66.193 71.496 ;
     RECT  66.089 58.416 66.233 62.184 ;
     RECT  66.121 32.208 66.373 34.2 ;
     RECT  66.157 35.328 66.373 37.176 ;
     RECT  65.513 38.736 66.481 38.76 ;
     RECT  66.373 32.208 66.589 37.176 ;
     RECT  65.873 23.76 66.661 31.176 ;
     RECT  66.589 32.208 66.661 37.416 ;
     RECT  65.693 2.736 66.697 2.808 ;
     RECT  66.697 2.544 66.841 2.808 ;
     RECT  66.017 3.888 66.841 8.616 ;
     RECT  65.873 56.544 66.841 56.76 ;
     RECT  65.873 10.128 66.877 22.344 ;
     RECT  66.661 23.76 66.877 37.416 ;
     RECT  65.657 41.616 66.877 55.368 ;
     RECT  66.877 41.616 66.949 55.512 ;
     RECT  66.233 60.096 66.985 62.184 ;
     RECT  66.161 63.216 66.985 65.16 ;
     RECT  66.877 10.128 67.021 37.416 ;
     RECT  66.481 38.736 67.021 38.808 ;
     RECT  66.841 2.544 67.093 8.616 ;
     RECT  67.021 10.128 67.093 38.808 ;
     RECT  66.949 41.136 67.093 55.512 ;
     RECT  66.841 56.544 67.093 57.144 ;
     RECT  67.093 2.544 67.129 38.808 ;
     RECT  67.129 2.544 67.208 39.048 ;
     RECT  66.445 40.128 67.208 40.152 ;
     RECT  67.093 41.136 67.208 57.144 ;
     RECT  66.233 58.416 67.208 58.728 ;
     RECT  66.985 60.096 67.208 65.16 ;
     RECT  66.193 66.192 67.208 71.496 ;
     RECT  67.208 2.148 67.312 73.452 ;
     RECT  67.312 2.256 67.504 73.182 ;
     RECT  67.504 61.104 67.637 63.576 ;
     RECT  67.504 38.16 67.667 52.488 ;
     RECT  67.504 66.336 67.673 69.48 ;
     RECT  67.504 10.464 67.709 17.976 ;
     RECT  67.504 18.96 67.709 30.072 ;
     RECT  67.504 2.256 67.763 9.288 ;
     RECT  67.763 3.648 67.811 9.288 ;
     RECT  67.811 4.992 67.817 9.288 ;
     RECT  67.709 20.304 67.853 30.072 ;
     RECT  67.709 10.608 67.889 17.976 ;
     RECT  67.709 18.96 67.889 19.176 ;
     RECT  67.817 6.816 67.907 9.288 ;
     RECT  67.811 3.648 67.961 4.008 ;
     RECT  67.504 53.52 67.997 57.048 ;
     RECT  67.637 61.104 68.003 63 ;
     RECT  67.667 38.16 68.099 45.192 ;
     RECT  67.907 8.208 68.141 9.288 ;
     RECT  67.853 20.304 68.291 29.88 ;
     RECT  68.291 22.32 68.387 22.872 ;
     RECT  68.291 24.144 68.387 29.88 ;
     RECT  67.997 53.568 68.387 57.048 ;
     RECT  68.291 20.304 68.428 21.288 ;
     RECT  67.504 31.44 68.497 31.464 ;
     RECT  67.504 70.608 68.497 71.496 ;
     RECT  67.889 15.456 68.533 17.976 ;
     RECT  67.889 18.96 68.533 19.08 ;
     RECT  68.497 70.608 68.581 71.832 ;
     RECT  67.504 36.528 68.605 36.552 ;
     RECT  68.099 38.16 68.605 40.44 ;
     RECT  67.961 3.648 68.609 3.96 ;
     RECT  67.763 2.256 68.645 2.28 ;
     RECT  68.387 54.864 68.675 57.048 ;
     RECT  67.504 58.368 68.749 59.64 ;
     RECT  68.003 61.104 68.749 61.608 ;
     RECT  67.907 6.816 68.753 6.936 ;
     RECT  68.497 31.296 68.789 31.464 ;
     RECT  68.428 20.304 68.853 21.24 ;
     RECT  67.673 66.336 68.857 68.232 ;
     RECT  67.667 46.464 68.861 52.488 ;
     RECT  68.605 36.528 68.917 40.44 ;
     RECT  67.817 4.992 68.929 5.736 ;
     RECT  68.753 6.816 68.929 6.888 ;
     RECT  68.141 8.448 68.929 9.288 ;
     RECT  68.003 62.736 68.929 63 ;
     RECT  68.387 24.432 68.963 29.88 ;
     RECT  68.789 31.296 68.963 31.368 ;
     RECT  68.929 8.448 68.965 9.384 ;
     RECT  67.889 10.608 68.965 14.424 ;
     RECT  68.533 15.456 68.965 19.08 ;
     RECT  68.581 70.608 68.965 71.736 ;
     RECT  68.965 70.56 69.011 71.736 ;
     RECT  68.965 8.448 69.041 19.08 ;
     RECT  69.011 70.56 69.049 70.584 ;
     RECT  68.749 58.368 69.077 61.608 ;
     RECT  68.099 42 69.145 45.192 ;
     RECT  68.861 46.464 69.145 52.296 ;
     RECT  69.041 8.448 69.203 17.64 ;
     RECT  68.853 20.304 69.253 21.048 ;
     RECT  68.963 25.056 69.253 29.88 ;
     RECT  68.963 31.296 69.253 31.32 ;
     RECT  69.077 60.288 69.253 61.608 ;
     RECT  68.929 62.736 69.253 63.864 ;
     RECT  67.504 34.608 69.289 35.352 ;
     RECT  68.917 36.432 69.289 40.44 ;
     RECT  68.609 3.696 69.301 3.96 ;
     RECT  68.929 4.992 69.301 6.888 ;
     RECT  67.504 32.736 69.301 33.624 ;
     RECT  69.289 34.608 69.301 40.44 ;
     RECT  69.253 60.288 69.337 63.864 ;
     RECT  69.301 32.736 69.373 40.44 ;
     RECT  67.673 69.456 69.397 69.48 ;
     RECT  69.337 62.736 69.433 63.864 ;
     RECT  69.397 69.456 69.437 69.576 ;
     RECT  69.373 36.432 69.509 40.44 ;
     RECT  69.203 8.448 69.545 17.496 ;
     RECT  69.145 42 69.545 52.296 ;
     RECT  68.857 66.336 69.545 68.472 ;
     RECT  69.509 36.432 69.581 39.96 ;
     RECT  69.545 66.336 69.617 66.36 ;
     RECT  69.373 32.736 69.653 35.352 ;
     RECT  69.011 71.712 69.653 71.736 ;
     RECT  69.545 11.808 69.689 17.496 ;
     RECT  68.387 22.848 69.689 22.872 ;
     RECT  69.545 42.72 69.797 52.296 ;
     RECT  69.545 8.448 69.865 10.632 ;
     RECT  68.387 53.568 69.901 53.592 ;
     RECT  68.675 54.864 69.901 54.984 ;
     RECT  69.077 58.368 69.901 58.68 ;
     RECT  69.301 3.696 69.923 6.888 ;
     RECT  69.253 20.16 69.973 21.048 ;
     RECT  69.829 22.224 69.973 22.248 ;
     RECT  69.253 25.056 70.009 31.32 ;
     RECT  69.797 42.72 70.019 45.96 ;
     RECT  70.019 45.936 70.06 45.96 ;
     RECT  69.437 69.552 70.081 69.576 ;
     RECT  69.041 18.672 70.117 19.08 ;
     RECT  69.973 20.16 70.117 22.248 ;
     RECT  69.797 47.04 70.117 52.296 ;
     RECT  70.117 18.672 70.121 22.248 ;
     RECT  69.923 4.512 70.157 6.888 ;
     RECT  70.019 42.72 70.157 44.952 ;
     RECT  70.117 47.04 70.213 52.488 ;
     RECT  70.213 47.04 70.225 52.536 ;
     RECT  69.901 53.568 70.225 54.984 ;
     RECT  68.675 55.968 70.225 57.048 ;
     RECT  70.157 4.512 70.259 6.504 ;
     RECT  70.009 25.008 70.261 31.32 ;
     RECT  69.901 58.032 70.261 58.68 ;
     RECT  69.337 60.288 70.261 61.608 ;
     RECT  70.081 69.552 70.265 70.104 ;
     RECT  69.865 7.92 70.297 10.632 ;
     RECT  69.865 40.944 70.297 41.016 ;
     RECT  70.225 47.04 70.301 57.048 ;
     RECT  70.261 58.032 70.333 61.608 ;
     RECT  69.581 36.432 70.337 38.76 ;
     RECT  70.121 21.936 70.355 22.248 ;
     RECT  70.337 36.432 70.373 38.664 ;
     RECT  70.261 25.008 70.409 31.608 ;
     RECT  70.409 28.944 70.417 31.608 ;
     RECT  70.301 50.64 70.441 57.048 ;
     RECT  70.333 58.032 70.441 61.656 ;
     RECT  69.581 39.84 70.477 39.96 ;
     RECT  70.297 40.944 70.477 41.64 ;
     RECT  69.689 12.528 70.517 17.496 ;
     RECT  70.297 7.584 70.549 10.632 ;
     RECT  70.121 18.672 70.589 20.568 ;
     RECT  70.373 36.432 70.589 38.136 ;
     RECT  70.441 50.64 70.589 61.656 ;
     RECT  70.589 18.672 70.621 19.416 ;
     RECT  69.433 62.736 70.691 64.488 ;
     RECT  70.621 17.76 70.733 19.416 ;
     RECT  70.477 39.84 70.739 41.64 ;
     RECT  70.301 47.04 70.769 49.32 ;
     RECT  70.549 7.584 70.801 10.728 ;
     RECT  70.355 21.984 70.805 22.248 ;
     RECT  70.769 47.376 70.805 49.32 ;
     RECT  70.589 54.096 70.837 61.656 ;
     RECT  70.691 62.736 70.837 64.152 ;
     RECT  69.653 32.736 70.844 34.728 ;
     RECT  70.589 38.064 70.877 38.136 ;
     RECT  70.739 39.84 70.877 39.96 ;
     RECT  70.844 32.736 70.885 35.448 ;
     RECT  70.589 36.432 70.885 36.984 ;
     RECT  70.733 18.192 70.913 19.416 ;
     RECT  70.885 32.736 70.931 36.984 ;
     RECT  70.801 7.584 70.94 10.824 ;
     RECT  70.589 50.64 70.985 52.728 ;
     RECT  70.94 7.584 71.075 11.544 ;
     RECT  71.075 7.92 71.077 11.544 ;
     RECT  70.517 12.528 71.077 16.536 ;
     RECT  70.259 4.512 71.093 6.024 ;
     RECT  70.417 30.48 71.093 31.608 ;
     RECT  71.093 5.136 71.116 6.024 ;
     RECT  71.077 7.92 71.123 16.536 ;
     RECT  70.837 54.096 71.123 64.152 ;
     RECT  69.545 67.344 71.125 68.472 ;
     RECT  71.116 5.136 71.129 5.688 ;
     RECT  71.123 7.92 71.129 12.024 ;
     RECT  71.093 31.584 71.133 31.608 ;
     RECT  70.931 32.736 71.133 34.92 ;
     RECT  70.739 40.944 71.161 41.64 ;
     RECT  70.157 42.72 71.161 44.136 ;
     RECT  71.129 7.968 71.165 12.024 ;
     RECT  70.805 22.032 71.197 22.248 ;
     RECT  71.089 23.52 71.197 23.544 ;
     RECT  71.133 31.584 71.219 34.92 ;
     RECT  71.161 40.944 71.228 44.136 ;
     RECT  71.197 22.032 71.269 23.544 ;
     RECT  70.409 25.008 71.269 27.96 ;
     RECT  70.265 70.08 71.269 70.104 ;
     RECT  71.123 59.472 71.273 64.152 ;
     RECT  70.589 20.544 71.341 20.568 ;
     RECT  71.269 22.032 71.363 27.96 ;
     RECT  71.341 20.544 71.381 21.048 ;
     RECT  71.269 69.504 71.381 70.104 ;
     RECT  70.985 50.832 71.411 52.728 ;
     RECT  71.219 31.584 71.417 33.048 ;
     RECT  70.913 18.192 71.453 18.792 ;
     RECT  70.333 71.472 71.489 71.496 ;
     RECT  71.125 67.104 71.521 68.472 ;
     RECT  71.363 25.248 71.555 27.96 ;
     RECT  71.453 18.768 71.561 18.792 ;
     RECT  71.555 25.248 71.597 27.864 ;
     RECT  70.877 39.84 71.633 39.864 ;
     RECT  71.123 54.096 71.653 58.44 ;
     RECT  71.123 13.008 71.737 16.536 ;
     RECT  71.273 62.736 71.737 64.152 ;
     RECT  71.381 21.024 71.845 21.048 ;
     RECT  71.363 22.032 71.845 23.544 ;
     RECT  70.877 38.064 71.881 38.088 ;
     RECT  71.845 39.072 71.881 39.096 ;
     RECT  71.089 65.808 72.097 65.832 ;
     RECT  71.521 67.104 72.097 68.52 ;
     RECT  71.653 53.568 72.133 58.44 ;
     RECT  71.273 59.472 72.133 61.56 ;
     RECT  71.228 40.944 72.205 44.232 ;
     RECT  70.805 47.376 72.277 47.688 ;
     RECT  72.133 53.568 72.325 61.56 ;
     RECT  71.737 62.736 72.325 64.44 ;
     RECT  71.411 50.832 72.385 52.392 ;
     RECT  72.325 53.568 72.385 64.44 ;
     RECT  70.931 35.904 72.428 35.928 ;
     RECT  70.931 36.96 72.428 36.984 ;
     RECT  72.205 40.944 72.457 44.76 ;
     RECT  72.457 40.224 72.493 44.76 ;
     RECT  72.277 47.376 72.565 47.88 ;
     RECT  71.129 5.136 72.608 5.16 ;
     RECT  71.165 7.968 72.608 11.448 ;
     RECT  71.737 13.008 72.608 16.968 ;
     RECT  71.845 21.024 72.608 23.544 ;
     RECT  71.597 25.248 72.608 26.808 ;
     RECT  71.597 27.84 72.608 27.864 ;
     RECT  70.417 28.944 72.608 29.112 ;
     RECT  71.093 30.48 72.608 30.504 ;
     RECT  71.417 31.584 72.608 32.808 ;
     RECT  71.219 34.464 72.608 34.92 ;
     RECT  72.428 35.904 72.608 36.984 ;
     RECT  71.881 38.064 72.608 39.096 ;
     RECT  72.493 40.224 72.608 45.048 ;
     RECT  72.565 47.376 72.608 47.976 ;
     RECT  70.805 49.296 72.608 49.32 ;
     RECT  72.385 50.832 72.608 64.44 ;
     RECT  72.097 65.808 72.608 68.52 ;
     RECT  71.381 69.504 72.608 69.528 ;
     RECT  72.608 2.148 72.712 73.452 ;
     RECT  72.712 2.418 72.904 73.182 ;
     RECT  72.904 68.112 72.929 68.52 ;
     RECT  72.904 49.296 72.965 49.32 ;
     RECT  72.904 54.096 72.965 54.12 ;
     RECT  72.904 64.32 72.965 64.344 ;
     RECT  72.929 68.4 72.965 68.424 ;
     RECT  72.904 66.528 73.001 66.792 ;
     RECT  72.904 16.272 74.077 16.296 ;
     RECT  72.904 18 74.077 18.6 ;
     RECT  74.077 16.176 74.257 18.6 ;
     RECT  74.257 16.176 74.617 18.792 ;
     RECT  74.077 49.776 74.617 49.8 ;
     RECT  74.617 16.176 74.653 18.984 ;
     RECT  74.617 49.68 74.653 49.8 ;
     RECT  74.653 16.08 74.725 18.984 ;
     RECT  74.653 49.584 75.481 49.8 ;
     RECT  74.725 16.08 75.564 19.08 ;
     RECT  75.481 49.488 75.564 49.8 ;
    LAYER M5 ;
     RECT  2.4 2.137 2.52 2.151 ;
     RECT  7.8 2.137 7.92 2.151 ;
     RECT  13.2 2.137 13.32 2.151 ;
     RECT  18.6 2.137 18.72 2.151 ;
     RECT  24 2.137 24.12 2.151 ;
     RECT  29.4 2.137 29.52 2.151 ;
     RECT  34.8 2.137 34.92 2.151 ;
     RECT  40.2 2.137 40.32 2.151 ;
     RECT  45.6 2.137 45.72 2.151 ;
     RECT  51 2.137 51.12 2.151 ;
     RECT  56.4 2.137 56.52 2.151 ;
     RECT  61.8 2.137 61.92 2.151 ;
     RECT  67.2 2.137 67.32 2.151 ;
     RECT  72.6 2.137 72.72 2.151 ;
     RECT  24 2.151 24.312 2.245 ;
     RECT  67.2 2.151 67.512 2.245 ;
     RECT  5.712 0.016 5.832 2.341 ;
     RECT  51 2.151 51.312 2.341 ;
     RECT  18.6 2.151 18.912 2.533 ;
     RECT  21.216 2.197 21.24 2.533 ;
     RECT  27.024 2.245 27.048 2.581 ;
     RECT  45.6 2.151 45.912 2.581 ;
     RECT  13.2 2.151 13.512 2.773 ;
     RECT  27.024 2.581 28.008 2.773 ;
     RECT  20.544 2.533 21.24 2.821 ;
     RECT  36.432 2.245 36.456 2.821 ;
     RECT  56.4 2.151 56.712 2.821 ;
     RECT  67.2 2.245 67.752 2.867 ;
     RECT  20.544 2.821 21.624 2.915 ;
     RECT  53.472 2.629 53.496 2.915 ;
     RECT  65.328 2.245 65.352 2.915 ;
     RECT  7.8 2.151 8.112 3.109 ;
     RECT  10.032 2.341 10.056 3.109 ;
     RECT  38.352 2.245 38.376 3.157 ;
     RECT  38.256 3.157 38.376 3.203 ;
     RECT  23.664 2.245 24.312 3.299 ;
     RECT  5.712 2.341 6.552 3.397 ;
     RECT  5.616 3.397 6.552 3.443 ;
     RECT  13.2 2.773 13.656 3.443 ;
     RECT  63.12 2.485 63.144 3.443 ;
     RECT  44.832 2.581 45.912 3.637 ;
     RECT  30.72 3.397 30.744 3.685 ;
     RECT  31.824 2.581 31.848 3.685 ;
     RECT  33.024 2.245 33.048 3.685 ;
     RECT  67.2 2.867 67.704 3.733 ;
     RECT  69.888 3.685 69.912 3.733 ;
     RECT  7.8 3.109 10.056 3.827 ;
     RECT  12 2.245 12.024 3.829 ;
     RECT  13.2 3.443 13.512 3.829 ;
     RECT  30.72 3.685 33.048 3.829 ;
     RECT  7.8 3.827 9.096 3.877 ;
     RECT  21.6 2.915 21.624 3.877 ;
     RECT  60.48 3.301 60.504 3.877 ;
     RECT  10.08 3.877 10.104 3.925 ;
     RECT  12 3.829 13.512 3.925 ;
     RECT  17.328 3.877 17.352 3.925 ;
     RECT  29.4 2.151 29.712 3.925 ;
     RECT  40.2 2.151 40.512 3.925 ;
     RECT  67.104 3.733 67.704 3.925 ;
     RECT  69.024 3.733 69.912 3.925 ;
     RECT  26.256 2.773 28.008 3.973 ;
     RECT  25.68 3.973 28.008 4.165 ;
     RECT  29.28 3.925 29.712 4.165 ;
     RECT  59.856 3.877 60.504 4.213 ;
     RECT  61.8 2.151 62.112 4.213 ;
     RECT  23.76 3.299 24.312 4.259 ;
     RECT  5.616 3.443 5.736 4.355 ;
     RECT  64.128 3.925 64.152 4.357 ;
     RECT  58.992 4.213 62.112 4.405 ;
     RECT  16.464 3.925 17.352 4.453 ;
     RECT  18.48 2.533 18.912 4.453 ;
     RECT  20.544 2.915 20.568 4.453 ;
     RECT  21.6 3.877 22.344 4.453 ;
     RECT  55.776 2.821 56.712 4.453 ;
     RECT  63.84 4.357 64.152 4.453 ;
     RECT  0.144 4.213 0.168 4.499 ;
     RECT  20.544 4.453 22.344 4.499 ;
     RECT  16.464 4.453 18.912 4.501 ;
     RECT  25.68 4.165 29.712 4.501 ;
     RECT  30.72 3.829 33.192 4.501 ;
     RECT  44.832 3.637 46.536 4.501 ;
     RECT  50.256 2.341 51.312 4.501 ;
     RECT  58.992 4.405 62.28 4.501 ;
     RECT  6.816 3.877 9.096 4.739 ;
     RECT  36.432 2.821 37.032 4.741 ;
     RECT  65.28 4.501 65.304 4.741 ;
     RECT  66.336 3.925 69.912 4.741 ;
     RECT  10.08 3.925 13.512 4.835 ;
     RECT  36.384 4.741 37.032 4.835 ;
     RECT  55.488 4.453 56.712 4.837 ;
     RECT  58.032 4.501 62.28 4.837 ;
     RECT  12.432 4.835 13.512 4.931 ;
     RECT  25.68 4.501 33.192 4.931 ;
     RECT  55.488 4.837 62.28 4.933 ;
     RECT  25.68 4.931 32.568 4.979 ;
     RECT  44.832 4.501 46.68 5.029 ;
     RECT  5.712 4.355 5.736 5.077 ;
     RECT  6.816 4.739 8.112 5.077 ;
     RECT  65.28 4.741 69.912 5.077 ;
     RECT  34.8 2.151 35.112 5.125 ;
     RECT  63.456 4.453 64.152 5.125 ;
     RECT  65.28 5.077 69.96 5.125 ;
     RECT  15.408 3.109 15.432 5.171 ;
     RECT  49.536 4.501 51.312 5.173 ;
     RECT  63.456 5.125 69.96 5.267 ;
     RECT  10.08 4.835 11.256 5.411 ;
     RECT  16.464 4.501 19.032 5.461 ;
     RECT  48.096 2.773 48.12 5.461 ;
     RECT  49.536 5.173 51.432 5.461 ;
     RECT  22.32 4.499 22.344 5.509 ;
     RECT  23.904 4.259 24.312 5.509 ;
     RECT  22.32 5.509 24.312 5.557 ;
     RECT  16.32 5.461 19.032 5.603 ;
     RECT  64.368 5.267 69.96 5.605 ;
     RECT  64.368 5.605 70.008 5.653 ;
     RECT  71.04 4.981 71.064 5.653 ;
     RECT  38.256 3.203 38.28 5.747 ;
     RECT  55.44 4.933 62.28 5.747 ;
     RECT  64.368 5.653 71.064 5.747 ;
     RECT  25.68 4.979 26.28 5.843 ;
     RECT  20.544 4.499 21.288 6.035 ;
     RECT  40.2 3.925 40.872 6.037 ;
     RECT  22.32 5.557 24.504 6.085 ;
     RECT  59.472 5.747 62.28 6.181 ;
     RECT  27.984 4.979 32.568 6.227 ;
     RECT  12.48 4.931 13.512 6.277 ;
     RECT  21.12 6.035 21.288 6.323 ;
     RECT  27.984 6.227 32.04 6.323 ;
     RECT  64.368 5.747 67.896 6.323 ;
     RECT  34.224 5.125 35.112 6.419 ;
     RECT  43.2 6.277 43.224 6.421 ;
     RECT  48.096 5.461 51.432 6.467 ;
     RECT  69.072 5.747 71.064 6.515 ;
     RECT  31.584 6.323 32.04 6.563 ;
     RECT  12.48 6.277 13.608 6.611 ;
     RECT  13.056 6.611 13.608 6.709 ;
     RECT  37.584 6.277 37.608 6.709 ;
     RECT  16.32 5.603 18.912 6.757 ;
     RECT  15.984 6.757 18.912 6.803 ;
     RECT  25.824 5.843 25.848 6.805 ;
     RECT  53.76 3.109 53.784 6.805 ;
     RECT  5.712 5.077 8.112 6.851 ;
     RECT  50.16 6.467 51.432 6.851 ;
     RECT  64.368 6.323 65.592 6.851 ;
     RECT  55.488 5.747 58.104 6.899 ;
     RECT  21.264 6.323 21.288 6.995 ;
     RECT  27.984 6.323 30.36 7.139 ;
     RECT  39.84 6.037 40.872 7.187 ;
     RECT  40.2 7.187 40.872 7.235 ;
     RECT  42.24 6.421 43.224 7.283 ;
     RECT  44.832 5.029 46.728 7.283 ;
     RECT  13.056 6.709 13.992 7.333 ;
     RECT  22.272 6.085 24.504 7.333 ;
     RECT  25.584 6.805 25.848 7.381 ;
     RECT  59.472 6.181 63.192 7.381 ;
     RECT  13.056 7.333 14.376 7.429 ;
     RECT  22.272 7.333 24.552 7.477 ;
     RECT  59.232 7.381 63.192 7.523 ;
     RECT  45.024 7.283 46.728 7.619 ;
     RECT  67.008 6.323 67.896 7.667 ;
     RECT  25.584 7.381 26.136 7.669 ;
     RECT  28.512 7.139 30.36 7.717 ;
     RECT  10.08 5.411 10.536 7.861 ;
     RECT  5.712 6.851 5.736 7.909 ;
     RECT  6.768 6.851 8.112 7.909 ;
     RECT  10.08 7.861 10.632 7.909 ;
     RECT  13.056 7.429 14.856 7.909 ;
     RECT  50.16 6.851 51.312 7.909 ;
     RECT  28.512 7.717 30.408 7.957 ;
     RECT  36.384 4.835 36.456 7.957 ;
     RECT  37.584 6.709 37.656 7.957 ;
     RECT  33.024 7.381 33.048 8.003 ;
     RECT  36.384 7.957 37.656 8.003 ;
     RECT  67.008 7.667 67.848 8.003 ;
     RECT  42.24 7.283 42.264 8.149 ;
     RECT  37.056 8.003 37.656 8.195 ;
     RECT  15.984 6.803 16.344 8.245 ;
     RECT  17.328 6.803 18.912 8.245 ;
     RECT  34.464 6.419 35.112 8.245 ;
     RECT  21.888 7.477 24.552 8.341 ;
     RECT  25.584 7.669 26.76 8.341 ;
     RECT  32.016 6.563 32.04 8.341 ;
     RECT  69.072 6.515 70.008 8.437 ;
     RECT  9.744 7.909 10.632 8.485 ;
     RECT  5.712 7.909 8.112 8.533 ;
     RECT  48.096 6.467 49.128 8.579 ;
     RECT  34.08 8.245 35.112 8.725 ;
     RECT  21.888 8.341 26.76 8.771 ;
     RECT  59.232 7.523 60.408 8.771 ;
     RECT  20.4 7.381 20.424 8.773 ;
     RECT  21.888 8.771 26.136 8.773 ;
     RECT  59.472 8.771 60.408 8.819 ;
     RECT  56.112 6.899 58.104 8.869 ;
     RECT  40.2 7.235 40.728 8.917 ;
     RECT  41.952 8.149 42.264 8.917 ;
     RECT  53.76 6.805 53.832 8.963 ;
     RECT  49.104 8.579 49.128 9.013 ;
     RECT  50.16 7.909 51.912 9.013 ;
     RECT  5.04 8.533 8.112 9.061 ;
     RECT  9.696 8.485 10.632 9.061 ;
     RECT  5.04 9.061 10.632 9.107 ;
     RECT  45.024 7.619 46.68 9.107 ;
     RECT  12.672 7.909 14.856 9.155 ;
     RECT  45.168 9.107 46.68 9.253 ;
     RECT  48.096 8.579 48.12 9.253 ;
     RECT  45.168 9.253 48.12 9.299 ;
     RECT  69.024 8.437 70.008 9.299 ;
     RECT  20.4 8.773 26.136 9.395 ;
     RECT  28.512 7.957 30.984 9.397 ;
     RECT  32.016 8.341 32.52 9.397 ;
     RECT  49.104 9.013 51.912 9.589 ;
     RECT  13.2 9.155 14.856 9.637 ;
     RECT  15.984 8.245 18.912 9.637 ;
     RECT  55.824 8.869 58.104 9.685 ;
     RECT  7.8 9.107 10.632 9.731 ;
     RECT  34.032 8.725 35.112 9.731 ;
     RECT  71.04 6.515 71.064 9.781 ;
     RECT  72.6 2.151 72.912 9.781 ;
     RECT  7.8 9.731 10.296 9.827 ;
     RECT  27.36 8.869 27.384 9.925 ;
     RECT  28.512 9.397 32.52 9.925 ;
     RECT  40.2 8.917 42.264 9.925 ;
     RECT  27.36 9.925 32.52 9.971 ;
     RECT  39.264 9.925 42.264 10.115 ;
     RECT  55.824 9.685 58.152 10.165 ;
     RECT  59.712 8.819 60.408 10.165 ;
     RECT  64.368 6.851 65.352 10.165 ;
     RECT  13.2 9.637 18.912 10.213 ;
     RECT  48.864 9.589 51.912 10.213 ;
     RECT  20.4 9.395 24.84 10.307 ;
     RECT  26.112 9.395 26.136 10.307 ;
     RECT  2.4 2.151 2.712 10.309 ;
     RECT  55.824 10.165 60.408 10.309 ;
     RECT  28.32 9.971 32.52 10.355 ;
     RECT  45.168 9.299 47.592 10.355 ;
     RECT  71.04 9.781 72.912 10.403 ;
     RECT  55.344 10.309 60.408 10.453 ;
     RECT  61.392 7.523 63.192 10.453 ;
     RECT  20.4 10.307 21.336 10.499 ;
     RECT  67.104 8.003 67.848 10.643 ;
     RECT  43.632 10.213 43.656 10.741 ;
     RECT  48.864 10.213 51.96 10.741 ;
     RECT  11.568 10.405 11.592 10.883 ;
     RECT  39.264 10.115 41.976 10.883 ;
     RECT  48.864 10.741 52.296 10.883 ;
     RECT  69.072 9.299 70.008 10.883 ;
     RECT  12.72 10.213 18.912 10.885 ;
     RECT  53.76 8.963 53.784 10.931 ;
     RECT  55.344 10.453 63.192 10.931 ;
     RECT  67.104 10.643 67.8 10.981 ;
     RECT  34.08 9.731 35.112 11.029 ;
     RECT  43.632 10.741 44.184 11.075 ;
     RECT  37.056 8.195 37.176 11.125 ;
     RECT  57.84 10.931 63.192 11.317 ;
     RECT  64.224 10.165 65.736 11.317 ;
     RECT  6.768 9.107 6.792 11.365 ;
     RECT  7.8 9.827 8.112 11.365 ;
     RECT  22.464 10.307 24.84 11.365 ;
     RECT  48.96 10.883 52.296 11.365 ;
     RECT  71.088 10.403 72.912 11.365 ;
     RECT  2.4 10.309 3.384 11.459 ;
     RECT  25.968 11.029 25.992 11.509 ;
     RECT  28.32 10.355 30.984 11.555 ;
     RECT  12 10.885 18.912 11.557 ;
     RECT  33.984 11.029 35.112 11.653 ;
     RECT  43.632 11.075 43.992 11.699 ;
     RECT  6.768 11.365 8.112 11.701 ;
     RECT  9.504 9.827 10.296 11.701 ;
     RECT  57.84 11.317 65.736 11.747 ;
     RECT  12 11.557 19.368 11.749 ;
     RECT  20.592 10.499 21.336 11.749 ;
     RECT  45.168 10.355 45.912 11.749 ;
     RECT  47.04 10.355 47.592 11.749 ;
     RECT  6.768 11.701 10.296 11.795 ;
     RECT  29.184 11.555 30.984 11.893 ;
     RECT  32.352 10.355 32.52 11.893 ;
     RECT  37.056 11.125 37.656 11.893 ;
     RECT  45.168 11.749 47.592 11.893 ;
     RECT  48.96 11.365 52.44 11.893 ;
     RECT  39.888 10.883 41.976 11.941 ;
     RECT  12 11.749 21.336 12.035 ;
     RECT  15.408 12.035 21.336 12.085 ;
     RECT  22.464 11.365 24.936 12.085 ;
     RECT  12 12.035 13.848 12.179 ;
     RECT  55.344 10.931 56.808 12.277 ;
     RECT  57.84 11.747 63.768 12.277 ;
     RECT  6.768 11.795 9.096 12.323 ;
     RECT  15.408 12.085 24.936 12.371 ;
     RECT  12 12.179 13.608 12.469 ;
     RECT  6.864 12.323 9.096 12.563 ;
     RECT  16.8 12.371 24.936 12.563 ;
     RECT  22.128 12.563 24.936 12.757 ;
     RECT  25.968 11.509 26.664 12.757 ;
     RECT  28.08 11.797 28.104 12.805 ;
     RECT  29.184 11.893 32.52 12.805 ;
     RECT  37.008 11.893 37.656 12.805 ;
     RECT  2.4 11.459 2.712 12.901 ;
     RECT  37.008 12.805 38.52 12.949 ;
     RECT  22.128 12.757 26.664 12.995 ;
     RECT  64.944 11.747 65.736 13.045 ;
     RECT  66.96 10.981 67.8 13.045 ;
     RECT  7.8 12.563 9.096 13.091 ;
     RECT  11.376 12.469 13.608 13.091 ;
     RECT  22.128 12.995 26.376 13.091 ;
     RECT  22.128 13.091 24.984 13.235 ;
     RECT  54.144 12.517 54.168 13.237 ;
     RECT  28.08 12.805 32.52 13.283 ;
     RECT  53.616 13.237 54.168 13.283 ;
     RECT  11.376 13.091 12.024 13.331 ;
     RECT  36.912 12.949 38.52 13.333 ;
     RECT  13.056 13.091 13.608 13.381 ;
     RECT  15.408 12.371 15.72 13.381 ;
     RECT  5.616 9.107 5.736 13.429 ;
     RECT  13.056 13.381 15.72 13.429 ;
     RECT  16.8 12.563 21.144 13.429 ;
     RECT  33.984 11.653 35.304 13.429 ;
     RECT  13.056 13.429 21.144 13.475 ;
     RECT  31.584 13.283 32.52 13.523 ;
     RECT  45.168 11.893 52.44 13.523 ;
     RECT  39.888 11.941 42.744 13.571 ;
     RECT  10.08 11.795 10.296 13.573 ;
     RECT  47.04 13.523 52.44 13.619 ;
     RECT  43.968 11.699 43.992 13.621 ;
     RECT  45.168 13.523 45.912 13.621 ;
     RECT  10.08 13.573 10.728 13.667 ;
     RECT  64.944 13.045 67.8 13.667 ;
     RECT  69.408 10.883 70.008 13.669 ;
     RECT  70.992 11.365 72.912 13.669 ;
     RECT  55.344 12.277 63.768 13.715 ;
     RECT  69.408 13.669 72.912 13.715 ;
     RECT  2.4 12.901 3.192 13.859 ;
     RECT  53.616 13.283 53.64 13.859 ;
     RECT  11.952 13.331 12.024 14.101 ;
     RECT  13.056 13.475 16.2 14.101 ;
     RECT  36.672 13.333 38.52 14.101 ;
     RECT  4.752 13.429 5.736 14.197 ;
     RECT  48.48 13.619 52.44 14.243 ;
     RECT  33.984 13.429 35.592 14.291 ;
     RECT  39.888 13.571 42.264 14.291 ;
     RECT  48.48 14.243 51.312 14.291 ;
     RECT  25.968 13.091 26.376 14.389 ;
     RECT  52.416 14.243 52.44 14.485 ;
     RECT  69.408 13.715 70.44 14.533 ;
     RECT  39.888 14.291 41.976 14.627 ;
     RECT  17.52 13.475 21.144 14.675 ;
     RECT  28.08 13.283 30.264 14.675 ;
     RECT  11.952 14.101 16.2 14.867 ;
     RECT  36.672 14.101 38.808 14.869 ;
     RECT  39.888 14.627 40.512 14.869 ;
     RECT  12 14.867 16.2 14.915 ;
     RECT  69.36 14.533 70.44 14.915 ;
     RECT  31.632 13.523 32.52 14.917 ;
     RECT  33.984 14.291 35.352 14.917 ;
     RECT  63.504 13.715 63.768 15.013 ;
     RECT  64.944 13.667 67.704 15.013 ;
     RECT  43.968 13.621 45.912 15.059 ;
     RECT  10.704 13.667 10.728 15.061 ;
     RECT  55.344 13.715 62.328 15.107 ;
     RECT  25.968 14.389 26.808 15.109 ;
     RECT  28.08 14.675 29.712 15.109 ;
     RECT  59.808 15.107 62.328 15.157 ;
     RECT  63.504 15.013 67.704 15.157 ;
     RECT  69.36 14.915 69.576 15.157 ;
     RECT  18.48 14.675 21.144 15.251 ;
     RECT  59.808 15.157 67.704 15.253 ;
     RECT  7.8 13.091 8.808 15.301 ;
     RECT  31.632 14.917 35.352 15.301 ;
     RECT  25.968 15.109 29.712 15.347 ;
     RECT  31.392 15.301 35.352 15.347 ;
     RECT  4.608 14.197 5.736 15.395 ;
     RECT  48.624 14.291 51.312 15.443 ;
     RECT  68.976 15.157 69.576 15.443 ;
     RECT  22.464 13.235 24.984 15.493 ;
     RECT  25.968 15.347 26.376 15.493 ;
     RECT  22.464 15.493 26.376 15.539 ;
     RECT  27.36 15.347 29.712 15.733 ;
     RECT  14.496 14.915 16.2 15.781 ;
     RECT  55.344 15.107 58.776 15.827 ;
     RECT  52.416 14.485 53.304 15.877 ;
     RECT  4.896 15.395 5.736 15.973 ;
     RECT  27.36 15.733 29.832 15.973 ;
     RECT  10.032 15.061 10.728 16.019 ;
     RECT  14.496 15.781 16.968 16.019 ;
     RECT  36.672 14.869 40.512 16.019 ;
     RECT  68.976 15.443 69.432 16.019 ;
     RECT  59.808 15.253 67.752 16.067 ;
     RECT  27.36 15.973 29.928 16.115 ;
     RECT  59.808 16.067 66.216 16.115 ;
     RECT  18.48 15.251 21.096 16.357 ;
     RECT  41.52 14.627 41.976 16.357 ;
     RECT  18.288 16.357 21.096 16.403 ;
     RECT  33.696 15.347 35.352 16.403 ;
     RECT  7.68 15.301 8.808 16.499 ;
     RECT  43.968 15.059 44.088 16.501 ;
     RECT  33.984 16.403 35.352 16.547 ;
     RECT  7.8 16.499 8.808 16.595 ;
     RECT  25.584 15.539 26.376 16.595 ;
     RECT  69.168 16.019 69.384 16.595 ;
     RECT  26.352 16.595 26.376 16.645 ;
     RECT  27.36 16.115 29.832 16.645 ;
     RECT  15.648 16.019 16.968 16.691 ;
     RECT  34.032 16.547 35.352 16.691 ;
     RECT  4.896 15.973 6.312 16.787 ;
     RECT  41.52 16.357 42.168 16.835 ;
     RECT  52.416 15.877 53.832 16.933 ;
     RECT  37.632 16.019 38.52 16.979 ;
     RECT  43.632 16.501 44.088 16.981 ;
     RECT  45.6 15.059 45.912 16.981 ;
     RECT  10.704 16.019 10.728 17.027 ;
     RECT  50.736 15.443 51.312 17.029 ;
     RECT  52.416 16.933 54.072 17.029 ;
     RECT  43.632 16.981 45.912 17.075 ;
     RECT  47.04 13.619 47.064 17.075 ;
     RECT  37.632 16.979 37.992 17.077 ;
     RECT  43.872 17.075 45.912 17.123 ;
     RECT  61.8 16.115 66.216 17.123 ;
     RECT  50.736 17.029 54.072 17.363 ;
     RECT  26.352 16.645 29.832 17.365 ;
     RECT  31.392 15.347 32.184 17.365 ;
     RECT  26.352 17.365 32.184 17.411 ;
     RECT  22.464 15.539 24.504 17.413 ;
     RECT  55.536 15.827 58.776 17.413 ;
     RECT  59.808 16.115 60.744 17.413 ;
     RECT  61.8 17.123 65.736 17.459 ;
     RECT  12 14.915 13.512 17.461 ;
     RECT  40.2 16.019 40.512 17.461 ;
     RECT  50.736 17.363 52.632 17.555 ;
     RECT  14.496 16.019 14.52 17.605 ;
     RECT  15.648 16.691 15.72 17.605 ;
     RECT  48.624 15.443 49.608 17.605 ;
     RECT  55.536 17.413 60.744 17.605 ;
     RECT  7.8 16.595 8.568 17.651 ;
     RECT  22.176 17.413 24.504 17.651 ;
     RECT  64.08 17.459 65.736 17.651 ;
     RECT  16.944 16.691 16.968 17.701 ;
     RECT  7.8 17.651 8.424 17.747 ;
     RECT  50.736 17.555 52.536 17.891 ;
     RECT  34.032 16.691 35.304 17.939 ;
     RECT  26.928 17.411 32.184 17.941 ;
     RECT  48.48 17.605 49.608 17.941 ;
     RECT  50.736 17.891 51.432 17.941 ;
     RECT  41.52 16.835 41.544 17.987 ;
     RECT  14.496 17.605 15.72 18.037 ;
     RECT  16.944 17.701 17.016 18.037 ;
     RECT  7.8 17.747 8.112 18.133 ;
     RECT  26.928 17.941 32.664 18.181 ;
     RECT  26.928 18.181 33.048 18.275 ;
     RECT  61.8 17.459 62.952 18.275 ;
     RECT  4.896 16.787 5.832 18.323 ;
     RECT  18.288 16.403 20.616 18.467 ;
     RECT  37.104 17.077 37.992 18.661 ;
     RECT  43.872 17.123 44.088 18.661 ;
     RECT  45.312 17.123 45.912 18.707 ;
     RECT  64.368 17.651 65.736 18.709 ;
     RECT  14.496 18.037 17.016 18.755 ;
     RECT  34.032 17.939 35.256 18.755 ;
     RECT  15.6 18.755 17.016 18.803 ;
     RECT  37.056 18.661 37.992 18.803 ;
     RECT  55.536 17.605 60.792 18.803 ;
     RECT  9.696 18.709 9.72 18.851 ;
     RECT  43.296 18.661 44.088 18.851 ;
     RECT  69.168 16.595 69.192 18.851 ;
     RECT  4.896 18.323 5.736 18.899 ;
     RECT  64.272 18.709 65.736 18.949 ;
     RECT  67.2 16.067 67.752 18.949 ;
     RECT  5.616 18.899 5.736 18.995 ;
     RECT  37.104 18.803 37.992 18.995 ;
     RECT  26.928 18.275 26.952 19.045 ;
     RECT  22.176 17.651 22.2 19.237 ;
     RECT  43.872 18.851 44.088 19.237 ;
     RECT  21.696 19.237 22.2 19.283 ;
     RECT  43.872 19.237 44.472 19.283 ;
     RECT  64.272 18.949 67.752 19.285 ;
     RECT  15.6 18.803 15.96 19.331 ;
     RECT  48.48 17.941 51.432 19.331 ;
     RECT  55.536 18.803 60.744 19.331 ;
     RECT  21.696 19.283 21.72 19.333 ;
     RECT  15.6 19.331 15.864 19.427 ;
     RECT  39.888 17.461 40.512 19.427 ;
     RECT  48.576 19.331 51.432 19.523 ;
     RECT  53.808 17.363 54.072 19.525 ;
     RECT  55.728 19.331 60.744 19.571 ;
     RECT  52.464 17.891 52.536 19.573 ;
     RECT  28.032 18.275 33.048 19.765 ;
     RECT  34.032 18.755 35.112 19.765 ;
     RECT  18.288 18.467 19.704 19.909 ;
     RECT  21.648 19.333 21.72 19.955 ;
     RECT  55.776 19.571 60.744 20.003 ;
     RECT  48.576 19.523 51.312 20.051 ;
     RECT  58.992 20.003 60.744 20.243 ;
     RECT  11.424 17.461 13.512 20.293 ;
     RECT  14.496 18.755 14.52 20.293 ;
     RECT  11.424 20.293 14.76 20.339 ;
     RECT  45.6 18.707 45.912 20.389 ;
     RECT  15.84 19.427 15.864 20.437 ;
     RECT  16.992 18.803 17.016 20.437 ;
     RECT  26.208 19.045 26.952 20.437 ;
     RECT  28.032 19.765 35.112 20.437 ;
     RECT  63.888 19.285 67.752 20.437 ;
     RECT  5.712 18.995 5.736 20.485 ;
     RECT  7.68 18.133 8.112 20.485 ;
     RECT  60.72 20.243 60.744 20.485 ;
     RECT  61.8 18.275 62.112 20.485 ;
     RECT  18.288 19.909 20.424 20.579 ;
     RECT  63.888 20.437 68.808 20.581 ;
     RECT  18.48 20.579 20.424 20.627 ;
     RECT  44.064 19.283 44.472 20.725 ;
     RECT  26.208 20.437 35.112 20.773 ;
     RECT  23.232 17.651 24.504 20.819 ;
     RECT  15.84 20.437 17.016 20.869 ;
     RECT  43.296 20.725 44.472 20.917 ;
     RECT  45.504 20.389 45.912 20.917 ;
     RECT  18.6 20.627 20.424 20.965 ;
     RECT  37.104 18.995 37.848 20.965 ;
     RECT  63.504 20.581 68.808 21.013 ;
     RECT  40.2 19.427 40.512 21.061 ;
     RECT  48.864 20.051 51.312 21.155 ;
     RECT  39.696 21.061 40.512 21.157 ;
     RECT  55.776 20.003 57.768 21.157 ;
     RECT  58.992 20.243 59.688 21.157 ;
     RECT  55.776 21.157 59.688 21.203 ;
     RECT  10.8 21.061 10.824 21.205 ;
     RECT  26.16 20.773 35.112 21.205 ;
     RECT  36.672 20.965 37.848 21.205 ;
     RECT  55.776 21.203 59.016 21.299 ;
     RECT  43.296 20.917 45.912 21.491 ;
     RECT  5.712 20.485 6.312 21.635 ;
     RECT  5.712 21.635 5.736 21.637 ;
     RECT  10.224 21.205 10.824 21.685 ;
     RECT  11.808 20.339 14.76 21.685 ;
     RECT  10.224 21.685 14.76 21.731 ;
     RECT  23.232 20.819 24.312 21.731 ;
     RECT  39.696 21.157 41.112 21.781 ;
     RECT  72.6 13.715 72.912 21.781 ;
     RECT  13.056 21.731 14.76 21.827 ;
     RECT  43.296 21.491 44.616 21.827 ;
     RECT  13.104 21.827 14.76 21.971 ;
     RECT  70.32 20.389 70.344 21.971 ;
     RECT  23.76 21.731 24.312 21.973 ;
     RECT  23.76 21.973 24.456 22.021 ;
     RECT  60.72 20.485 62.112 22.021 ;
     RECT  72.24 21.781 72.912 22.021 ;
     RECT  13.2 21.971 14.76 22.117 ;
     RECT  15.744 20.869 17.016 22.117 ;
     RECT  10.224 21.731 11.592 22.165 ;
     RECT  13.2 22.117 17.016 22.165 ;
     RECT  18.6 20.965 20.52 22.165 ;
     RECT  26.16 21.205 37.848 22.165 ;
     RECT  39.6 21.781 41.112 22.165 ;
     RECT  48.864 21.155 49.032 22.211 ;
     RECT  50.16 21.155 51.312 22.211 ;
     RECT  7.68 20.485 8.232 22.259 ;
     RECT  21.696 19.955 21.72 22.259 ;
     RECT  55.776 21.299 58.728 22.259 ;
     RECT  46.944 22.165 46.968 22.261 ;
     RECT  63.504 21.013 68.856 22.307 ;
     RECT  26.16 22.165 41.112 22.451 ;
     RECT  48.864 22.211 48.936 22.451 ;
     RECT  13.2 22.165 20.52 22.547 ;
     RECT  48.864 22.451 48.888 22.645 ;
     RECT  60.384 22.021 62.112 22.645 ;
     RECT  44.592 21.827 44.616 22.691 ;
     RECT  45.6 21.491 45.912 22.693 ;
     RECT  17.856 22.547 20.52 22.787 ;
     RECT  63.504 22.307 64.488 22.787 ;
     RECT  9.936 22.165 11.592 22.835 ;
     RECT  48.096 22.645 48.888 22.835 ;
     RECT  50.256 22.211 51.312 22.979 ;
     RECT  34.032 22.451 41.112 23.027 ;
     RECT  50.4 22.979 51.312 23.171 ;
     RECT  43.296 21.827 43.32 23.173 ;
     RECT  55.776 22.259 58.344 23.267 ;
     RECT  63.504 22.787 64.392 23.267 ;
     RECT  7.8 22.259 8.232 23.317 ;
     RECT  9.936 22.835 9.96 23.317 ;
     RECT  13.2 22.547 16.152 23.363 ;
     RECT  23.76 22.021 24.552 23.555 ;
     RECT  48.096 22.835 48.12 23.555 ;
     RECT  71.28 22.021 72.912 23.555 ;
     RECT  26.16 22.451 32.952 23.605 ;
     RECT  3.984 21.301 4.008 23.699 ;
     RECT  50.688 23.171 51.312 23.699 ;
     RECT  60.384 22.645 62.52 23.845 ;
     RECT  63.504 23.267 64.344 23.845 ;
     RECT  7.8 23.317 9.96 23.893 ;
     RECT  17.856 22.787 20.424 23.893 ;
     RECT  44.64 22.693 45.912 23.893 ;
     RECT  46.944 22.261 47.064 23.893 ;
     RECT  53.808 19.525 54.264 23.893 ;
     RECT  36.24 23.027 40.512 23.939 ;
     RECT  60.384 23.845 64.344 23.939 ;
     RECT  7.632 23.893 9.96 23.987 ;
     RECT  25.968 23.605 32.952 23.987 ;
     RECT  53.76 23.893 54.264 24.085 ;
     RECT  17.328 23.893 20.424 24.179 ;
     RECT  15.744 23.363 16.152 24.227 ;
     RECT  56.4 23.267 58.344 24.229 ;
     RECT  36.24 23.939 38.568 24.419 ;
     RECT  65.568 22.307 68.856 24.421 ;
     RECT  13.2 23.363 14.52 24.467 ;
     RECT  16.128 24.227 16.152 24.469 ;
     RECT  17.328 24.179 19.368 24.469 ;
     RECT  42.432 23.173 43.32 24.469 ;
     RECT  44.64 23.893 47.064 24.563 ;
     RECT  49.536 24.469 49.56 24.757 ;
     RECT  50.736 23.699 51.312 24.757 ;
     RECT  34.032 23.027 35.112 24.805 ;
     RECT  44.976 24.563 47.064 24.851 ;
     RECT  47.904 24.853 47.928 24.997 ;
     RECT  60.384 23.939 64.104 24.997 ;
     RECT  65.568 24.421 68.952 24.997 ;
     RECT  23.76 23.555 24.456 25.045 ;
     RECT  25.968 23.987 30.936 25.045 ;
     RECT  42.432 24.469 43.368 25.045 ;
     RECT  60.384 24.997 68.952 25.045 ;
     RECT  32.16 23.987 32.952 25.189 ;
     RECT  7.632 23.987 8.112 25.285 ;
     RECT  0.144 25.189 0.168 25.331 ;
     RECT  52.464 19.573 52.728 25.573 ;
     RECT  53.76 24.085 54.504 25.573 ;
     RECT  31.92 25.189 32.952 25.621 ;
     RECT  34.032 24.805 35.304 25.621 ;
     RECT  49.536 24.757 51.312 25.621 ;
     RECT  31.92 25.621 35.304 25.669 ;
     RECT  36.288 24.419 38.568 25.669 ;
     RECT  3.984 25.045 4.008 25.715 ;
     RECT  11.568 22.835 11.592 25.715 ;
     RECT  47.904 24.997 48.552 25.715 ;
     RECT  60.384 25.045 69.864 25.717 ;
     RECT  60.384 25.717 70.152 25.859 ;
     RECT  9.936 23.987 9.96 25.861 ;
     RECT  16.128 24.469 19.368 26.005 ;
     RECT  20.352 24.179 20.424 26.053 ;
     RECT  21.888 24.949 21.912 26.053 ;
     RECT  9.936 25.861 10.104 26.101 ;
     RECT  41.568 25.045 43.368 26.147 ;
     RECT  60.384 25.859 64.248 26.197 ;
     RECT  20.352 26.053 21.912 26.243 ;
     RECT  31.92 25.669 38.568 26.243 ;
     RECT  48 25.715 48.552 26.243 ;
     RECT  59.856 26.197 64.248 26.243 ;
     RECT  31.92 26.243 38.424 26.291 ;
     RECT  65.568 25.859 70.152 26.291 ;
     RECT  2.4 13.859 2.712 26.293 ;
     RECT  14.736 25.045 14.76 26.293 ;
     RECT  52.464 25.573 54.504 26.387 ;
     RECT  71.28 23.555 71.352 26.389 ;
     RECT  5.04 21.637 5.736 26.483 ;
     RECT  7.632 25.285 8.472 26.533 ;
     RECT  9.936 26.101 10.536 26.533 ;
     RECT  13.2 24.467 13.752 26.533 ;
     RECT  55.584 24.229 58.344 26.675 ;
     RECT  9.936 26.533 11.208 26.677 ;
     RECT  9.936 26.677 11.352 26.725 ;
     RECT  31.92 26.291 35.304 26.819 ;
     RECT  71.28 26.389 71.592 26.819 ;
     RECT  32.16 26.819 35.304 26.867 ;
     RECT  49.536 25.621 51.48 26.867 ;
     RECT  69.936 26.291 70.152 26.867 ;
     RECT  2.304 26.293 2.712 26.915 ;
     RECT  25.632 25.045 30.936 27.107 ;
     RECT  36.288 26.291 38.424 27.107 ;
     RECT  20.352 26.243 21.096 27.203 ;
     RECT  25.632 27.107 30.696 27.203 ;
     RECT  71.28 26.819 71.544 27.203 ;
     RECT  20.4 27.203 21.096 27.205 ;
     RECT  52.608 26.387 54.504 27.251 ;
     RECT  23.52 25.045 24.456 27.301 ;
     RECT  13.104 26.533 13.752 27.349 ;
     RECT  14.736 26.293 14.952 27.349 ;
     RECT  65.568 26.291 68.952 27.395 ;
     RECT  61.488 26.243 64.248 27.397 ;
     RECT  2.4 26.915 2.712 27.445 ;
     RECT  59.856 26.243 60.504 27.445 ;
     RECT  61.488 27.397 64.44 27.445 ;
     RECT  49.536 26.867 49.56 27.635 ;
     RECT  13.104 27.349 14.952 27.683 ;
     RECT  55.872 26.675 58.344 27.685 ;
     RECT  7.2 26.533 8.472 27.731 ;
     RECT  42.192 26.147 43.368 27.733 ;
     RECT  44.976 24.851 46.872 27.733 ;
     RECT  36.528 27.107 38.424 27.779 ;
     RECT  69.936 26.867 70.104 27.827 ;
     RECT  13.2 27.683 14.952 27.875 ;
     RECT  48 26.243 48.024 27.875 ;
     RECT  55.872 27.685 58.68 27.875 ;
     RECT  52.848 27.251 54.504 27.877 ;
     RECT  55.872 27.875 57.672 27.877 ;
     RECT  59.856 27.445 64.44 27.877 ;
     RECT  65.568 27.395 67.608 27.877 ;
     RECT  36.528 27.779 37.848 27.923 ;
     RECT  71.52 27.203 71.544 27.971 ;
     RECT  3.936 27.589 3.96 28.021 ;
     RECT  9.936 26.725 11.496 28.163 ;
     RECT  59.856 27.877 67.608 28.259 ;
     RECT  52.848 27.877 57.672 28.261 ;
     RECT  70.08 27.827 70.104 28.307 ;
     RECT  50.688 26.867 51.48 28.309 ;
     RECT  20.4 27.205 21.72 28.403 ;
     RECT  23.52 27.301 24.6 28.451 ;
     RECT  63.6 28.259 67.608 28.451 ;
     RECT  59.856 28.259 62.112 28.499 ;
     RECT  16.08 26.005 19.368 28.501 ;
     RECT  20.4 28.403 20.808 28.501 ;
     RECT  64.224 28.451 67.608 28.547 ;
     RECT  64.224 28.547 64.44 28.595 ;
     RECT  32.592 26.867 35.304 28.691 ;
     RECT  42 27.733 43.368 28.741 ;
     RECT  16.08 28.501 20.808 28.787 ;
     RECT  34.032 28.691 35.304 28.835 ;
     RECT  52.704 28.261 57.672 28.979 ;
     RECT  52.704 28.979 57.576 29.029 ;
     RECT  13.2 27.875 14.856 29.077 ;
     RECT  41.952 28.741 43.368 29.221 ;
     RECT  58.656 27.875 58.68 29.267 ;
     RECT  41.952 29.221 43.512 29.269 ;
     RECT  44.64 27.733 46.872 29.269 ;
     RECT  50.016 28.309 51.48 29.269 ;
     RECT  5.712 26.483 5.736 29.317 ;
     RECT  39.696 23.939 40.512 29.365 ;
     RECT  9.936 28.163 11.352 29.507 ;
     RECT  23.52 28.451 24.456 29.605 ;
     RECT  25.824 27.203 30.696 29.605 ;
     RECT  64.224 28.595 64.248 29.605 ;
     RECT  13.2 29.077 14.904 29.651 ;
     RECT  7.2 27.731 8.424 29.653 ;
     RECT  52.56 29.029 57.576 29.699 ;
     RECT  65.712 28.547 67.608 29.747 ;
     RECT  70.368 29.029 70.392 29.747 ;
     RECT  3.888 28.021 3.96 29.797 ;
     RECT  4.992 29.317 5.736 29.797 ;
     RECT  41.952 29.269 46.872 29.797 ;
     RECT  32.592 28.691 32.712 29.893 ;
     RECT  6.912 29.653 8.424 29.939 ;
     RECT  23.52 29.605 30.696 30.037 ;
     RECT  31.872 29.893 32.712 30.037 ;
     RECT  60.192 28.499 62.112 30.037 ;
     RECT  63.696 29.605 64.248 30.037 ;
     RECT  23.52 30.037 32.712 30.083 ;
     RECT  13.2 29.651 14.856 30.085 ;
     RECT  41.616 29.797 46.872 30.131 ;
     RECT  12.624 30.085 14.856 30.133 ;
     RECT  41.856 30.131 46.872 30.181 ;
     RECT  11.04 29.507 11.352 30.275 ;
     RECT  34.512 28.835 35.304 30.275 ;
     RECT  50.016 29.269 51.576 30.371 ;
     RECT  11.04 30.275 11.064 30.517 ;
     RECT  12.336 30.133 14.856 30.611 ;
     RECT  2.4 27.445 2.856 30.661 ;
     RECT  3.888 29.797 5.736 30.661 ;
     RECT  12.336 30.611 14.808 30.709 ;
     RECT  37.152 27.923 37.848 30.709 ;
     RECT  22.032 29.221 22.056 30.803 ;
     RECT  58.704 30.613 58.728 30.803 ;
     RECT  60.192 30.037 64.248 30.803 ;
     RECT  70.32 30.181 70.344 30.803 ;
     RECT  16.08 28.787 20.424 30.853 ;
     RECT  41.856 30.181 47.208 30.995 ;
     RECT  64.224 30.803 64.248 31.187 ;
     RECT  50.064 30.371 51.576 31.189 ;
     RECT  52.56 29.699 57.432 31.189 ;
     RECT  9.936 29.507 9.96 31.237 ;
     RECT  10.992 30.517 11.064 31.237 ;
     RECT  16.08 30.853 20.76 31.237 ;
     RECT  34.512 30.275 35.112 31.237 ;
     RECT  48.576 28.357 48.6 31.379 ;
     RECT  68.928 27.395 68.952 31.379 ;
     RECT  50.064 31.189 57.432 31.381 ;
     RECT  6.912 29.939 8.328 31.427 ;
     RECT  12.192 30.709 14.808 31.427 ;
     RECT  15.84 31.237 20.76 31.475 ;
     RECT  2.4 30.661 5.736 31.477 ;
     RECT  6.912 31.427 8.28 31.477 ;
     RECT  49.632 31.381 57.432 31.477 ;
     RECT  9.936 31.237 11.064 31.525 ;
     RECT  12.192 31.427 14.76 31.525 ;
     RECT  15.84 31.475 19.032 31.667 ;
     RECT  22.512 31.141 22.536 31.669 ;
     RECT  23.52 30.083 31.416 31.669 ;
     RECT  41.952 30.995 47.208 31.765 ;
     RECT  32.448 30.083 32.712 31.813 ;
     RECT  9.936 31.525 14.76 31.859 ;
     RECT  36.672 30.709 37.848 31.861 ;
     RECT  16.08 31.667 19.032 31.907 ;
     RECT  22.512 31.669 31.416 31.907 ;
     RECT  36.672 31.861 38.28 31.909 ;
     RECT  39.36 29.365 40.512 31.909 ;
     RECT  2.4 31.477 8.28 31.955 ;
     RECT  49.008 31.477 57.432 31.955 ;
     RECT  41.952 31.765 47.496 32.051 ;
     RECT  55.056 31.955 57.432 32.051 ;
     RECT  34.512 31.237 35.304 32.053 ;
     RECT  55.248 32.051 57.432 32.197 ;
     RECT  2.4 31.955 6.552 32.243 ;
     RECT  42 32.051 47.496 32.243 ;
     RECT  20.016 31.475 20.76 32.291 ;
     RECT  55.248 32.197 57.576 32.291 ;
     RECT  20.016 32.291 20.424 32.339 ;
     RECT  32.448 31.813 32.904 32.437 ;
     RECT  34.464 32.053 35.304 32.437 ;
     RECT  60.192 30.803 63.048 32.437 ;
     RECT  10.032 31.859 14.76 32.533 ;
     RECT  17.28 31.907 19.032 32.773 ;
     RECT  23.376 31.907 31.416 32.773 ;
     RECT  32.448 32.437 35.304 32.773 ;
     RECT  23.376 32.773 35.304 32.965 ;
     RECT  44.208 32.243 47.496 32.965 ;
     RECT  49.008 31.955 53.64 32.965 ;
     RECT  22.272 32.821 22.296 33.013 ;
     RECT  56.4 32.291 57.576 33.013 ;
     RECT  58.704 32.293 58.728 33.013 ;
     RECT  10.032 32.533 14.952 33.107 ;
     RECT  44.208 32.965 53.64 33.299 ;
     RECT  60.096 32.437 63.048 33.347 ;
     RECT  36.672 31.909 40.512 33.443 ;
     RECT  7.632 31.955 8.28 33.541 ;
     RECT  10.032 33.107 11.064 33.541 ;
     RECT  2.4 32.243 3.912 33.587 ;
     RECT  36.672 33.443 37.848 33.635 ;
     RECT  71.184 32.485 71.208 33.635 ;
     RECT  16.08 31.907 16.296 33.781 ;
     RECT  69.504 33.349 69.528 33.781 ;
     RECT  69.312 33.781 69.528 33.827 ;
     RECT  49.488 33.299 53.64 33.973 ;
     RECT  55.248 32.291 55.272 33.973 ;
     RECT  23.376 32.965 35.688 34.067 ;
     RECT  64.464 33.589 64.584 34.211 ;
     RECT  21.648 33.013 22.296 34.259 ;
     RECT  7.632 33.541 11.064 34.355 ;
     RECT  42 32.243 43.08 34.355 ;
     RECT  44.208 33.299 48.12 34.693 ;
     RECT  49.488 33.973 55.272 34.693 ;
     RECT  9.888 34.355 11.064 34.741 ;
     RECT  12.192 33.107 14.952 34.741 ;
     RECT  17.28 32.773 19.368 34.741 ;
     RECT  20.352 32.339 20.424 34.741 ;
     RECT  38.928 33.443 40.512 34.741 ;
     RECT  72.6 23.555 72.912 34.741 ;
     RECT  60.192 33.347 63.048 34.789 ;
     RECT  44.208 34.693 55.272 34.835 ;
     RECT  60.192 34.789 63.144 34.885 ;
     RECT  64.464 34.211 64.536 34.885 ;
     RECT  60.192 34.885 64.536 34.931 ;
     RECT  9.888 34.741 14.952 35.027 ;
     RECT  23.376 34.067 35.448 35.123 ;
     RECT  37.104 33.635 37.848 35.123 ;
     RECT  7.632 34.355 8.376 35.317 ;
     RECT  9.888 35.027 12.216 35.317 ;
     RECT  7.632 35.317 8.76 35.363 ;
     RECT  23.376 35.123 35.208 35.363 ;
     RECT  9.792 35.317 12.216 35.459 ;
     RECT  44.208 34.835 54.504 35.461 ;
     RECT  15.936 33.781 16.296 35.557 ;
     RECT  17.28 34.741 20.424 35.557 ;
     RECT  22.272 34.259 22.296 35.797 ;
     RECT  42.048 34.355 43.08 35.797 ;
     RECT  44.112 35.461 54.504 35.797 ;
     RECT  21.888 35.797 22.296 35.843 ;
     RECT  23.376 35.363 32.712 35.893 ;
     RECT  42.048 35.797 54.552 35.893 ;
     RECT  9.792 35.459 10.824 35.939 ;
     RECT  13.2 35.027 14.952 35.939 ;
     RECT  21.888 35.843 21.912 35.939 ;
     RECT  38.928 34.741 40.776 35.939 ;
     RECT  60.192 34.931 64.488 35.939 ;
     RECT  69.312 33.827 69.336 35.939 ;
     RECT  42.048 35.893 54.6 36.083 ;
     RECT  11.952 35.459 12.216 36.131 ;
     RECT  12.192 36.131 12.216 36.325 ;
     RECT  13.2 35.939 14.76 36.325 ;
     RECT  64.368 35.939 64.488 36.371 ;
     RECT  42.48 36.083 54.6 36.469 ;
     RECT  23.232 35.893 32.712 36.515 ;
     RECT  42.48 36.469 54.648 36.515 ;
     RECT  70.896 34.453 70.92 36.515 ;
     RECT  72.48 34.741 72.912 36.515 ;
     RECT  7.8 35.363 8.76 36.659 ;
     RECT  39.072 35.939 40.776 36.709 ;
     RECT  44.112 36.515 54.648 36.755 ;
     RECT  12.192 36.325 14.76 36.803 ;
     RECT  42.48 36.515 42.648 36.803 ;
     RECT  23.376 36.515 32.712 37.043 ;
     RECT  15.936 35.557 20.424 37.091 ;
     RECT  42.48 36.803 42.504 37.091 ;
     RECT  68.928 36.421 68.952 37.091 ;
     RECT  60.192 35.939 63.144 37.187 ;
     RECT  44.16 36.755 54.648 37.283 ;
     RECT  56.4 33.013 58.728 37.333 ;
     RECT  34.464 35.363 35.208 37.379 ;
     RECT  55.872 37.333 58.728 37.525 ;
     RECT  60.192 37.187 63.048 37.525 ;
     RECT  37.248 35.123 37.848 37.573 ;
     RECT  65.856 29.747 67.608 37.573 ;
     RECT  44.928 37.283 54.648 37.621 ;
     RECT  55.872 37.525 63.048 37.621 ;
     RECT  4.896 32.243 6.552 37.715 ;
     RECT  44.928 37.621 63.048 37.763 ;
     RECT  18.6 37.091 20.424 37.811 ;
     RECT  20.064 37.811 20.424 37.859 ;
     RECT  37.152 37.573 37.848 37.909 ;
     RECT  72.6 36.515 72.912 38.053 ;
     RECT  27.312 37.043 32.712 38.101 ;
     RECT  2.4 33.587 3.864 38.149 ;
     RECT  4.896 37.715 4.92 38.149 ;
     RECT  6.288 37.715 6.552 38.149 ;
     RECT  7.8 36.659 8.328 38.149 ;
     RECT  9.792 35.939 10.008 38.149 ;
     RECT  23.376 37.043 25.944 38.245 ;
     RECT  27.312 38.101 33.048 38.245 ;
     RECT  23.376 38.245 33.048 38.291 ;
     RECT  44.928 37.763 48.696 38.291 ;
     RECT  15.936 37.091 17.304 38.389 ;
     RECT  18.6 37.811 18.912 38.389 ;
     RECT  36.72 37.909 37.848 38.389 ;
     RECT  39.072 36.709 41.016 38.389 ;
     RECT  36.72 38.389 41.016 38.533 ;
     RECT  23.376 38.291 26.808 38.579 ;
     RECT  12.192 36.803 14.664 38.581 ;
     RECT  15.936 38.389 18.912 38.627 ;
     RECT  64.368 36.371 64.392 38.629 ;
     RECT  65.376 37.573 67.608 38.629 ;
     RECT  9.504 38.149 10.008 38.723 ;
     RECT  68.64 37.093 68.664 38.963 ;
     RECT  9.504 38.723 9.816 39.011 ;
     RECT  49.92 37.763 63.048 39.011 ;
     RECT  12.192 38.581 14.712 39.059 ;
     RECT  71.856 38.053 72.912 39.107 ;
     RECT  6.288 38.149 8.328 39.205 ;
     RECT  49.92 39.011 55.032 39.251 ;
     RECT  17.28 38.627 18.912 39.299 ;
     RECT  36.72 38.533 41.688 39.301 ;
     RECT  36.72 39.301 42.12 39.349 ;
     RECT  45.456 38.291 48.696 39.491 ;
     RECT  13.2 39.059 14.712 39.541 ;
     RECT  15.936 38.627 16.248 39.541 ;
     RECT  28.224 38.291 33.048 39.587 ;
     RECT  2.4 38.149 4.92 39.589 ;
     RECT  6.288 39.205 8.712 39.589 ;
     RECT  20.064 37.859 20.088 39.637 ;
     RECT  21.744 38.485 21.768 39.637 ;
     RECT  23.376 38.579 25.944 39.781 ;
     RECT  36.672 39.349 42.12 39.781 ;
     RECT  20.064 39.637 21.768 39.875 ;
     RECT  64.368 38.629 67.608 39.877 ;
     RECT  13.2 39.541 16.248 39.923 ;
     RECT  56.304 39.011 63.048 39.923 ;
     RECT  64.368 39.877 68.088 39.971 ;
     RECT  28.224 39.587 32.424 40.021 ;
     RECT  45.504 39.491 48.696 40.069 ;
     RECT  49.92 39.251 53.4 40.069 ;
     RECT  54.528 39.251 55.032 40.451 ;
     RECT  70.704 39.829 70.728 40.499 ;
     RECT  17.952 39.299 18.912 40.693 ;
     RECT  45.504 40.069 53.4 40.693 ;
     RECT  12.192 39.059 12.216 40.837 ;
     RECT  13.2 39.923 15.96 40.837 ;
     RECT  23.376 39.781 25.992 40.885 ;
     RECT  27.264 40.021 32.424 40.885 ;
     RECT  56.304 39.923 58.728 40.933 ;
     RECT  2.4 39.589 8.712 40.979 ;
     RECT  54.624 40.451 55.032 40.981 ;
     RECT  56.256 40.933 58.728 40.981 ;
     RECT  64.512 39.971 68.088 41.075 ;
     RECT  20.064 39.875 21 41.173 ;
     RECT  36.48 39.781 42.12 41.411 ;
     RECT  64.512 41.075 67.608 41.413 ;
     RECT  54.624 40.981 58.728 41.557 ;
     RECT  60.192 39.923 63.048 41.557 ;
     RECT  19.968 41.173 21 41.749 ;
     RECT  43.44 40.405 43.464 41.749 ;
     RECT  43.44 41.749 43.896 41.795 ;
     RECT  12.192 40.837 15.96 41.939 ;
     RECT  43.872 41.795 43.896 41.987 ;
     RECT  45.312 40.693 53.4 42.035 ;
     RECT  54.624 41.557 63.048 42.035 ;
     RECT  9.792 39.011 9.816 42.133 ;
     RECT  42.096 41.411 42.12 42.133 ;
     RECT  45.36 42.035 53.4 42.133 ;
     RECT  54.624 42.035 55.08 42.133 ;
     RECT  64.224 41.413 67.608 42.227 ;
     RECT  2.4 40.979 4.92 42.275 ;
     RECT  6.288 40.979 8.712 42.323 ;
     RECT  19.968 41.749 21.144 42.563 ;
     RECT  69.312 40.405 69.336 42.709 ;
     RECT  6.288 42.323 6.552 42.803 ;
     RECT  64.224 42.227 65.88 42.803 ;
     RECT  36.48 41.411 41.064 42.805 ;
     RECT  9.696 42.133 9.816 42.851 ;
     RECT  45.36 42.133 55.08 42.995 ;
     RECT  12.192 41.939 15.672 43.093 ;
     RECT  12.192 43.093 16.248 43.237 ;
     RECT  17.808 40.693 18.912 43.237 ;
     RECT  20.064 42.563 21.144 43.283 ;
     RECT  45.36 42.995 53.4 43.285 ;
     RECT  72.6 39.107 72.912 43.285 ;
     RECT  23.376 40.885 32.424 43.523 ;
     RECT  2.4 42.275 4.776 43.619 ;
     RECT  42.096 42.133 42.744 43.813 ;
     RECT  64.224 42.803 64.584 43.861 ;
     RECT  65.856 42.803 65.88 43.861 ;
     RECT  36.48 42.805 41.112 43.907 ;
     RECT  71.808 43.285 72.912 43.907 ;
     RECT  20.064 43.283 20.904 44.099 ;
     RECT  54.672 42.995 55.08 44.101 ;
     RECT  23.376 43.523 26.952 44.149 ;
     RECT  7.8 42.323 8.712 44.341 ;
     RECT  56.256 42.035 63.048 44.389 ;
     RECT  64.224 43.861 65.88 44.437 ;
     RECT  12.192 43.237 18.912 44.483 ;
     RECT  6.288 42.803 6.312 44.723 ;
     RECT  42.096 43.813 42.84 44.725 ;
     RECT  44.736 43.285 53.4 44.771 ;
     RECT  42.096 44.725 43.224 44.965 ;
     RECT  66.96 42.227 67.608 44.965 ;
     RECT  45.408 44.771 53.4 45.011 ;
     RECT  69.312 42.709 69.912 45.013 ;
     RECT  7.8 44.341 8.808 45.059 ;
     RECT  45.6 45.011 53.4 45.059 ;
     RECT  54.624 44.101 55.08 45.059 ;
     RECT  64.08 44.437 65.88 45.059 ;
     RECT  36.72 43.907 41.112 45.157 ;
     RECT  42.096 44.965 43.8 45.157 ;
     RECT  2.4 43.619 3.672 45.299 ;
     RECT  2.4 45.299 3.288 45.395 ;
     RECT  28.128 43.523 32.424 45.395 ;
     RECT  69.312 45.013 70.008 45.541 ;
     RECT  52.704 45.059 53.4 45.683 ;
     RECT  34.464 37.379 35.112 45.733 ;
     RECT  56.208 44.389 63.048 45.733 ;
     RECT  20.064 44.099 20.088 45.781 ;
     RECT  20.064 45.781 20.232 45.827 ;
     RECT  69.216 45.541 70.008 45.971 ;
     RECT  34.464 45.733 35.352 46.261 ;
     RECT  36.72 45.157 43.8 46.261 ;
     RECT  45.6 45.059 51.576 46.307 ;
     RECT  21.312 45.445 21.336 46.499 ;
     RECT  65.04 45.059 65.88 46.645 ;
     RECT  66.96 44.965 67.656 46.645 ;
     RECT  45.6 46.307 49.944 46.787 ;
     RECT  2.4 45.395 2.712 46.885 ;
     RECT  34.464 46.261 44.472 47.029 ;
     RECT  45.6 46.787 46.776 47.029 ;
     RECT  56.112 45.733 63.048 47.221 ;
     RECT  56.112 47.221 63.24 47.267 ;
     RECT  54.672 45.059 55.08 47.269 ;
     RECT  56.112 47.267 58.776 47.269 ;
     RECT  52.704 45.683 52.872 47.317 ;
     RECT  54.672 47.269 58.776 47.317 ;
     RECT  12.192 44.483 16.248 47.363 ;
     RECT  65.04 46.645 67.656 47.363 ;
     RECT  34.464 47.029 46.776 47.411 ;
     RECT  69.216 45.971 69.336 47.413 ;
     RECT  34.464 47.411 44.472 47.555 ;
     RECT  23.328 44.149 26.952 47.605 ;
     RECT  28.464 45.395 32.424 47.651 ;
     RECT  51 46.307 51.576 47.653 ;
     RECT  52.704 47.317 58.776 47.653 ;
     RECT  47.904 46.787 49.944 47.747 ;
     RECT  20.208 45.827 20.232 47.749 ;
     RECT  69.216 47.413 70.152 47.845 ;
     RECT  51 47.653 58.776 47.987 ;
     RECT  65.856 47.363 67.656 48.085 ;
     RECT  52.896 47.987 58.776 48.131 ;
     RECT  12.192 47.363 14.616 48.179 ;
     RECT  28.704 47.651 32.424 48.229 ;
     RECT  56.064 48.131 58.776 48.229 ;
     RECT  17.76 44.483 18.912 48.325 ;
     RECT  12.288 48.179 14.616 48.373 ;
     RECT  15.648 47.363 16.248 48.373 ;
     RECT  56.064 48.229 58.872 48.421 ;
     RECT  20.208 47.749 21.144 48.515 ;
     RECT  23.328 47.605 27.24 48.515 ;
     RECT  60.048 47.267 63.24 48.565 ;
     RECT  48 47.747 49.944 48.853 ;
     RECT  51 47.987 51.576 48.853 ;
     RECT  34.464 47.555 43.896 48.947 ;
     RECT  27.216 48.515 27.24 48.949 ;
     RECT  28.704 48.229 33.048 48.949 ;
     RECT  65.856 48.085 67.944 48.949 ;
     RECT  45.6 47.411 46.776 48.997 ;
     RECT  12.288 48.373 16.248 49.091 ;
     RECT  69.072 47.845 70.152 49.091 ;
     RECT  52.896 48.131 55.08 49.093 ;
     RECT  56.064 48.421 58.92 49.093 ;
     RECT  64.944 48.949 67.944 49.139 ;
     RECT  27.216 48.949 33.048 49.235 ;
     RECT  34.464 48.947 41.016 49.235 ;
     RECT  27.216 49.235 32.424 49.283 ;
     RECT  34.8 49.235 41.016 49.331 ;
     RECT  45.6 48.997 46.92 49.475 ;
     RECT  60.048 48.565 63.912 49.477 ;
     RECT  52.896 49.093 58.92 49.525 ;
     RECT  17.472 48.325 18.912 49.619 ;
     RECT  27.216 49.283 30.6 49.859 ;
     RECT  9.792 42.851 9.816 49.909 ;
     RECT  28.704 49.859 30.6 50.051 ;
     RECT  4.752 43.619 4.776 50.053 ;
     RECT  23.328 48.515 25.992 50.101 ;
     RECT  9.168 49.909 9.816 50.147 ;
     RECT  33.648 49.285 33.672 50.195 ;
     RECT  52.896 49.525 58.968 50.195 ;
     RECT  48 48.853 51.576 50.293 ;
     RECT  2.304 46.885 2.712 50.339 ;
     RECT  4.752 50.053 5.112 50.341 ;
     RECT  22.512 50.101 25.992 50.341 ;
     RECT  27.216 49.859 27.624 50.341 ;
     RECT  52.896 50.195 55.128 50.437 ;
     RECT  22.512 50.341 27.624 50.579 ;
     RECT  34.8 49.331 40.512 50.581 ;
     RECT  18.336 49.619 18.912 50.629 ;
     RECT  65.856 49.139 67.944 50.677 ;
     RECT  65.856 50.677 68.04 50.723 ;
     RECT  22.512 50.579 25.992 50.771 ;
     RECT  69.072 49.091 69.528 50.869 ;
     RECT  69.072 50.869 70.248 50.915 ;
     RECT  71.28 44.197 71.304 51.059 ;
     RECT  34.8 50.581 40.728 51.109 ;
     RECT  52.848 50.437 55.128 51.157 ;
     RECT  56.112 50.195 58.968 51.157 ;
     RECT  31.584 49.283 32.424 51.203 ;
     RECT  34.224 51.109 40.728 51.205 ;
     RECT  42.096 48.947 43.896 51.205 ;
     RECT  48 50.293 51.768 51.253 ;
     RECT  28.704 50.051 30.504 51.347 ;
     RECT  34.032 51.205 43.896 51.491 ;
     RECT  31.68 51.203 32.424 51.493 ;
     RECT  65.952 50.723 68.04 51.541 ;
     RECT  69.072 50.915 69.096 51.541 ;
     RECT  48 51.253 51.816 51.685 ;
     RECT  60.048 49.477 64.824 51.685 ;
     RECT  65.952 51.541 69.096 51.685 ;
     RECT  27.216 50.579 27.624 51.781 ;
     RECT  28.704 51.347 30.216 51.781 ;
     RECT  47.472 51.685 51.816 51.829 ;
     RECT  52.848 51.157 58.968 51.829 ;
     RECT  22.608 50.771 25.992 52.067 ;
     RECT  45.6 49.475 46.392 52.213 ;
     RECT  47.472 51.829 58.968 52.213 ;
     RECT  45.6 52.213 58.968 52.355 ;
     RECT  25.584 52.067 25.992 52.453 ;
     RECT  27.216 51.781 30.216 52.453 ;
     RECT  20.208 48.515 20.232 52.499 ;
     RECT  45.6 52.355 48.36 52.499 ;
     RECT  70.128 50.915 70.248 52.499 ;
     RECT  49.344 52.355 58.968 52.501 ;
     RECT  60.048 51.685 69.096 52.501 ;
     RECT  49.344 52.501 69.096 52.547 ;
     RECT  70.224 52.499 70.248 52.547 ;
     RECT  49.344 52.547 65.976 52.595 ;
     RECT  52.848 52.595 65.976 52.643 ;
     RECT  34.032 51.491 43.224 52.691 ;
     RECT  34.032 52.691 39.096 52.931 ;
     RECT  25.584 52.453 30.216 52.979 ;
     RECT  21.36 52.453 21.384 52.981 ;
     RECT  40.2 52.691 43.224 53.365 ;
     RECT  44.496 52.021 44.52 53.365 ;
     RECT  34.032 52.931 38.856 53.459 ;
     RECT  40.2 53.365 44.52 53.557 ;
     RECT  45.6 52.499 46.344 53.557 ;
     RECT  52.896 52.643 65.976 53.557 ;
     RECT  66.96 52.547 69.096 53.557 ;
     RECT  71.376 52.693 71.4 53.557 ;
     RECT  72.6 43.907 72.912 53.557 ;
     RECT  49.344 52.595 51.816 53.603 ;
     RECT  52.896 53.557 69.096 53.603 ;
     RECT  12.336 49.091 16.248 53.795 ;
     RECT  49.344 53.603 51.432 53.843 ;
     RECT  15.888 53.795 16.248 53.941 ;
     RECT  20.544 52.981 21.384 54.083 ;
     RECT  52.896 53.603 68.376 54.083 ;
     RECT  7.8 45.059 8.112 54.085 ;
     RECT  9.168 50.147 9.192 54.085 ;
     RECT  31.68 51.493 32.904 54.085 ;
     RECT  4.752 50.341 5.832 54.179 ;
     RECT  12.336 53.795 14.808 54.179 ;
     RECT  25.584 52.979 27.912 54.179 ;
     RECT  4.752 54.179 5.112 54.517 ;
     RECT  52.896 54.083 67.848 54.563 ;
     RECT  47.328 52.499 48.36 54.661 ;
     RECT  49.344 53.843 51.312 54.661 ;
     RECT  70.32 52.981 70.344 54.661 ;
     RECT  71.376 53.557 72.912 54.661 ;
     RECT  70.32 54.661 72.912 54.707 ;
     RECT  34.56 53.459 38.856 54.709 ;
     RECT  34.464 54.709 38.856 54.755 ;
     RECT  31.68 54.085 33 54.803 ;
     RECT  7.056 54.085 8.112 54.851 ;
     RECT  15.888 53.941 17.16 54.899 ;
     RECT  70.32 54.707 70.584 54.899 ;
     RECT  22.608 52.067 24.456 54.997 ;
     RECT  36.864 54.755 38.856 55.139 ;
     RECT  21.36 54.083 21.384 55.189 ;
     RECT  22.608 54.997 24.504 55.189 ;
     RECT  34.464 54.755 35.352 55.237 ;
     RECT  40.2 53.557 46.344 55.237 ;
     RECT  47.328 54.661 51.312 55.237 ;
     RECT  4.176 54.517 5.112 55.283 ;
     RECT  14.784 54.179 14.808 55.331 ;
     RECT  40.2 55.237 51.312 55.331 ;
     RECT  29.232 52.979 30.216 55.381 ;
     RECT  31.68 54.803 32.904 55.381 ;
     RECT  9.12 54.085 9.192 55.427 ;
     RECT  29.232 55.381 32.904 55.523 ;
     RECT  25.584 54.179 27.24 55.669 ;
     RECT  31.344 55.523 32.904 55.715 ;
     RECT  40.2 55.331 46.776 55.861 ;
     RECT  33.888 55.237 35.352 55.907 ;
     RECT  36.864 55.139 38.472 55.907 ;
     RECT  21.36 55.189 24.504 55.957 ;
     RECT  20.832 55.957 24.504 56.149 ;
     RECT  47.904 55.331 51.312 56.195 ;
     RECT  52.896 54.563 67.512 56.245 ;
     RECT  68.64 55.813 68.664 56.245 ;
     RECT  15.888 54.899 16.248 56.291 ;
     RECT  9.12 55.427 9.144 56.339 ;
     RECT  12.336 54.179 13.608 56.387 ;
     RECT  7.8 54.851 8.112 56.389 ;
     RECT  39.456 55.861 46.776 56.389 ;
     RECT  4.176 55.283 4.2 56.483 ;
     RECT  71.664 54.707 72.912 56.483 ;
     RECT  25.584 55.669 27.672 56.531 ;
     RECT  39.456 56.389 47.064 56.531 ;
     RECT  15.888 56.291 16.008 56.579 ;
     RECT  20.496 56.149 24.504 56.725 ;
     RECT  52.896 56.245 68.664 56.771 ;
     RECT  2.4 50.339 2.712 56.917 ;
     RECT  29.232 55.523 30.216 57.011 ;
     RECT  18.24 50.629 18.912 57.013 ;
     RECT  5.52 56.389 5.544 57.059 ;
     RECT  20.496 56.725 24.552 57.059 ;
     RECT  25.584 56.531 27.384 57.059 ;
     RECT  52.896 56.771 68.472 57.059 ;
     RECT  71.904 56.483 72.912 57.059 ;
     RECT  29.232 57.011 30.024 57.061 ;
     RECT  34.56 55.907 35.352 57.109 ;
     RECT  39.456 56.531 43.512 57.155 ;
     RECT  31.344 55.715 32.424 57.203 ;
     RECT  42.048 57.155 43.512 57.203 ;
     RECT  44.496 56.531 47.064 57.251 ;
     RECT  34.56 57.109 35.4 57.301 ;
     RECT  52.896 57.059 67.512 57.301 ;
     RECT  33.84 57.301 35.4 57.395 ;
     RECT  36.864 55.907 37.8 57.445 ;
     RECT  39.456 57.155 41.016 57.445 ;
     RECT  70.56 54.899 70.584 57.445 ;
     RECT  32.4 57.203 32.424 57.541 ;
     RECT  21.072 57.059 24.552 57.587 ;
     RECT  2.4 56.917 3.432 57.685 ;
     RECT  42.384 57.203 43.512 57.779 ;
     RECT  2.304 57.685 3.432 57.875 ;
     RECT  31.344 57.203 31.368 57.971 ;
     RECT  32.4 57.541 32.712 58.021 ;
     RECT  33.84 57.395 35.352 58.021 ;
     RECT  42.528 57.779 43.512 58.021 ;
     RECT  7.8 56.389 9.096 58.115 ;
     RECT  29.04 57.061 30.024 58.117 ;
     RECT  70.56 57.445 70.968 58.117 ;
     RECT  72.48 57.059 72.912 58.117 ;
     RECT  18.24 57.013 19.272 58.163 ;
     RECT  32.4 58.021 35.352 58.211 ;
     RECT  52.704 57.301 67.512 58.355 ;
     RECT  18.24 58.163 18.912 58.453 ;
     RECT  36.864 57.445 38.328 58.547 ;
     RECT  0.144 57.349 0.168 58.595 ;
     RECT  2.4 57.875 3.432 58.645 ;
     RECT  15.744 57.445 15.768 58.645 ;
     RECT  21.312 57.587 24.552 58.691 ;
     RECT  2.4 58.645 3.96 58.787 ;
     RECT  2.4 58.787 3.432 58.883 ;
     RECT  32.4 58.211 35.304 58.885 ;
     RECT  70.56 58.117 72.912 59.077 ;
     RECT  12.336 56.387 13.512 59.221 ;
     RECT  31.968 58.885 35.304 59.221 ;
     RECT  44.544 57.251 47.064 59.267 ;
     RECT  29.04 58.117 30.696 59.269 ;
     RECT  39.36 57.445 41.016 59.315 ;
     RECT  39.6 59.315 41.016 59.699 ;
     RECT  31.968 59.221 35.592 59.749 ;
     RECT  15.744 58.645 16.392 59.797 ;
     RECT  28.992 59.269 30.696 59.797 ;
     RECT  31.872 59.749 35.592 59.797 ;
     RECT  28.992 59.797 35.592 59.939 ;
     RECT  2.4 58.883 2.808 60.035 ;
     RECT  40.2 59.699 41.016 60.133 ;
     RECT  64.416 58.355 67.512 60.179 ;
     RECT  15.744 59.797 16.44 60.277 ;
     RECT  42.528 58.021 43.56 60.323 ;
     RECT  45.216 59.267 47.064 60.325 ;
     RECT  48.144 56.195 51.312 60.325 ;
     RECT  6.432 59.221 6.456 60.373 ;
     RECT  12.336 59.221 14.472 60.373 ;
     RECT  12 60.373 14.472 60.467 ;
     RECT  37.776 58.547 38.328 60.467 ;
     RECT  42.528 60.323 43.368 60.467 ;
     RECT  70.272 59.077 72.912 60.467 ;
     RECT  5.664 60.373 6.456 60.563 ;
     RECT  52.704 58.355 63.384 60.611 ;
     RECT  15.456 60.277 16.44 60.613 ;
     RECT  17.856 58.453 18.912 60.613 ;
     RECT  40.2 60.133 41.16 60.661 ;
     RECT  15.408 60.613 16.44 60.803 ;
     RECT  64.416 60.179 65.544 60.853 ;
     RECT  70.848 60.467 72.912 60.947 ;
     RECT  20.256 60.373 20.28 61.043 ;
     RECT  66.672 60.179 67.512 61.043 ;
     RECT  10.032 60.277 10.056 61.139 ;
     RECT  5.664 60.563 5.688 61.331 ;
     RECT  15.408 60.803 16.392 61.379 ;
     RECT  27.888 59.749 27.912 61.379 ;
     RECT  67.056 61.043 67.512 61.381 ;
     RECT  45.216 60.325 51.312 61.475 ;
     RECT  15.408 61.379 15.48 61.619 ;
     RECT  21.312 58.691 24.456 61.669 ;
     RECT  52.704 60.611 55.08 61.765 ;
     RECT  56.064 60.611 62.112 61.765 ;
     RECT  37.776 60.467 38.184 61.909 ;
     RECT  28.992 59.939 30.312 62.053 ;
     RECT  31.296 59.939 35.592 62.053 ;
     RECT  28.992 62.053 35.592 62.099 ;
     RECT  25.584 57.059 26.904 62.101 ;
     RECT  17.568 60.613 18.912 62.149 ;
     RECT  69.264 58.645 69.288 62.195 ;
     RECT  52.704 61.765 62.112 62.243 ;
     RECT  52.704 62.243 60.744 62.291 ;
     RECT  2.4 60.035 2.712 62.341 ;
     RECT  12 60.467 13.512 62.435 ;
     RECT  7.8 58.115 8.112 62.533 ;
     RECT  28.992 62.099 31.032 62.581 ;
     RECT  21.264 61.669 24.456 62.629 ;
     RECT  17.568 62.149 19.176 62.675 ;
     RECT  72.336 60.947 72.912 62.675 ;
     RECT  63.36 60.611 63.384 62.677 ;
     RECT  64.368 60.853 65.544 62.677 ;
     RECT  25.584 62.101 27.384 62.723 ;
     RECT  25.584 62.723 26.904 62.771 ;
     RECT  45.6 61.475 51.312 62.771 ;
     RECT  52.848 62.291 60.744 62.771 ;
     RECT  37.776 61.909 38.328 62.819 ;
     RECT  70.848 60.947 71.304 62.867 ;
     RECT  67.056 61.381 67.992 63.011 ;
     RECT  63.36 62.677 65.544 63.205 ;
     RECT  7.8 62.533 8.232 63.299 ;
     RECT  37.824 62.819 38.328 63.299 ;
     RECT  42.528 60.467 42.792 63.299 ;
     RECT  21.264 62.629 24.504 63.493 ;
     RECT  28.464 62.581 31.032 63.539 ;
     RECT  32.688 62.099 35.592 63.539 ;
     RECT  63.36 63.205 66.072 63.779 ;
     RECT  26.352 62.771 26.904 63.781 ;
     RECT  52.896 62.771 60.744 63.827 ;
     RECT  15.408 61.619 15.432 63.829 ;
     RECT  37.824 63.299 37.848 63.875 ;
     RECT  2.4 62.341 3.432 63.971 ;
     RECT  70.848 62.867 70.872 64.019 ;
     RECT  15.408 63.829 15.48 64.069 ;
     RECT  45.6 62.771 46.536 64.163 ;
     RECT  48.048 62.771 51.312 64.259 ;
     RECT  21.264 63.493 25.128 64.307 ;
     RECT  23.184 64.307 25.128 64.357 ;
     RECT  26.208 63.781 26.904 64.357 ;
     RECT  40.2 60.661 41.496 64.357 ;
     RECT  15.312 64.069 15.48 64.403 ;
     RECT  39.696 64.357 41.496 64.405 ;
     RECT  72.432 62.675 72.912 64.405 ;
     RECT  70.656 64.117 70.68 64.499 ;
     RECT  52.992 63.827 60.744 64.643 ;
     RECT  21.264 64.307 21.672 64.693 ;
     RECT  29.4 63.539 31.032 64.693 ;
     RECT  63.36 63.779 63.528 64.739 ;
     RECT  29.4 64.693 31.656 64.885 ;
     RECT  37.296 64.741 37.32 64.885 ;
     RECT  34.128 63.539 35.592 64.931 ;
     RECT  15.312 64.403 15.432 64.933 ;
     RECT  17.856 62.675 19.176 64.933 ;
     RECT  32.688 63.539 33.048 64.933 ;
     RECT  34.128 64.931 35.352 64.933 ;
     RECT  39.024 64.405 41.496 64.933 ;
     RECT  48.144 64.259 51.312 64.933 ;
     RECT  32.688 64.933 35.352 64.979 ;
     RECT  48.144 64.933 51.96 65.027 ;
     RECT  67.056 63.011 67.512 65.027 ;
     RECT  38.688 64.933 41.496 65.173 ;
     RECT  42.528 63.299 42.552 65.173 ;
     RECT  50.304 65.027 51.96 65.411 ;
     RECT  12.336 62.435 13.512 65.509 ;
     RECT  29.28 64.885 31.656 65.509 ;
     RECT  63.504 64.739 63.528 65.509 ;
     RECT  37.056 64.885 37.32 65.653 ;
     RECT  37.056 65.653 37.368 65.699 ;
     RECT  50.352 65.411 51.96 65.699 ;
     RECT  2.4 63.971 2.712 65.749 ;
     RECT  20.544 64.693 21.672 65.749 ;
     RECT  23.184 64.357 26.904 65.749 ;
     RECT  45.6 64.163 46.344 65.795 ;
     RECT  15.264 64.933 15.432 65.797 ;
     RECT  44.064 64.405 44.088 65.939 ;
     RECT  32.688 64.979 35.304 66.085 ;
     RECT  20.544 65.749 26.904 66.131 ;
     RECT  32.688 66.085 36.216 66.131 ;
     RECT  17.856 64.933 19.56 66.133 ;
     RECT  15.264 65.797 16.008 66.229 ;
     RECT  7.8 63.299 8.112 66.325 ;
     RECT  53.136 64.643 60.744 66.325 ;
     RECT  63.504 65.509 63.624 66.421 ;
     RECT  64.656 63.779 66.072 66.421 ;
     RECT  53.136 66.325 60.792 66.467 ;
     RECT  53.136 66.467 60.072 66.515 ;
     RECT  28.56 65.509 31.656 66.613 ;
     RECT  11.568 65.509 13.512 66.659 ;
     RECT  17.712 66.133 19.56 66.755 ;
     RECT  21.312 66.131 26.904 66.755 ;
     RECT  28.368 66.613 31.656 66.755 ;
     RECT  37.2 65.699 37.368 66.755 ;
     RECT  48.144 65.027 48.984 66.755 ;
     RECT  17.712 66.755 19.176 66.805 ;
     RECT  45.6 65.795 46.248 66.805 ;
     RECT  34.128 66.131 36.216 66.851 ;
     RECT  53.52 66.515 60.072 67.091 ;
     RECT  10.512 63.781 10.536 67.093 ;
     RECT  10.272 67.093 10.536 67.139 ;
     RECT  48.144 66.755 48.696 67.141 ;
     RECT  63.504 66.421 66.072 67.189 ;
     RECT  67.2 65.027 67.512 67.237 ;
     RECT  68.976 67.045 69 67.237 ;
     RECT  2.4 65.749 3.528 67.283 ;
     RECT  21.312 66.755 26.76 67.283 ;
     RECT  21.312 67.283 25.128 67.331 ;
     RECT  34.8 66.851 36.216 67.331 ;
     RECT  50.352 65.699 51.312 67.379 ;
     RECT  15.024 66.229 16.008 67.523 ;
     RECT  38.688 65.173 42.552 67.619 ;
     RECT  54.192 67.091 60.072 67.669 ;
     RECT  54.192 67.669 60.792 67.859 ;
     RECT  23.184 67.331 25.128 67.907 ;
     RECT  32.688 66.131 33.144 67.907 ;
     RECT  38.688 67.619 41.784 67.907 ;
     RECT  50.736 67.379 51.312 68.099 ;
     RECT  63.264 67.189 66.072 68.149 ;
     RECT  67.2 67.237 69 68.149 ;
     RECT  72.336 64.405 72.912 68.149 ;
     RECT  15.984 67.523 16.008 68.197 ;
     RECT  17.616 66.805 19.176 68.197 ;
     RECT  45.6 66.805 46.296 68.197 ;
     RECT  7.056 66.325 8.112 68.243 ;
     RECT  21.312 67.331 22.2 68.243 ;
     RECT  63.264 68.149 69 68.243 ;
     RECT  68.544 68.243 69 68.245 ;
     RECT  70.128 67.333 70.152 68.245 ;
     RECT  63.264 68.243 67.512 68.291 ;
     RECT  60.432 67.859 60.792 68.341 ;
     RECT  61.8 62.243 62.112 68.341 ;
     RECT  28.368 66.755 30.984 68.389 ;
     RECT  5.136 67.765 5.16 68.435 ;
     RECT  68.544 68.245 70.152 68.435 ;
     RECT  47.76 67.141 48.696 68.483 ;
     RECT  49.68 68.341 49.704 68.485 ;
     RECT  50.784 68.099 51.312 68.629 ;
     RECT  52.752 68.341 52.776 68.629 ;
     RECT  28.368 68.389 31.32 68.675 ;
     RECT  47.76 68.483 48.456 68.675 ;
     RECT  63.6 68.291 67.512 68.675 ;
     RECT  54.192 67.859 59.4 68.677 ;
     RECT  39.216 67.907 41.784 68.771 ;
     RECT  26.448 67.283 26.76 68.821 ;
     RECT  28.368 68.675 29.712 68.821 ;
     RECT  10.272 67.139 10.296 68.867 ;
     RECT  47.76 68.675 47.784 68.867 ;
     RECT  54.144 68.677 59.4 68.915 ;
     RECT  15.984 68.197 19.176 68.917 ;
     RECT  11.28 68.341 11.304 68.965 ;
     RECT  50.784 68.629 52.776 68.965 ;
     RECT  54.144 68.915 59.256 68.965 ;
     RECT  10.848 68.965 11.304 69.011 ;
     RECT  26.448 68.821 29.712 69.011 ;
     RECT  50.784 68.965 59.256 69.011 ;
     RECT  63.6 68.675 64.68 69.155 ;
     RECT  10.848 69.011 10.872 69.203 ;
     RECT  45.312 68.197 46.296 69.203 ;
     RECT  66.048 68.675 67.512 69.203 ;
     RECT  43.776 67.717 43.8 69.299 ;
     RECT  39.216 68.771 41.592 69.491 ;
     RECT  68.544 68.435 69.192 69.491 ;
     RECT  15.984 68.917 19.368 69.493 ;
     RECT  71.808 68.149 72.912 69.539 ;
     RECT  30.96 68.675 31.32 69.587 ;
     RECT  53.712 69.011 57.96 69.587 ;
     RECT  60.432 68.341 62.112 69.587 ;
     RECT  66.96 69.203 67.512 69.683 ;
     RECT  32.688 67.907 32.712 69.781 ;
     RECT  32.496 69.781 32.712 69.827 ;
     RECT  9.408 68.917 9.432 69.875 ;
     RECT  39.744 69.491 41.592 69.877 ;
     RECT  39.744 69.877 42.456 69.973 ;
     RECT  39.744 69.973 42.648 70.019 ;
     RECT  45.6 69.203 46.296 70.019 ;
     RECT  21.552 68.243 22.2 70.021 ;
     RECT  24 67.907 25.128 70.069 ;
     RECT  26.448 69.011 28.392 70.069 ;
     RECT  50.784 69.011 51.912 70.163 ;
     RECT  53.712 69.587 54.168 70.163 ;
     RECT  53.712 70.163 53.736 70.499 ;
     RECT  12.336 66.659 13.512 70.597 ;
     RECT  21.216 70.021 22.2 70.597 ;
     RECT  21.072 70.597 22.2 70.643 ;
     RECT  32.496 69.827 32.52 70.643 ;
     RECT  37.2 66.755 37.224 70.643 ;
     RECT  49.536 68.485 49.704 70.643 ;
     RECT  63.744 69.155 64.68 70.645 ;
     RECT  42.432 70.019 42.648 70.691 ;
     RECT  63.216 70.645 64.68 70.691 ;
     RECT  11.808 70.597 13.512 70.693 ;
     RECT  34.8 67.331 35.64 70.693 ;
     RECT  11.808 70.693 14.232 70.739 ;
     RECT  15.648 69.493 19.368 70.739 ;
     RECT  24 70.069 28.392 70.739 ;
     RECT  39.744 70.019 41.304 70.739 ;
     RECT  49.68 70.643 49.704 70.739 ;
     RECT  55.536 69.587 57.576 70.739 ;
     RECT  16.8 70.739 19.368 70.835 ;
     RECT  39.936 70.739 41.304 70.835 ;
     RECT  42.624 70.691 42.648 70.835 ;
     RECT  30.96 69.587 30.984 70.933 ;
     RECT  47.616 68.869 47.64 70.933 ;
     RECT  16.8 70.835 19.08 71.075 ;
     RECT  45.6 70.019 46.008 71.173 ;
     RECT  13.2 70.739 14.232 71.219 ;
     RECT  21.072 70.643 21.432 71.221 ;
     RECT  67.2 69.683 67.512 71.221 ;
     RECT  68.544 69.491 69 71.221 ;
     RECT  20.16 71.221 21.432 71.267 ;
     RECT  67.2 71.221 69 71.267 ;
     RECT  27.6 70.739 28.392 71.315 ;
     RECT  39.936 70.835 40.512 71.315 ;
     RECT  55.536 70.739 57.528 71.315 ;
     RECT  59.232 69.011 59.256 71.315 ;
     RECT  63.216 70.691 63.816 71.315 ;
     RECT  44.736 71.173 46.008 71.411 ;
     RECT  20.16 71.267 21.096 71.459 ;
     RECT  67.2 71.267 68.568 71.507 ;
     RECT  18.6 71.075 19.08 71.795 ;
     RECT  24 70.739 25.896 71.843 ;
     RECT  63.792 71.315 63.816 71.843 ;
     RECT  68.544 71.507 68.568 71.843 ;
     RECT  38.736 71.221 38.76 71.891 ;
     RECT  47.328 70.933 47.64 71.891 ;
     RECT  17.04 71.075 17.064 71.939 ;
     RECT  30.96 70.933 31.032 71.939 ;
     RECT  50.784 70.163 51.312 71.939 ;
     RECT  56.4 71.315 57.528 71.987 ;
     RECT  34.8 70.693 35.832 72.181 ;
     RECT  25.872 71.843 25.896 72.227 ;
     RECT  34.704 72.181 35.832 72.227 ;
     RECT  56.4 71.987 57.144 72.371 ;
     RECT  47.328 71.891 47.352 72.419 ;
     RECT  27.6 71.315 28.344 72.467 ;
     RECT  34.704 72.227 35.352 72.467 ;
     RECT  56.4 72.371 56.808 72.467 ;
     RECT  22.944 71.125 22.968 72.515 ;
     RECT  54.672 71.701 54.696 72.659 ;
     RECT  61.008 69.587 62.112 72.659 ;
     RECT  40.08 71.315 40.512 72.851 ;
     RECT  20.16 71.459 20.184 72.947 ;
     RECT  24 71.843 24.744 72.995 ;
     RECT  27.6 72.467 27.624 72.995 ;
     RECT  34.704 72.467 35.112 72.995 ;
     RECT  42.768 72.949 42.792 73.091 ;
     RECT  44.736 71.411 45.912 73.091 ;
     RECT  31.008 71.939 31.032 73.379 ;
     RECT  2.4 67.283 2.712 73.449 ;
     RECT  7.8 68.243 8.112 73.449 ;
     RECT  13.2 71.219 13.512 73.449 ;
     RECT  18.6 71.795 18.912 73.449 ;
     RECT  24 72.995 24.312 73.449 ;
     RECT  29.4 69.011 29.712 73.449 ;
     RECT  34.8 72.995 35.112 73.449 ;
     RECT  40.2 72.851 40.512 73.449 ;
     RECT  45.6 73.091 45.912 73.449 ;
     RECT  51 71.939 51.312 73.449 ;
     RECT  56.4 72.467 56.712 73.449 ;
     RECT  61.8 72.659 62.112 73.449 ;
     RECT  67.2 71.507 67.512 73.449 ;
     RECT  72.6 69.539 72.912 73.449 ;
     RECT  2.4 73.449 2.52 73.463 ;
     RECT  7.8 73.449 7.92 73.463 ;
     RECT  13.2 73.449 13.32 73.463 ;
     RECT  18.6 73.449 18.72 73.463 ;
     RECT  24 73.449 24.12 73.463 ;
     RECT  29.4 73.449 29.52 73.463 ;
     RECT  34.8 73.449 34.92 73.463 ;
     RECT  40.2 73.449 40.32 73.463 ;
     RECT  45.6 73.449 45.72 73.463 ;
     RECT  51 73.449 51.12 73.463 ;
     RECT  56.4 73.449 56.52 73.463 ;
     RECT  61.8 73.449 61.92 73.463 ;
     RECT  67.2 73.449 67.32 73.463 ;
     RECT  72.6 73.449 72.72 73.463 ;
  END
END dsdv_mu_hslot
END LIBRARY
